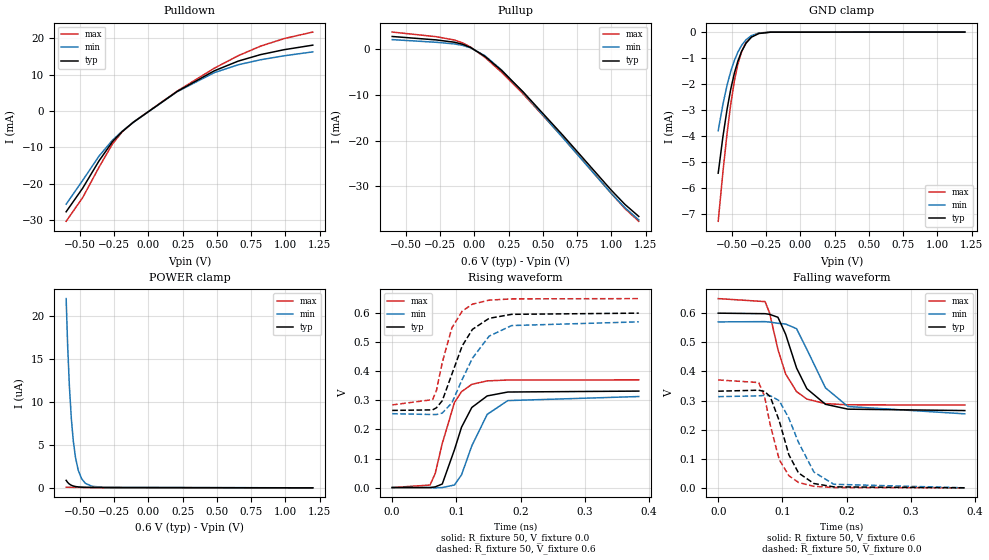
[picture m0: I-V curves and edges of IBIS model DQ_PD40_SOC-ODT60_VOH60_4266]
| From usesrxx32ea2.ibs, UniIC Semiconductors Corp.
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| DQ_PD40_SOC-ODT60_VOH60_4266
| (40 Ohm Pulldown, 60 Ohm System ODT Setting, VOH=VDDQ*0.60, 3200-4266Mbps)
[Model]   DQ_PD40_SOC-ODT60_VOH60_4266
Model_type   I/O
Vinl = 120.000mV
Vinh = 240.000mV
Vmeas = 180.000mV
Vref = 0.0mV
Cref = 0.0pF
Rref = 60.000Ohm
|   typ   min   max
|C_comp   0.834pF   0.784pF   0.884pF
C_comp_pullup   0.4170pF   0.3920pF   0.4420pF
C_comp_pulldown   0.4170pF   0.3920pF   0.4420pF
| Note: C_comp changes when the ODT circuit is enabled.
[Model Spec]
| Input threshold voltage corners
Vinl   0.1200V   0.1110V   0.1350V
Vinh   0.2400V   0.2310V   0.2550V
| Measurement voltage corners
Vmeas   0.1800V   0.1710V   0.1950V
| Timing spec test load voltage corners
Vref   0.0000V   0.0000V   0.0000V
| Dynamic Overshoot Parameters from LPDDR4_0P6 Specification
D_overshoot_ampl_h   0.30   NA   NA
D_overshoot_ampl_l   0.30   NA   NA
D_overshoot_area_h   0.1n   NA   NA
D_overshoot_area_l   0.1n   NA   NA
[Voltage Range]   0.6000V   0.5700V   0.6500V
[Pullup Reference]   0.6000V   0.5700V   0.6500V
| Junction Temperature (Ambient temp is 35C typ 95C min -40C max)
[Temperature Range]   50.0   110.0   -40.0
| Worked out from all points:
|   slope of the pulldown table from 0 to 0.09 V, typ, clamps not added: 37.5 ohm
|   slope of the pullup table from 0 to 0.09 V, typ, clamps not added: 49.6 ohm
|   GND clamp passes 1 mA (typ) near -0.45 V on its own axis
|   rising waveform, R_fixture 50, V_fixture 0.0: 20-80 % time 31.9ps typ, 36.1ps min, 27.6ps max; typ from 0 V to 0.332 V
|   falling waveform, R_fixture 50, V_fixture 0.6: 20-80 % time 36.6ps typ, 44.7ps min, 30.1ps max; typ from 0.6 V to 0.265 V
|   rising waveform, R_fixture 50, V_fixture 0.6: 20-80 % time 36.4ps typ, 45.7ps min, 27.6ps max; typ from 0.265 V to 0.6 V
|   falling waveform, R_fixture 50, V_fixture 0.0: 20-80 % time 29.8ps typ, 38.2ps min, 25.6ps max; typ from 0.332 V to 0 V
[Pulldown]
|   Voltage   I(typ)   I(min)   I(max)
-600mV    -27.74mA   -25.65mA   -30.36mA
-479.4mV  -21.24mA   -19.1mA    -23.84mA
-360.6mV  -13.75mA   -12.43mA   -15.5mA
-261.6mV  -8.423mA   -8.009mA   -9.041mA
-191.4mV  -5.659mA   -5.575mA   -5.739mA
-108.6mV  -3.064mA   -3.066mA   -3.02mA
210mV     5.393mA    5.318mA    5.481mA
481.8mV   11.09mA    10.59mA    11.81mA
656.4mV   13.76mA    12.75mA    15.25mA
818.4mV   15.54mA    14.12mA    17.87mA
991.2mV   16.9mA     15.22mA    19.96mA
1.2V      18.15mA    16.3mA     21.76mA
[GND Clamp]
|   Voltage   I(typ)   I(min)   I(max)
-600mV    -5.44mA    -3.802mA   -7.294mA
-565.8mV  -4.041mA   -2.789mA   -5.405mA
-535.2mV  -2.974mA   -2.045mA   -3.902mA
-508.2mV  -2.194mA   -1.511mA   -2.769mA
-481.2mV  -1.568mA   -1.084mA   -1.86mA
-456mV    -1.113mA   -769.2uA   -1.229mA
-429mV    -741.6uA   -510.5uA   -756.3uA
-396.6mV  -428.1uA   -294.1uA   -396.7uA
-357mV    -196.9uA   -136.7uA   -160uA
-303mV    -56.19uA   -40.99uA   -37.04uA
-216.6mV  -4.962uA   -4.45uA    -2.042uA
1.2V      0A         0A         0A
[Pullup]
|   Voltage   I(typ)   I(min)   I(max)
-600mV    2.847mA    2.16mA     3.822mA
-277.8mV  2.093mA    1.573mA    2.795mA
-144.6mV  1.58mA     1.207mA    2.065mA
-87mV     1.141mA    901.9uA    1.451mA
-27.6mV   424.6uA    349.9uA    523.8uA
76.8mV    -1.511mA   -1.368mA   -1.731mA
199.2mV   -4.645mA   -4.526mA   -5.034mA
355.8mV   -9.325mA   -9.456mA   -9.771mA
643.8mV   -18.78mA   -19.32mA   -19.25mA
1V        -30.93mA   -31.63mA   -31.64mA
1.099V    -34.03mA   -34.74mA   -34.95mA
1.2V      -36.67mA   -37.43mA   -37.73mA
[POWER Clamp]
|   Voltage   I(typ)   I(min)   I(max)
-600mV    870.6nA    21.99uA    72.65nA
-589.2mV  630.2nA    16.59uA    68.66nA
-576.6mV  439nA      11.87uA    64.76nA
-562.2mV  298.6nA    8.053uA    60.55nA
-547.8mV  210.8nA    5.444uA    56.57nA
-531.6mV  149.2nA    3.499uA    52.36nA
-511.8mV  106.2nA    2.041uA    47.56nA
-486.6mV  77.19nA    1.041uA    41.98nA
-459.6mV  61.25nA    521.5nA    36.6nA
-411mV    46.96nA    175nA      28.35nA
-319.2mV  33.34nA    56.57nA    16.92nA
1.2V      0A         0A         0A
[Ramp]
|   typ   min   max
| 20% - 80%
dV/dt_r   199.06m/31.85p   187.84m/36.08p   222.28m/27.64p
dV/dt_f   200.72m/36.59p   189.47m/44.70p   219.39m/30.09p
| 25% - 75%
|dV/dt_r   165.88m/25.19p   156.53m/28.57p   185.23m/21.78p
|dV/dt_f   167.26m/28.84p   157.89m/35.34p   182.82m/23.68p
R_load = 50
[Rising Waveform]
R_fixture = 50
V_fixture = 0.0
|   Time   V(typ)   V(min)   V(max)
0s        154.1uV    137uV      73.21uV
59ps      234.1uV    -295.8uV   8.761mV
67ps      2.405mV    -843.8uV   48.45mV
78ps      12.41mV    131.3uV    151.8mV
97ps      130.4mV    8.965mV    292.8mV
108ps     207.8mV    43.94mV    330mV
124ps     275.6mV    143.6mV    355.1mV
148ps     315.3mV    252mV      367mV
180ps     328.7mV    299.2mV    370mV
384ps     331.9mV    313.2mV    370.5mV
[Falling Waveform]
R_fixture   = 50
V_fixture   = 0.6
V_fixture_min = 0.57
V_fixture_max = 0.65
|   Time   V(typ)   V(min)   V(max)
0s        600mV      570mV      650mV
73ps      598.2mV    570.9mV    639.7mV
80ps      596mV      569.5mV    600.6mV
93ps      585.9mV    565.2mV    475.3mV
105ps     527.5mV    562.7mV    391.2mV
122ps     411.7mV    546.7mV    330.6mV
138ps     340.6mV    475.9mV    305.1mV
167ps     287mV      343.5mV    289.3mV
202ps     270.3mV    279.4mV    285.2mV
384ps     265.5mV    254.2mV    284.4mV
[Rising Waveform]
R_fixture   = 50
V_fixture   = 0.6
V_fixture_min = 0.57
V_fixture_max = 0.65
|   Time   V(typ)   V(min)   V(max)
0s        265.4mV    254.1mV    284.4mV
63ps      267.3mV    251.3mV    302.5mV
69ps      274.6mV    251.3mV    334.7mV
78ps      298.9mV    256.3mV    430.3mV
93ps      390.4mV    291.6mV    549.5mV
109ps     487.2mV    371.9mV    606.9mV
125ps     544.3mV    445.1mV    631mV
151ps     582.2mV    521mV      644.7mV
186ps     595.9mV    557.3mV    649mV
384ps     600mV      570mV      650mV
[Falling Waveform]
R_fixture = 50
V_fixture = 0.0
|   Time   V(typ)   V(min)   V(max)
0s        332mV      313.3mV    370.6mV
63ps      335.4mV    315.9mV    361.7mV
72ps      331.4mV    317.7mV    315.8mV
81ps      313.1mV    316.6mV    216.5mV
95ps      230.6mV    299.5mV    96.9mV
110ps     113.8mV    239.3mV    41.9mV
125ps     51.38mV    156.5mV    18.54mV
149ps     14.93mV    54.36mV    5.217mV
180ps     3.393mV    12.27mV    1.123mV
384ps     206uV      212uV      92uV
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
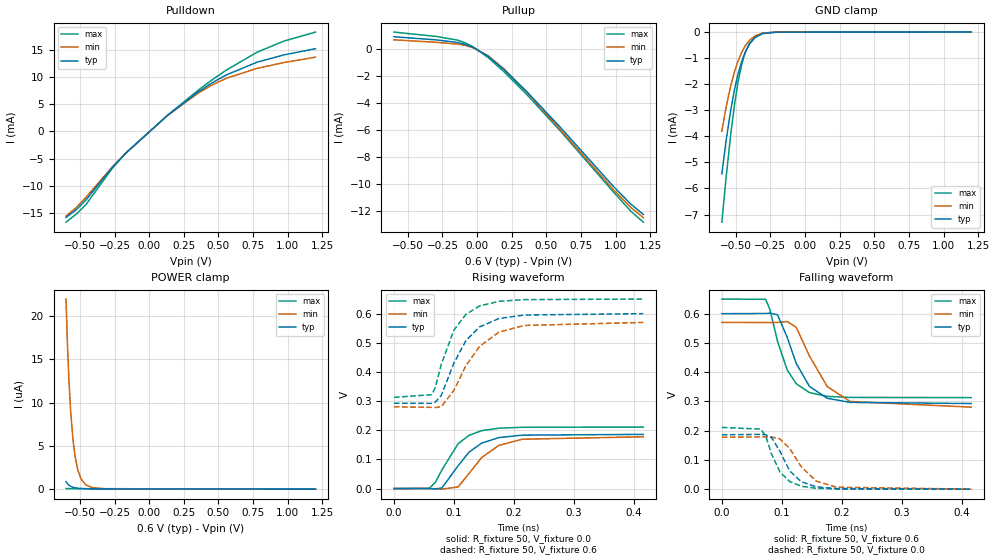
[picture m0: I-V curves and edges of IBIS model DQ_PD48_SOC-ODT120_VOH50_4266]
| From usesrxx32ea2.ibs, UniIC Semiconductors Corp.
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| DQ_PD48_SOC-ODT120_VOH50_4266
| (48 Ohm Pulldown, 120 Ohm System ODT Setting, VOH=VDDQ*0.50, 3200-4266Mbps)
[Model]   DQ_PD48_SOC-ODT120_VOH50_4266
Model_type   I/O
Vinl = 90.000mV
Vinh = 210.000mV
Vmeas = 150.000mV
Vref = 0.0mV
Cref = 0.0pF
Rref = 120.000Ohm
|   typ   min   max
|C_comp   0.834pF   0.784pF   0.884pF
C_comp_pullup   0.4170pF   0.3920pF   0.4420pF
C_comp_pulldown   0.4170pF   0.3920pF   0.4420pF
| Note: C_comp changes when the ODT circuit is enabled.
[Model Spec]
| Input threshold voltage corners
Vinl   0.0900V   0.0825V   0.1025V
Vinh   0.2100V   0.2025V   0.2225V
| Measurement voltage corners
Vmeas   0.1500V   0.1425V   0.1625V
| Timing spec test load voltage corners
Vref   0.0000V   0.0000V   0.0000V
| Dynamic Overshoot Parameters from LPDDR4_0P6 Specification
D_overshoot_ampl_h   0.30   NA   NA
D_overshoot_ampl_l   0.30   NA   NA
D_overshoot_area_h   0.1n   NA   NA
D_overshoot_area_l   0.1n   NA   NA
[Voltage Range]   0.6000V   0.5700V   0.6500V
[Pullup Reference]   0.6000V   0.5700V   0.6500V
| Junction Temperature (Ambient temp is 35C typ 95C min -40C max)
[Temperature Range]   50.0   110.0   -40.0
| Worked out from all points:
|   slope of the pulldown table from 0 to 0.09 V, typ, clamps not added: 44.6 ohm
|   slope of the pullup table from 0 to 0.09 V, typ, clamps not added: 150 ohm
|   GND clamp passes 1 mA (typ) near -0.45 V on its own axis
|   rising waveform, R_fixture 50, V_fixture 0.0: 20-80 % time 45.3ps typ, 49.4ps min, 40.1ps max; typ from 0 V to 0.186 V
|   falling waveform, R_fixture 50, V_fixture 0.6: 20-80 % time 39ps typ, 47.3ps min, 32.4ps max; typ from 0.6 V to 0.293 V
|   rising waveform, R_fixture 50, V_fixture 0.6: 20-80 % time 47.1ps typ, 55.2ps min, 39.5ps max; typ from 0.293 V to 0.6 V
|   falling waveform, R_fixture 50, V_fixture 0.0: 20-80 % time 31.6ps typ, 39.2ps min, 28.1ps max; typ from 0.186 V to 0 V
[Pulldown]
|   Voltage   I(typ)   I(min)   I(max)
-600mV    -15.79mA   -15.53mA   -16.65mA
-524.4mV  -14.33mA   -13.93mA   -15.14mA
-456mV    -12.58mA   -12.09mA   -13.41mA
-267mV    -6.63mA    -6.533mA   -6.813mA
-164.4mV  -3.891mA   -3.903mA   -3.858mA
130.8mV   2.897mA    2.872mA    2.921mA
355.8mV   7.285mA    7.07mA     7.589mA
462mV     9.018mA    8.62mA     9.591mA
555.6mV   10.34mA    9.725mA    11.22mA
778.8mV   12.69mA    11.56mA    14.52mA
971.4mV   14.02mA    12.62mA    16.55mA
1.2V      15.16mA    13.61mA    18.21mA
[GND Clamp]
|   Voltage   I(typ)   I(min)   I(max)
-600mV    -5.439mA   -3.802mA   -7.294mA
-567.6mV  -4.11mA    -2.837mA   -5.5mA
-535.2mV  -2.973mA   -2.045mA   -3.902mA
-508.2mV  -2.194mA   -1.512mA   -2.769mA
-483mV    -1.606mA   -1.109mA   -1.913mA
-456mV    -1.113mA   -769.7uA   -1.229mA
-430.8mV  -763.4uA   -525.4uA   -782.8uA
-398.4mV  -442.4uA   -303.3uA   -412.3uA
-358.8mV  -205.3uA   -142.5uA   -167.5uA
-304.8mV  -58.93uA   -42.66uA   -39.07uA
-207.6mV  -3.725uA   -3.453uA   -1.424uA
1.2V      0A         0A         0A
[Pullup]
|   Voltage   I(typ)   I(min)   I(max)
-600mV    931.5uA    702.4uA    1.276mA
-294mV    697.1uA    519.5uA    954.8uA
-141mV    508.1uA    384.5uA    681.7uA
-87mV     372.5uA    291.3uA    487.5uA
-25.8mV   130.7uA    107uA      165.5uA
80.4mV    -526.3uA   -474.5uA   -615.3uA
195.6mV   -1.508mA   -1.462mA   -1.671mA
359.4mV   -3.141mA   -3.185mA   -3.356mA
604.2mV   -5.817mA   -5.987mA   -6.087mA
980.4mV   -10.12mA   -10.36mA   -10.53mA
1.11V     -11.47mA   -11.72mA   -12mA
1.2V      -12.24mA   -12.48mA   -12.81mA
[POWER Clamp]
|   Voltage   I(typ)   I(min)   I(max)
-600mV    870.7nA    21.99uA    72.65nA
-589.2mV  630.1nA    16.59uA    68.66nA
-578.4mV  461.9nA    12.46uA    65.31nA
-565.8mV  327.8nA    8.879uA    61.58nA
-549.6mV  219.3nA    5.719uA    57.05nA
-535.2mV  160.1nA    3.857uA    53.27nA
-515.4mV  112.2nA    2.246uA    48.4nA
-492mV    81.83nA    1.199uA    43.12nA
-459.6mV  61.24nA    520.9nA    36.6nA
-412.8mV  47.34nA    181.1nA    28.62nA
-319.2mV  33.36nA    56.64nA    16.92nA
1.2V      0A         0A         0A
[Ramp]
|   typ   min   max
| 20% - 80%
dV/dt_r   111.55m/45.26p   106.53m/49.42p   126.62m/40.06p
dV/dt_f   184.34m/39.04p   173.67m/47.34p   202.22m/32.44p
| 25% - 75%
|dV/dt_r   92.95m/35.92p   88.78m/39.20p   105.51m/31.69p
|dV/dt_f   153.62m/30.90p   144.73m/37.48p   168.52m/25.62p
R_load = 50
[Rising Waveform]
R_fixture = 50
V_fixture = 0.0
|   Time   V(typ)   V(min)   V(max)
0s        39.88uV    23.63uV    24.38uV
59ps      -381.8uV   300.7uV    1.033mV
69ps      -1.414mV   -524.2uV   21.13mV
80ps      2.191mV    -2.035mV   63.69mV
107ps     77.91mV    5.664mV    153.7mV
125ps     124.4mV    51.05mV    182.3mV
146ps     155.6mV    105.7mV    198.5mV
175ps     174.9mV    148.1mV    207.1mV
214ps     183.2mV    169.3mV    210.2mV
416ps     185.9mV    177.6mV    211.1mV
[Falling Waveform]
R_fixture   = 50
V_fixture   = 0.6
V_fixture_min = 0.57
V_fixture_max = 0.65
|   Time   V(typ)   V(min)   V(max)
0s        600mV      570mV      650mV
73ps      600.7mV    569.9mV    649.2mV
80ps      601.9mV    569.6mV    615.3mV
93ps      596.2mV    570.2mV    505.1mV
109ps     519.3mV    573.1mV    407.7mV
124ps     430.3mV    553.6mV    360.8mV
146ps     351.7mV    455.8mV    330.3mV
176ps     310.7mV    350.2mV    317.3mV
214ps     296.7mV    299.9mV    313.7mV
416ps     292.8mV    280.5mV    313mV
[Rising Waveform]
R_fixture   = 50
V_fixture   = 0.6
V_fixture_min = 0.57
V_fixture_max = 0.65
|   Time   V(typ)   V(min)   V(max)
0s        292.7mV    280.5mV    312.9mV
63ps      292.3mV    278.5mV    322mV
69ps      296.6mV    277.9mV    346.8mV
79ps      319.8mV    280.9mV    426.2mV
100ps     430.2mV    336.5mV    543.4mV
120ps     507.4mV    421.4mV    597.6mV
143ps     554.7mV    488.1mV    626.5mV
175ps     583mV      536.3mV    642.2mV
217ps     595.2mV    559.5mV    648.1mV
416ps     600mV      569.9mV    650mV
[Falling Waveform]
R_fixture = 50
V_fixture = 0.0
|   Time   V(typ)   V(min)   V(max)
0s        186mV      177.7mV    211.1mV
65ps      187.3mV    178.6mV    205.4mV
73ps      186.1mV    179.1mV    182.6mV
83ps      176.4mV    178.7mV    119.4mV
97ps      129.1mV    171.5mV    58.61mV
113ps     63.19mV    139.6mV    26.42mV
132ps     25.99mV    78.03mV    10.35mV
157ps     8.285mV    27.92mV    3.069mV
191ps     1.89mV     6.737mV    625.1uV
416ps     106.9uV    113.1uV    44.52uV
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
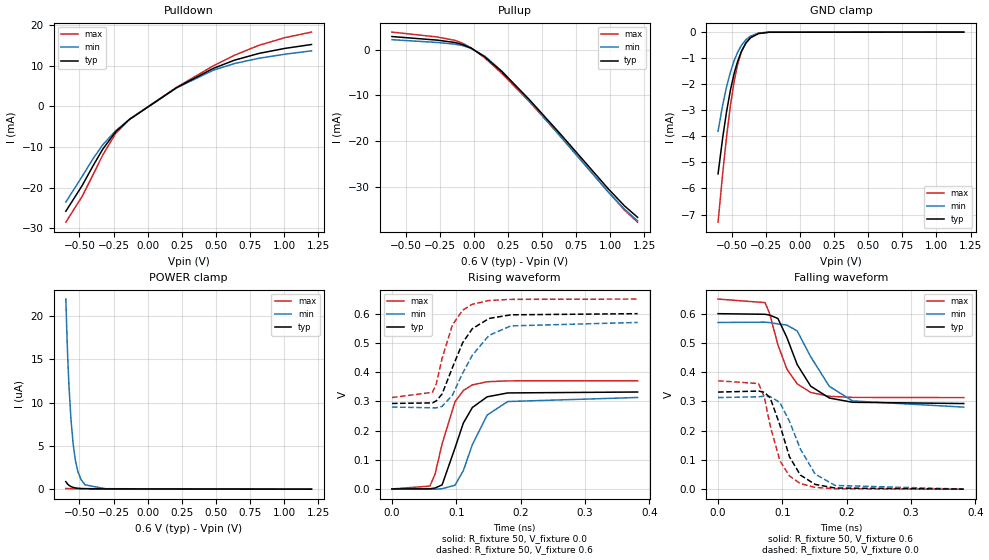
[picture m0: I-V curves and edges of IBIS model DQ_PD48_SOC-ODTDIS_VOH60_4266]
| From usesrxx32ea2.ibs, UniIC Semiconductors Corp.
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| DQ_PD48_SOC-ODTDIS_VOH60_4266
| (48 Ohm Pulldown, SOC ODT disabled setting, VOH=VDDQ*0.60 cal. point, 3200-4266Mbps)
[Model]   DQ_PD48_SOC-ODTDIS_VOH60_4266
Model_type   I/O
Vinl = 120.000mV
Vinh = 240.000mV
Vmeas = 180.000mV
Vref = 0.0mV
Cref = 0.0pF
|   typ   min   max
|C_comp   0.834pF   0.784pF   0.884pF
C_comp_pullup   0.4170pF   0.3920pF   0.4420pF
C_comp_pulldown   0.4170pF   0.3920pF   0.4420pF
| Note: C_comp changes when the ODT circuit is enabled.
[Model Spec]
| Input threshold voltage corners
Vinl   0.1200V   0.1110V   0.1350V
Vinh   0.2400V   0.2310V   0.2550V
| Measurement voltage corners
Vmeas   0.1800V   0.1710V   0.1950V
| Timing spec test load voltage corners
Vref   0.0000V   0.0000V   0.0000V
| Dynamic Overshoot Parameters from LPDDR4_0P6 Specification
D_overshoot_ampl_h   0.30   NA   NA
D_overshoot_ampl_l   0.30   NA   NA
D_overshoot_area_h   0.1n   NA   NA
D_overshoot_area_l   0.1n   NA   NA
[Voltage Range]   0.6000V   0.5700V   0.6500V
[Pullup Reference]   0.6000V   0.5700V   0.6500V
| Junction Temperature (Ambient temp is 35C typ 95C min -40C max)
[Temperature Range]   50.0   110.0   -40.0
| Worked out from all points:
|   slope of the pulldown table from 0 to 0.09 V, typ, clamps not added: 44.5 ohm
|   slope of the pullup table from 0 to 0.09 V, typ, clamps not added: 49.6 ohm
|   GND clamp passes 1 mA (typ) near -0.45 V on its own axis
|   rising waveform, R_fixture 50, V_fixture 0.0: 20-80 % time 32ps typ, 36.3ps min, 27.7ps max; typ from 0 V to 0.332 V
|   falling waveform, R_fixture 50, V_fixture 0.6: 20-80 % time 39.6ps typ, 48.2ps min, 32.7ps max; typ from 0.6 V to 0.293 V
|   rising waveform, R_fixture 50, V_fixture 0.6: 20-80 % time 37ps typ, 45.9ps min, 27.7ps max; typ from 0.293 V to 0.6 V
|   falling waveform, R_fixture 50, V_fixture 0.0: 20-80 % time 31.4ps typ, 39.1ps min, 27.4ps max; typ from 0.332 V to 0 V
[Pulldown]
|   Voltage   I(typ)   I(min)   I(max)
-600mV    -25.78mA   -23.53mA   -28.46mA
-481.2mV  -19.52mA   -17.27mA   -22.18mA
-400.2mV  -14.61mA   -12.86mA   -16.79mA
-330mV    -10.56mA   -9.488mA   -12.01mA
-234.6mV  -6.263mA   -5.995mA   -6.65mA
-133.8mV  -3.233mA   -3.221mA   -3.206mA
211.8mV   4.574mA    4.505mA    4.659mA
481.8mV   9.314mA    8.873mA    9.947mA
636.6mV   11.32mA    10.5mA     12.53mA
813mV     12.96mA    11.77mA    14.94mA
1.004V    14.2mA     12.77mA    16.83mA
1.2V      15.16mA    13.61mA    18.21mA
[GND Clamp]
|   Voltage   I(typ)   I(min)   I(max)
-600mV    -5.44mA    -3.803mA   -7.293mA
-565.8mV  -4.041mA   -2.789mA   -5.405mA
-537mV    -3.03mA    -2.085mA   -3.984mA
-508.2mV  -2.193mA   -1.513mA   -2.769mA
-481.2mV  -1.568mA   -1.083mA   -1.86mA
-457.8mV  -1.141mA   -787.2uA   -1.267mA
-429mV    -741.4uA   -509.7uA   -756.1uA
-396.6mV  -428.9uA   -294.7uA   -396.9uA
-360.6mV  -212.8uA   -146.9uA   -174.7uA
-303mV    -56.2uA    -40.81uA   -37.15uA
-227.4mV  -6.904uA   -5.978uA   -3.035uA
1.2V      0A         0A         0A
[Pullup]
|   Voltage   I(typ)   I(min)   I(max)
-600mV    2.847mA    2.16mA     3.822mA
-268.8mV  2.067mA    1.554mA    2.759mA
-139.2mV  1.548mA    1.186mA    2.02mA
-85.2mV   1.123mA    889uA      1.427mA
-20.4mV   319.4uA    265.2uA    393uA
80.4mV    -1.596mA   -1.447mA   -1.819mA
204.6mV   -4.797mA   -4.683mA   -5.19mA
399mV     -10.69mA   -10.9mA    -11.14mA
629.4mV   -18.29mA   -18.82mA   -18.76mA
985.8mV   -30.46mA   -31.15mA   -31.14mA
1.103V    -34.14mA   -34.85mA   -35.06mA
1.2V      -36.67mA   -37.44mA   -37.73mA
[POWER Clamp]
|   Voltage   I(typ)   I(min)   I(max)
-600mV    870.6nA    21.99uA    72.65nA
-589.2mV  630.2nA    16.59uA    68.66nA
-583.8mV  538.6nA    14.39uA    66.96nA
-576.6mV  439.6nA    11.87uA    64.76nA
-562.2mV  298.7nA    8.059uA    60.54nA
-546mV    201.8nA    5.192uA    56.09nA
-529.8mV  143.9nA    3.333uA    51.9nA
-511.8mV  106nA      2.046uA    47.56nA
-488.4mV  78.51nA    1.092uA    42.35nA
-457.8mV  60.4nA     497.3nA    36.26nA
-310.2mV  32.34nA    53.65nA    16.04nA
1.2V      0A         0A         0A
[Ramp]
|   typ   min   max
| 20% - 80%
dV/dt_r   199.04m/31.96p   187.82m/36.27p   222.27m/27.70p
dV/dt_f   184.34m/39.59p   173.63m/48.23p   202.23m/32.68p
| 25% - 75%
|dV/dt_r   165.87m/25.26p   156.52m/28.71p   185.23m/21.83p
|dV/dt_f   153.62m/31.27p   144.69m/38.15p   168.53m/25.78p
R_load = 50
[Rising Waveform]
R_fixture = 50
V_fixture = 0.0
|   Time   V(typ)   V(min)   V(max)
0s        177.8uV    163.1uV    83.28uV
59ps      598.4uV    -307.3uV   9.952mV
67ps      3.254mV    -614.4uV   50.5mV
78ps      14.01mV    955.7uV    154.4mV
98ps      140mV      12.78mV    298.2mV
111ps     225.4mV    62.77mV    337.1mV
125ps     278.8mV    151.5mV    356.2mV
148ps     315.4mV    252.7mV    367mV
180ps     328.7mV    299.3mV    370mV
382ps     331.9mV    313.2mV    370.5mV
[Falling Waveform]
R_fixture   = 50
V_fixture   = 0.6
V_fixture_min = 0.57
V_fixture_max = 0.65
|   Time   V(typ)   V(min)   V(max)
0s        600mV      570mV      650mV
73ps      598mV      571mV      637.9mV
80ps      595.3mV    569.7mV    601.9mV
93ps      583.7mV    565mV      493.9mV
107ps     518.6mV    561mV      410.4mV
123ps     426.2mV    541mV      360.2mV
144ps     352.3mV    452.9mV    330.8mV
173ps     311.7mV    351.7mV    317.6mV
209ps     297.2mV    301.8mV    313.9mV
382ps     292.8mV    280.6mV    313mV
[Rising Waveform]
R_fixture   = 50
V_fixture   = 0.6
V_fixture_min = 0.57
V_fixture_max = 0.65
|   Time   V(typ)   V(min)   V(max)
0s        292.7mV    280.5mV    312.9mV
63ps      294.6mV    277.8mV    330.8mV
69ps      301.7mV    277.8mV    359.7mV
78ps      325.1mV    282.7mV    446.8mV
94ps      415.3mV    320.8mV    561.5mV
110ps     500.6mV    396.8mV    611.9mV
125ps     548.6mV    457.9mV    632.3mV
151ps     583.6mV    525.9mV    645.1mV
185ps     596.1mV    558.2mV    649mV
382ps     600mV      570mV      650mV
[Falling Waveform]
R_fixture = 50
V_fixture = 0.0
|   Time   V(typ)   V(min)   V(max)
0s        332mV      313.3mV    370.6mV
63ps      335.5mV    315.9mV    361.1mV
72ps      331.3mV    317.8mV    314.4mV
81ps      312.3mV    316.8mV    217.4mV
96ps      220.4mV    296.5mV    98.04mV
111ps     111mV      232.3mV    45.28mV
128ps     48.31mV    137.4mV    19.22mV
151ps     16.28mV    51.42mV    6.199mV
182ps     4.046mV    12.85mV    1.458mV
382ps     228.4uV    238uV      101.9uV
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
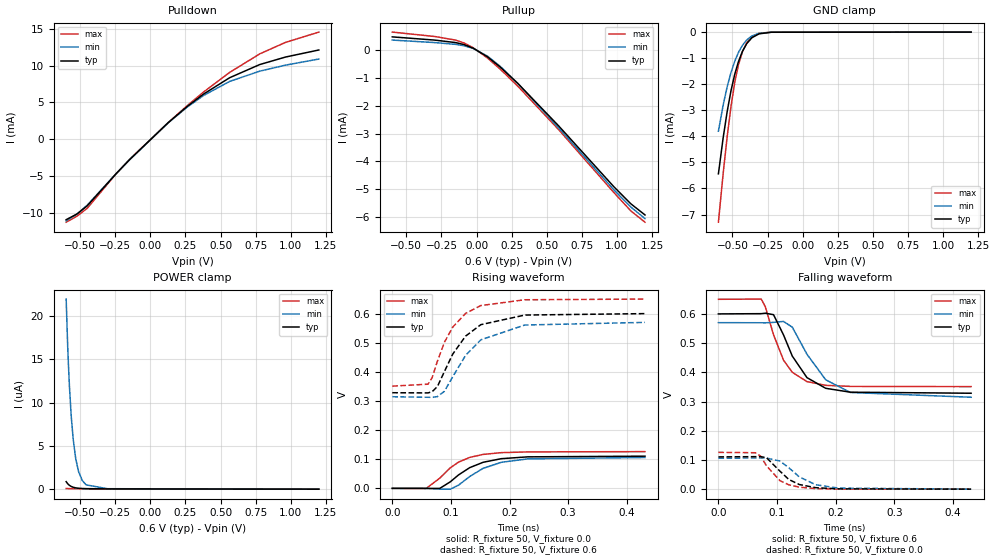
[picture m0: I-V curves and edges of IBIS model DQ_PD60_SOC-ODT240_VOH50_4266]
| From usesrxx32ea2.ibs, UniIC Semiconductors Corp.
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| DQ_PD60_SOC-ODT240_VOH50_4266
| (60 Ohm Pulldown, 240 Ohm System ODT Setting, VOH=VDDQ*0.50, 3200-4266Mbps)
[Model]   DQ_PD60_SOC-ODT240_VOH50_4266
Model_type   I/O
Vinl = 90.000mV
Vinh = 210.000mV
Vmeas = 150.000mV
Vref = 0.0mV
Cref = 0.0pF
Rref = 240.000Ohm
|   typ   min   max
|C_comp   0.834pF   0.784pF   0.884pF
C_comp_pullup   0.4170pF   0.3920pF   0.4420pF
C_comp_pulldown   0.4170pF   0.3920pF   0.4420pF
| Note: C_comp changes when the ODT circuit is enabled.
[Model Spec]
| Input threshold voltage corners
Vinl   0.0900V   0.0825V   0.1025V
Vinh   0.2100V   0.2025V   0.2225V
| Measurement voltage corners
Vmeas   0.1500V   0.1425V   0.1625V
| Timing spec test load voltage corners
Vref   0.0000V   0.0000V   0.0000V
| Dynamic Overshoot Parameters from LPDDR4_0P6 Specification
D_overshoot_ampl_h   0.30   NA   NA
D_overshoot_ampl_l   0.30   NA   NA
D_overshoot_area_h   0.1n   NA   NA
D_overshoot_area_l   0.1n   NA   NA
[Voltage Range]   0.6000V   0.5700V   0.6500V
[Pullup Reference]   0.6000V   0.5700V   0.6500V
| Junction Temperature (Ambient temp is 35C typ 95C min -40C max)
[Temperature Range]   50.0   110.0   -40.0
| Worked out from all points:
|   slope of the pulldown table from 0 to 0.09 V, typ, clamps not added: 55.8 ohm
|   slope of the pullup table from 0 to 0.09 V, typ, clamps not added: 306 ohm
|   GND clamp passes 1 mA (typ) near -0.45 V on its own axis
|   rising waveform, R_fixture 50, V_fixture 0.0: 20-80 % time 54.2ps typ, 57ps min, 47.9ps max; typ from 0 V to 0.11 V
|   falling waveform, R_fixture 50, V_fixture 0.6: 20-80 % time 43ps typ, 51.7ps min, 35.9ps max; typ from 0.6 V to 0.328 V
|   rising waveform, R_fixture 50, V_fixture 0.6: 20-80 % time 52.8ps typ, 58.7ps min, 45.6ps max; typ from 0.328 V to 0.6 V
|   falling waveform, R_fixture 50, V_fixture 0.0: 20-80 % time 35.1ps typ, 43.3ps min, 31.9ps max; typ from 0.111 V to 0 V
[Pulldown]
|   Voltage   I(typ)   I(min)   I(max)
-600mV    -10.93mA   -11.09mA   -11.27mA
-522.6mV  -10.15mA   -10.17mA   -10.45mA
-450.6mV  -9.062mA   -8.966mA   -9.394mA
-245.4mV  -4.708mA   -4.709mA   -4.725mA
-148.2mV  -2.774mA   -2.793mA   -2.737mA
127.2mV   2.254mA    2.236mA    2.268mA
260.4mV   4.419mA    4.337mA    4.525mA
377.4mV   6.117mA    5.925mA    6.389mA
564.6mV   8.352mA    7.851mA    9.073mA
778.8mV   10.14mA    9.242mA    11.59mA
962.4mV   11.16mA    10.06mA    13.15mA
1.2V      12.12mA    10.89mA    14.55mA
[GND Clamp]
|   Voltage   I(typ)   I(min)   I(max)
-600mV    -5.439mA   -3.802mA   -7.294mA
-565.8mV  -4.041mA   -2.789mA   -5.405mA
-537mV    -3.03mA    -2.085mA   -3.984mA
-510mV    -2.24mA    -1.544mA   -2.838mA
-483mV    -1.605mA   -1.109mA   -1.913mA
-457.8mV  -1.142mA   -787uA     -1.268mA
-429mV    -741.6uA   -509.7uA   -756.5uA
-398.4mV  -442.2uA   -303.1uA   -412uA
-360.6mV  -212.9uA   -146.2uA   -174.7uA
-310.2mV  -67.3uA    -48.24uA   -45.78uA
-223.8mV  -6.223uA   -5.407uA   -2.647uA
1.2V      0A         0A         0A
[Pullup]
|   Voltage   I(typ)   I(min)   I(max)
-600mV    465uA      350.7uA    636.6uA
-297.6mV  349.4uA    260.6uA    478.3uA
-148.2mV  259.6uA    196.2uA    348.7uA
-88.8mV   187.9uA    146.9uA    245.3uA
-24mV     60.47uA    49.58uA    76.28uA
78.6mV    -251.8uA   -226.6uA   -294.5uA
168.6mV   -617uA     -589.6uA   -690.7uA
294.6mV   -1.207mA   -1.206mA   -1.305mA
584.4mV   -2.723mA   -2.796mA   -2.857mA
978.6mV   -4.91mA    -5.02mA    -5.117mA
1.099V    -5.519mA   -5.635mA   -5.773mA
1.2V      -5.919mA   -6.049mA   -6.179mA
[POWER Clamp]
|   Voltage   I(typ)   I(min)   I(max)
-600mV    870.6nA    21.99uA    72.65nA
-589.2mV  630.2nA    16.59uA    68.66nA
-583.8mV  538.8nA    14.39uA    66.96nA
-576.6mV  439.1nA    11.88uA    64.76nA
-564mV    312.8nA    8.451uA    61.06nA
-549.6mV  219.1nA    5.725uA    57.05nA
-531.6mV  149nA      3.5uA      52.35nA
-511.8mV  105.9nA    2.042uA    47.55nA
-484.8mV  75.68nA    990.5nA    41.6nA
-457.8mV  60.46nA    496.7nA    36.26nA
-304.8mV  31.78nA    52.13nA    15.53nA
1.2V      0A         0A         0A
[Ramp]
|   typ   min   max
| 20% - 80%
dV/dt_r   66.28m/54.21p   63.59m/56.96p   75.64m/47.90p
dV/dt_f   162.94m/42.97p   153.18m/51.73p   179.39m/35.91p
| 25% - 75%
|dV/dt_r   55.24m/43.00p   52.99m/45.18p   63.03m/37.91p
|dV/dt_f   135.78m/34.04p   127.65m/41.06p   149.49m/28.35p
R_load = 50
[Rising Waveform]
R_fixture = 50
V_fixture = 0.0
|   Time   V(typ)   V(min)   V(max)
0s        14.37uV    140.1nV    12.65uV
58ps      -427.2uV   254.3uV    19.28uV
81ps      -88.37uV   -2.522mV   35.04mV
99ps      22.54mV    -2.764mV   70.84mV
113ps     46.17mV    11.01mV    90.03mV
132ps     71.12mV    40.69mV    106.3mV
155ps     89.6mV     68.78mV    116.6mV
186ps     101.9mV    89.52mV    122.6mV
231ps     108.2mV    101.2mV    125.2mV
431ps     110.5mV    106mV      126.1mV
[Falling Waveform]
R_fixture   = 50
V_fixture   = 0.6
V_fixture_min = 0.57
V_fixture_max = 0.65
|   Time   V(typ)   V(min)   V(max)
0s        600mV      570mV      650mV
73ps      600.8mV    569.7mV    650.8mV
80ps      602.4mV    569.5mV    624.6mV
94ps      597.3mV    571mV      528.7mV
111ps     528.3mV    574.3mV    441.7mV
126ps     455.6mV    554.6mV    400mV
151ps     381.9mV    462mV      368.2mV
183ps     345.3mV    374.4mV    355.5mV
225ps     332mV      331mV      351.8mV
431ps     328.4mV    314.7mV    351mV
[Rising Waveform]
R_fixture   = 50
V_fixture   = 0.6
V_fixture_min = 0.57
V_fixture_max = 0.65
|   Time   V(typ)   V(min)   V(max)
0s        328.4mV    314.6mV    351mV
61ps      327.7mV    312.8mV    357.7mV
68ps      332mV      312.3mV    380.4mV
77ps      349.8mV    315.1mV    437mV
89ps      401.5mV    333.6mV    501.8mV
103ps     460.7mV    383mV      553.4mV
125ps     522.7mV    456.6mV    600.8mV
151ps     562.1mV    510.1mV    627.7mV
226ps     595.1mV    560.9mV    647.6mV
431ps     600mV      569.9mV    650mV
[Falling Waveform]
R_fixture = 50
V_fixture = 0.0
|   Time   V(typ)   V(min)   V(max)
0s        110.5mV    106.1mV    126.1mV
63ps      111.3mV    106.6mV    124.7mV
72ps      111.3mV    106.8mV    113.2mV
82ps      107.9mV    106.5mV    79.98mV
105ps     61.51mV    96.22mV    28.96mV
120ps     33.26mV    73.52mV    14.97mV
138ps     15.91mV    42.12mV    6.766mV
166ps     5.079mV    15.11mV    1.982mV
205ps     1.107mV    3.596mV    385.5uV
431ps     75.89uV    82.3uV     27.7uV
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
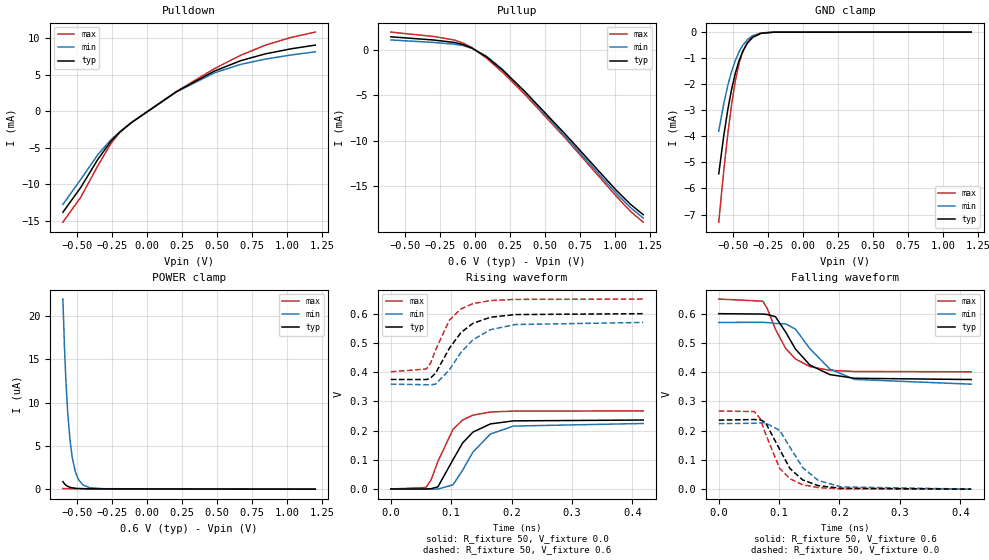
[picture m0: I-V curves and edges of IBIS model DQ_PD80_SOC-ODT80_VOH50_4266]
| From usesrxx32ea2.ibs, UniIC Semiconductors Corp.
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| DQ_PD80_SOC-ODT80_VOH50_4266
| (80 Ohm Pulldown, 80 Ohm System ODT Setting, VOH=VDDQ*0.50, 3200-4266Mbps)
[Model]   DQ_PD80_SOC-ODT80_VOH50_4266
Model_type   I/O
Vinl = 90.000mV
Vinh = 210.000mV
Vmeas = 150.000mV
Vref = 0.0mV
Cref = 0.0pF
Rref = 80.000Ohm
|   typ   min   max
|C_comp   0.834pF   0.784pF   0.884pF
C_comp_pullup   0.4170pF   0.3920pF   0.4420pF
C_comp_pulldown   0.4170pF   0.3920pF   0.4420pF
| Note: C_comp changes when the ODT circuit is enabled.
[Model Spec]
| Input threshold voltage corners
Vinl   0.0900V   0.0825V   0.1025V
Vinh   0.2100V   0.2025V   0.2225V
| Measurement voltage corners
Vmeas   0.1500V   0.1425V   0.1625V
| Timing spec test load voltage corners
Vref   0.0000V   0.0000V   0.0000V
| Dynamic Overshoot Parameters from LPDDR4_0P6 Specification
D_overshoot_ampl_h   0.30   NA   NA
D_overshoot_ampl_l   0.30   NA   NA
D_overshoot_area_h   0.1n   NA   NA
D_overshoot_area_l   0.1n   NA   NA
[Voltage Range]   0.6000V   0.5700V   0.6500V
[Pullup Reference]   0.6000V   0.5700V   0.6500V
| Junction Temperature (Ambient temp is 35C typ 95C min -40C max)
[Temperature Range]   50.0   110.0   -40.0
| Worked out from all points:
|   slope of the pulldown table from 0 to 0.09 V, typ, clamps not added: 75.5 ohm
|   slope of the pullup table from 0 to 0.09 V, typ, clamps not added: 101 ohm
|   GND clamp passes 1 mA (typ) near -0.45 V on its own axis
|   rising waveform, R_fixture 50, V_fixture 0.0: 20-80 % time 41.3ps typ, 45.1ps min, 35.6ps max; typ from 0 V to 0.236 V
|   falling waveform, R_fixture 50, V_fixture 0.6: 20-80 % time 47.8ps typ, 56.8ps min, 39.9ps max; typ from 0.6 V to 0.375 V
|   rising waveform, R_fixture 50, V_fixture 0.6: 20-80 % time 45.8ps typ, 52.3ps min, 36.4ps max; typ from 0.375 V to 0.6 V
|   falling waveform, R_fixture 50, V_fixture 0.0: 20-80 % time 37.9ps typ, 45.1ps min, 34ps max; typ from 0.236 V to 0 V
[Pulldown]
|   Voltage   I(typ)   I(min)   I(max)
-600mV    -13.84mA   -12.77mA   -15.2mA
-472.2mV  -10.43mA   -9.327mA   -11.77mA
-351.6mV  -6.619mA   -5.966mA   -7.489mA
-256.2mV  -4.08mA    -3.882mA   -4.38mA
-195mV    -2.877mA   -2.828mA   -2.927mA
-112.2mV  -1.574mA   -1.575mA   -1.549mA
208.2mV   2.657mA    2.624mA    2.691mA
480mV     5.497mA    5.261mA    5.831mA
667.2mV   6.918mA    6.414mA    7.657mA
841.8mV   7.849mA    7.132mA    9.035mA
1.027V    8.549mA    7.703mA    10.11mA
1.2V      9.057mA    8.141mA    10.84mA
[GND Clamp]
|   Voltage   I(typ)   I(min)   I(max)
-600mV    -5.439mA   -3.802mA   -7.294mA
-564mV    -3.973mA   -2.741mA   -5.311mA
-535.2mV  -2.973mA   -2.045mA   -3.902mA
-508.2mV  -2.193mA   -1.512mA   -2.769mA
-481.2mV  -1.568mA   -1.083mA   -1.86mA
-454.2mV  -1.087mA   -747.9uA   -1.192mA
-429mV    -742.9uA   -509.7uA   -756.9uA
-396.6mV  -430uA     -293.1uA   -396.4uA
-357mV    -198.3uA   -135.8uA   -160uA
-297.6mV  -49.19uA   -36.07uA   -31.62uA
-205.8mV  -3.516uA   -3.285uA   -1.327uA
1.2V      0A         0A         0A
[Pullup]
|   Voltage   I(typ)   I(min)   I(max)
-600mV    1.396mA    1.053mA    1.912mA
-294mV    1.044mA    778.6uA    1.43mA
-146.4mV  775.6uA    586.1uA    1.042mA
-83.4mV   539.6uA    423.7uA    703.5uA
-24mV     182.2uA    149.6uA    230.2uA
84mV      -822.5uA   -743.6uA   -958.9uA
193.8mV   -2.21mA    -2.14mA    -2.452mA
354mV     -4.566mA   -4.62mA    -4.885mA
642mV     -9.234mA   -9.497mA   -9.653mA
1.007V    -15.4mA    -15.74mA   -16.05mA
1.11V     -16.96mA   -17.32mA   -17.74mA
1.2V      -18.09mA   -18.46mA   -18.91mA
[POWER Clamp]
|   Voltage   I(typ)   I(min)   I(max)
-600mV    870.6nA    21.99uA    72.65nA
-589.2mV  630.2nA    16.59uA    68.66nA
-578.4mV  461.9nA    12.46uA    65.31nA
-565.8mV  327.9nA    8.89uA     61.58nA
-549.6mV  219.2nA    5.723uA    57.05nA
-533.4mV  154.8nA    3.676uA    52.81nA
-511.8mV  106nA      2.04uA     47.55nA
-488.4mV  78.57nA    1.09uA     42.35nA
-457.8mV  60.43nA    497.5nA    36.26nA
-407.4mV  46.26nA    163.3nA    27.8nA
-308.4mV  32.16nA    53.14nA    15.87nA
1.2V      0A         0A         0A
[Ramp]
|   typ   min   max
| 20% - 80%
dV/dt_r   141.52m/41.33p   134.47m/45.10p   160.26m/35.59p
dV/dt_f   135.04m/47.80p   126.62m/56.79p   149.25m/39.92p
| 25% - 75%
|dV/dt_r   117.94m/32.75p   112.06m/35.73p   133.55m/28.15p
|dV/dt_f   112.53m/37.83p   105.51m/45.01p   124.38m/31.57p
R_load = 50
[Rising Waveform]
R_fixture = 50
V_fixture = 0.0
|   Time   V(typ)   V(min)   V(max)
0s        106.8uV    91.54uV    53.03uV
58ps      -144.4uV   -154.8uV   4.836mV
67ps      1.057mV    -627.5uV   32.35mV
78ps      7.414mV    -158.2uV   94.26mV
103ps     100.2mV    14.13mV    204.3mV
119ps     157.8mV    64.65mV    236.2mV
136ps     194.7mV    126.5mV    252.8mV
165ps     222.7mV    188.2mV    263.4mV
203ps     233.1mV    215.3mV    266.5mV
418ps     236mV      224.2mV    267.2mV
[Falling Waveform]
R_fixture   = 50
V_fixture   = 0.6
V_fixture_min = 0.57
V_fixture_max = 0.65
|   Time   V(typ)   V(min)   V(max)
0s        600mV      570mV      650mV
73ps      598.7mV    570.5mV    642.8mV
80ps      597.4mV    569.6mV    619.4mV
94ps      589.6mV    566.7mV    546.4mV
111ps     536.6mV    565.1mV    480.7mV
127ps     479.3mV    547.4mV    445.4mV
151ps     424.4mV    480.3mV    419.1mV
184ps     391.8mV    410.9mV    406.4mV
225ps     379.2mV    375.3mV    402.4mV
418ps     374.9mV    359mV      401.3mV
[Rising Waveform]
R_fixture   = 50
V_fixture   = 0.6
V_fixture_min = 0.57
V_fixture_max = 0.65
|   Time   V(typ)   V(min)   V(max)
0s        374.9mV    358.8mV    401.2mV
59ps      374.5mV    356.8mV    410.7mV
66ps      380.3mV    356.3mV    431.1mV
74ps      395.8mV    358.7mV    475.1mV
97ps      481.4mV    407.6mV    577.9mV
116ps     535mV      467.3mV    616.1mV
136ps     567mV      510.7mV    634.5mV
165ps     587.7mV    545.2mV    644.9mV
206ps     596.9mV    562.9mV    648.9mV
418ps     600mV      570mV      650mV
[Falling Waveform]
R_fixture = 50
V_fixture = 0.0
|   Time   V(typ)   V(min)   V(max)
0s        236mV      224.3mV    267.2mV
59ps      238.2mV    225.3mV    265.4mV
69ps      236.8mV    226.8mV    240.5mV
77ps      229.5mV    227mV      192mV
101ps     135.6mV    200.9mV    70.8mV
118ps     70.54mV    143.1mV    35.54mV
139ps     31.64mV    73.82mV    15.24mV
165ps     11.94mV    29.57mV    5.39mV
203ps     3.003mV    7.836mV    1.247mV
418ps     184uV      193.9uV    82.31uV
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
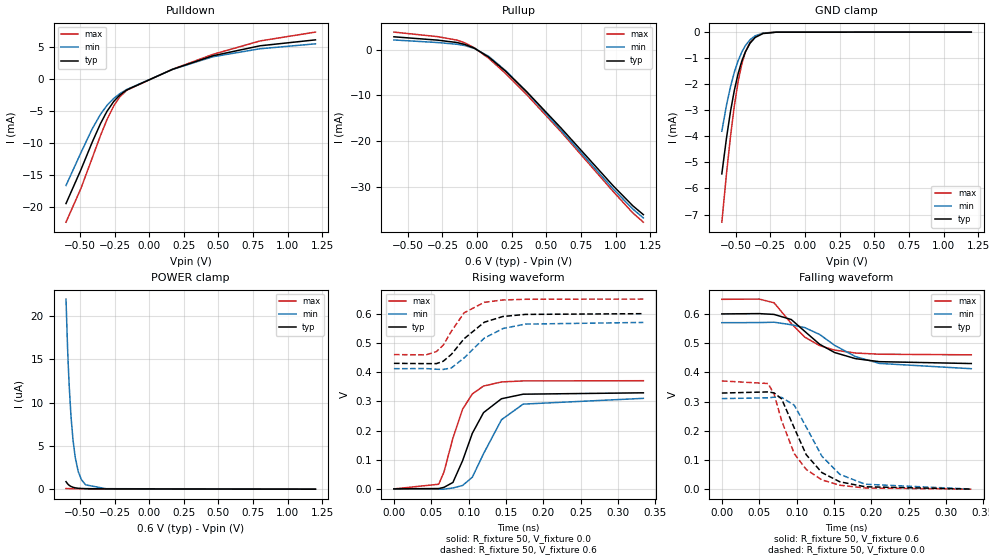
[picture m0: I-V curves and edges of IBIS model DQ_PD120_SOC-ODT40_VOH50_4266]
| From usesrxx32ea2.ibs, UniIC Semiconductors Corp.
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| DQ_PD120_SOC-ODT40_VOH50_4266
| (120 Ohm Pulldown, 40 Ohm System ODT Setting, VOH=VDDQ*0.50, 3200-4266Mbps)
[Model]   DQ_PD120_SOC-ODT40_VOH50_4266
Model_type   I/O
Vinl = 90.000mV
Vinh = 210.000mV
Vmeas = 150.000mV
Vref = 0.0mV
Cref = 0.0pF
Rref = 40.000Ohm
|   typ   min   max
|C_comp   0.834pF   0.784pF   0.884pF
C_comp_pullup   0.4170pF   0.3920pF   0.4420pF
C_comp_pulldown   0.4170pF   0.3920pF   0.4420pF
| Note: C_comp changes when the ODT circuit is enabled.
[Model Spec]
| Input threshold voltage corners
Vinl   0.0900V   0.0825V   0.1025V
Vinh   0.2100V   0.2025V   0.2225V
| Measurement voltage corners
Vmeas   0.1500V   0.1425V   0.1625V
| Timing spec test load voltage corners
Vref   0.0000V   0.0000V   0.0000V
| Dynamic Overshoot Parameters from LPDDR4_0P6 Specification
D_overshoot_ampl_h   0.30   NA   NA
D_overshoot_ampl_l   0.30   NA   NA
D_overshoot_area_h   0.1n   NA   NA
D_overshoot_area_l   0.1n   NA   NA
[Voltage Range]   0.6000V   0.5700V   0.6500V
[Pullup Reference]   0.6000V   0.5700V   0.6500V
| Junction Temperature (Ambient temp is 35C typ 95C min -40C max)
[Temperature Range]   50.0   110.0   -40.0
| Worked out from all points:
|   slope of the pulldown table from 0 to 0.09 V, typ, clamps not added: 111 ohm
|   slope of the pullup table from 0 to 0.09 V, typ, clamps not added: 50.7 ohm
|   GND clamp passes 1 mA (typ) near -0.45 V on its own axis
|   rising waveform, R_fixture 50, V_fixture 0.0: 20-80 % time 32.9ps typ, 37.9ps min, 27.8ps max; typ from 0 V to 0.329 V
|   falling waveform, R_fixture 50, V_fixture 0.6: 20-80 % time 54ps typ, 64.2ps min, 44.8ps max; typ from 0.6 V to 0.43 V
|   rising waveform, R_fixture 50, V_fixture 0.6: 20-80 % time 39.5ps typ, 43.4ps min, 30.5ps max; typ from 0.43 V to 0.6 V
|   falling waveform, R_fixture 50, V_fixture 0.0: 20-80 % time 40.3ps typ, 45.5ps min, 36.9ps max; typ from 0.329 V to 0 V
[Pulldown]
|   Voltage   I(typ)   I(min)   I(max)
-600mV    -19.41mA   -16.6mA    -22.31mA
-492mV    -14.13mA   -11.48mA   -17.04mA
-411mV    -9.871mA   -7.792mA   -12.33mA
-351.6mV  -6.992mA   -5.538mA   -8.852mA
-304.8mV  -5.078mA   -4.147mA   -6.376mA
-254.4mV  -3.493mA   -3.029mA   -4.178mA
-213mV    -2.555mA   -2.337mA   -2.849mA
-162.6mV  -1.738mA   -1.67mA    -1.788mA
168.6mV   1.473mA    1.457mA    1.488mA
460.2mV   3.586mA    3.435mA    3.803mA
800.4mV   5.137mA    4.674mA    5.891mA
1.2V      6.059mA    5.442mA    7.269mA
[GND Clamp]
|   Voltage   I(typ)   I(min)   I(max)
-600mV    -5.439mA   -3.802mA   -7.294mA
-565.8mV  -4.041mA   -2.789mA   -5.405mA
-537mV    -3.031mA   -2.085mA   -3.984mA
-510mV    -2.24mA    -1.544mA   -2.838mA
-483mV    -1.605mA   -1.109mA   -1.913mA
-456mV    -1.113mA   -767.2uA   -1.229mA
-430.8mV  -762.8uA   -524.3uA   -782.1uA
-396.6mV  -428.6uA   -293.2uA   -396.7uA
-358.8mV  -204.5uA   -141.2uA   -166.9uA
-303mV    -56.27uA   -40.96uA   -37.21uA
-207.6mV  -3.712uA   -3.47uA    -1.426uA
1.2V      0A         0A         0A
[Pullup]
|   Voltage   I(typ)   I(min)   I(max)
-600mV    2.791mA    2.105mA    3.822mA
-285mV    2.063mA    1.538mA    2.824mA
-144.6mV  1.539mA    1.164mA    2.066mA
-87mV     1.112mA    870.6uA    1.452mA
-18.6mV   285.6uA    234.7uA    359.3uA
85.8mV    -1.678mA   -1.52mA    -1.954mA
206.4mV   -4.744mA   -4.615mA   -5.242mA
357.6mV   -9.188mA   -9.296mA   -9.828mA
609.6mV   -17.27mA   -17.75mA   -18.09mA
984mV     -29.84mA   -30.53mA   -31.08mA
1.124V    -34.15mA   -34.85mA   -35.71mA
1.2V      -36.08mA   -36.8mA    -37.73mA
[POWER Clamp]
|   Voltage   I(typ)   I(min)   I(max)
-600mV    870.6nA    21.99uA    72.65nA
-589.2mV  630.2nA    16.59uA    68.66nA
-583.8mV  538.9nA    14.38uA    66.97nA
-576.6mV  439.2nA    11.88uA    64.76nA
-564mV    312.6nA    8.454uA    61.06nA
-549.6mV  219.4nA    5.715uA    57.05nA
-533.4mV  154.5nA    3.673uA    52.81nA
-511.8mV  106nA      2.04uA     47.56nA
-488.4mV  78.53nA    1.089uA    42.35nA
-457.8mV  60.43nA    497.2nA    36.26nA
-312mV    32.55nA    54.17nA    16.22nA
1.2V      0A         0A         0A
[Ramp]
|   typ   min   max
| 20% - 80%
dV/dt_r   197.29m/32.93p   185.91m/37.91p   222.24m/27.79p
dV/dt_f   101.90m/53.95p   94.53m/64.25p   114.03m/44.81p
| 25% - 75%
|dV/dt_r   164.41m/26.02p   154.93m/29.99p   185.20m/21.99p
|dV/dt_f   84.92m/42.60p   78.77m/50.53p   95.02m/35.38p
R_load = 50
[Rising Waveform]
R_fixture = 50
V_fixture = 0.0
|   Time   V(typ)   V(min)   V(max)
0s        278uV      262.3uV    129.6uV
60ps      1.411mV    -720.5uV   16.19mV
67ps      5.462mV    -617.4uV   57.94mV
79ps      22.29mV    3.271mV    174.3mV
92ps      97.06mV    11.97mV    273.4mV
105ps     190.5mV    40.23mV    325.3mV
120ps     261.3mV    120.6mV    352.2mV
144ps     308.8mV    236.8mV    366.3mV
173ps     324.4mV    290.4mV    369.8mV
334ps     329.1mV    310.1mV    370.5mV
[Falling Waveform]
R_fixture   = 50
V_fixture   = 0.6
V_fixture_min = 0.57
V_fixture_max = 0.65
|   Time   V(typ)   V(min)   V(max)
0s        600mV      570mV      650mV
50ps      601.1mV    570.4mV    650.9mV
70ps      598.3mV    571.7mV    638.1mV
93ps      580.8mV    562.9mV    567.3mV
111ps     540.4mV    553.2mV    520.7mV
131ps     496.1mV    529.7mV    491.5mV
151ps     467.9mV    492.6mV    476.2mV
179ps     446.9mV    453.9mV    466.2mV
211ps     436.6mV    430.6mV    462.1mV
334ps     430.2mV    412.5mV    460mV
[Rising Waveform]
R_fixture   = 50
V_fixture   = 0.6
V_fixture_min = 0.57
V_fixture_max = 0.65
|   Time   V(typ)   V(min)   V(max)
0s        430mV      411.7mV    459.9mV
43ps      429mV      412.2mV    459mV
57ps      429.1mV    409.8mV    470.3mV
66ps      437.1mV    409.1mV    492.1mV
77ps      460.8mV    414.4mV    540.1mV
94ps      514.3mV    448.5mV    602.9mV
121ps     570.7mV    516.2mV    638.8mV
146ps     590.4mV    549.3mV    646.9mV
176ps     597.5mV    564.3mV    649.3mV
334ps     600mV      570mV      650mV
[Falling Waveform]
R_fixture = 50
V_fixture = 0.0
|   Time   V(typ)   V(min)   V(max)
0s        329.2mV    310.2mV    370.6mV
62ps      333.1mV    312.9mV    361.8mV
70ps      329.6mV    315mV      325mV
80ps      309.5mV    314.3mV    235.1mV
97ps      209.5mV    287.6mV    121.6mV
113ps     118.1mV    212.9mV    67.77mV
134ps     56.82mV    112.8mV    31.82mV
158ps     25.41mV    50.89mV    13.59mV
192ps     8.368mV    17.01mV    4.179mV
334ps     399.4uV    539.4uV    187.4uV
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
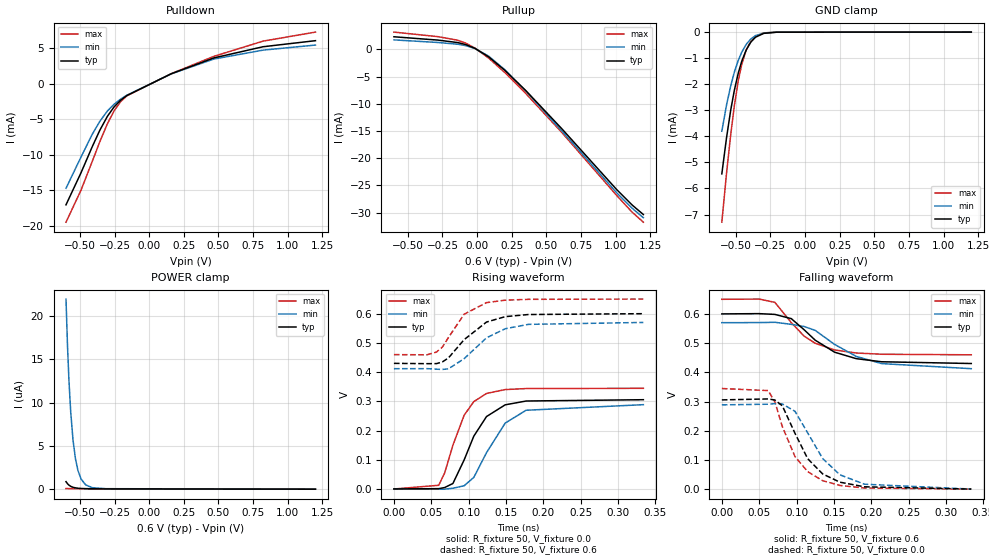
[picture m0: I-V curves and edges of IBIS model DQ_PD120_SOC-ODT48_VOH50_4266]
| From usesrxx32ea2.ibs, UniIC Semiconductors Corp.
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| DQ_PD120_SOC-ODT48_VOH50_4266
| (120 Ohm Pulldown, 48 Ohm System ODT Setting, VOH=VDDQ*0.50, 3200-4266Mbps)
[Model]   DQ_PD120_SOC-ODT48_VOH50_4266
Model_type   I/O
Vinl = 90.000mV
Vinh = 210.000mV
Vmeas = 150.000mV
Vref = 0.0mV
Cref = 0.0pF
Rref = 48.000Ohm
|   typ   min   max
|C_comp   0.834pF   0.784pF   0.884pF
C_comp_pullup   0.4170pF   0.3920pF   0.4420pF
C_comp_pulldown   0.4170pF   0.3920pF   0.4420pF
| Note: C_comp changes when the ODT circuit is enabled.
[Model Spec]
| Input threshold voltage corners
Vinl   0.0900V   0.0825V   0.1025V
Vinh   0.2100V   0.2025V   0.2225V
| Measurement voltage corners
Vmeas   0.1500V   0.1425V   0.1625V
| Timing spec test load voltage corners
Vref   0.0000V   0.0000V   0.0000V
| Dynamic Overshoot Parameters from LPDDR4_0P6 Specification
D_overshoot_ampl_h   0.30   NA   NA
D_overshoot_ampl_l   0.30   NA   NA
D_overshoot_area_h   0.1n   NA   NA
D_overshoot_area_l   0.1n   NA   NA
[Voltage Range]   0.6000V   0.5700V   0.6500V
[Pullup Reference]   0.6000V   0.5700V   0.6500V
| Junction Temperature (Ambient temp is 35C typ 95C min -40C max)
[Temperature Range]   50.0   110.0   -40.0
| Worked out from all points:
|   slope of the pulldown table from 0 to 0.09 V, typ, clamps not added: 111 ohm
|   slope of the pullup table from 0 to 0.09 V, typ, clamps not added: 60.5 ohm
|   GND clamp passes 1 mA (typ) near -0.45 V on its own axis
|   rising waveform, R_fixture 50, V_fixture 0.0: 20-80 % time 34.6ps typ, 39.9ps min, 29.7ps max; typ from 0 V to 0.306 V
|   falling waveform, R_fixture 50, V_fixture 0.6: 20-80 % time 53.6ps typ, 63.2ps min, 44.7ps max; typ from 0.6 V to 0.43 V
|   rising waveform, R_fixture 50, V_fixture 0.6: 20-80 % time 41ps typ, 45.7ps min, 32.1ps max; typ from 0.43 V to 0.6 V
|   falling waveform, R_fixture 50, V_fixture 0.0: 20-80 % time 40.6ps typ, 45.9ps min, 37ps max; typ from 0.306 V to 0 V
[Pulldown]
|   Voltage   I(typ)   I(min)   I(max)
-600mV    -17.07mA   -14.74mA   -19.52mA
-492mV    -12.57mA   -10.35mA   -15.02mA
-411mV    -8.898mA   -7.153mA   -10.98mA
-355.2mV  -6.535mA   -5.283mA   -8.138mA
-301.2mV  -4.599mA   -3.856mA   -5.651mA
-252.6mV  -3.264mA   -2.892mA   -3.819mA
-205.8mV  -2.335mA   -2.182mA   -2.534mA
-160.8mV  -1.676mA   -1.626mA   -1.71mA
159.6mV   1.398mA    1.384mA    1.41mA
467.4mV   3.63mA     3.472mA    3.855mA
822mV     5.204mA    4.727mA    5.994mA
1.2V      6.059mA    5.442mA    7.269mA
[GND Clamp]
|   Voltage   I(typ)   I(min)   I(max)
-600mV    -5.439mA   -3.802mA   -7.294mA
-565.8mV  -4.041mA   -2.789mA   -5.405mA
-535.2mV  -2.973mA   -2.046mA   -3.902mA
-510mV    -2.24mA    -1.544mA   -2.838mA
-481.2mV  -1.568mA   -1.083mA   -1.86mA
-456mV    -1.113mA   -767.6uA   -1.23mA
-423.6mV  -679.8uA   -467.1uA   -683.2uA
-391.2mV  -387.9uA   -266.4uA   -353.7uA
-357mV    -196.8uA   -135.8uA   -159.9uA
-297.6mV  -49.19uA   -36.08uA   -31.63uA
-202.2mV  -3.157uA   -3.018uA   -1.145uA
1.2V      0A         0A         0A
[Pullup]
|   Voltage   I(typ)   I(min)   I(max)
-600mV    2.327mA    1.755mA    3.187mA
-281.4mV  1.712mA    1.276mA    2.344mA
-139.2mV  1.259mA    952.8uA    1.687mA
-81.6mV   885.5uA    695.3uA    1.154mA
-15mV     194.3uA    159.9uA    244.3uA
84mV      -1.373mA   -1.241mA   -1.601mA
201mV     -3.859mA   -3.747mA   -4.271mA
354mV     -7.629mA   -7.72mA    -8.163mA
611.4mV   -14.58mA   -14.99mA   -15.26mA
1.007V    -25.75mA   -26.33mA   -26.83mA
1.119V    -28.6mA    -29.19mA   -29.92mA
1.2V      -30.35mA   -30.94mA   -31.76mA
[POWER Clamp]
|   Voltage   I(typ)   I(min)   I(max)
-600mV    870.6nA    21.99uA    72.65nA
-589.2mV  630.1nA    16.59uA    68.66nA
-578.4mV  462nA      12.46uA    65.31nA
-565.8mV  327.9nA    8.886uA    61.58nA
-549.6mV  219.4nA    5.715uA    57.05nA
-531.6mV  149.1nA    3.498uA    52.36nA
-513.6mV  108.8nA    2.145uA    47.98nA
-490.2mV  80.07nA    1.145uA    42.74nA
-457.8mV  60.43nA    496.3nA    36.26nA
-411mV    46.98nA    174.7nA    28.34nA
-313.8mV  32.75nA    54.8nA     16.39nA
1.2V      0A         0A         0A
[Ramp]
|   typ   min   max
| 20% - 80%
dV/dt_r   183.22m/34.59p   173.03m/39.90p   206.69m/29.65p
dV/dt_f   101.89m/53.55p   94.53m/63.20p   114.03m/44.70p
| 25% - 75%
|dV/dt_r   152.68m/27.33p   144.19m/31.54p   172.24m/23.45p
|dV/dt_f   84.91m/42.31p   78.77m/49.90p   95.03m/35.33p
R_load = 50
[Rising Waveform]
R_fixture = 50
V_fixture = 0.0
|   Time   V(typ)   V(min)   V(max)
0s        231.1uV    217.1uV    108uV
60ps      1.188mV    -547.9uV   12.76mV
68ps      5.007mV    -357.8uV   55.31mV
79ps      18.95mV    2.615mV    150.1mV
94ps      99.34mV    11.04mV    252.4mV
107ps     181mV      39.93mV    299.1mV
124ps     248mV      124.5mV    327mV
149ps     288.1mV    225.6mV    340.3mV
177ps     301.1mV    269.5mV    343.7mV
334ps     305.6mV    288.6mV    344.6mV
[Falling Waveform]
R_fixture   = 50
V_fixture   = 0.6
V_fixture_min = 0.57
V_fixture_max = 0.65
|   Time   V(typ)   V(min)   V(max)
0s        600mV      570mV      650mV
50ps      600.9mV    570.3mV    650.8mV
71ps      598.3mV    571.3mV    639.5mV
93ps      583.8mV    564.3mV    570.2mV
110ps     546.2mV    557mV      524.4mV
125ps     510.1mV    543.6mV    499.5mV
151ps     469mV      495.6mV    476.6mV
180ps     446.8mV    454.4mV    466.2mV
214ps     436.2mV    429.9mV    461.9mV
334ps     430.2mV    412.5mV    460mV
[Rising Waveform]
R_fixture   = 50
V_fixture   = 0.6
V_fixture_min = 0.57
V_fixture_max = 0.65
|   Time   V(typ)   V(min)   V(max)
0s        430mV      411.7mV    459.9mV
44ps      428.9mV    412mV      459.2mV
57ps      429.1mV    410mV      468.7mV
65ps      435.1mV    409.2mV    486mV
73ps      448.5mV    411.2mV    518.4mV
94ps      511.1mV    446mV      598.1mV
124ps     571.4mV    517.4mV    637.9mV
149ps     589.8mV    548.4mV    646.2mV
180ps     597.1mV    563.4mV    649.1mV
334ps     600mV      570mV      650mV
[Falling Waveform]
R_fixture = 50
V_fixture = 0.0
|   Time   V(typ)   V(min)   V(max)
0s        305.7mV    288.7mV    344.6mV
62ps      309mV      290.9mV    337.6mV
71ps      305.3mV    292.8mV    299.3mV
81ps      285.5mV    291.9mV    214.3mV
98ps      191.1mV    266.6mV    111.5mV
115ps     104.3mV    192.6mV    59.99mV
135ps     52.24mV    105.1mV    29.26mV
158ps     24.13mV    49.38mV    12.93mV
191ps     8.237mV    17.11mV    4.092mV
334ps     365.9uV    498.3uV    156uV
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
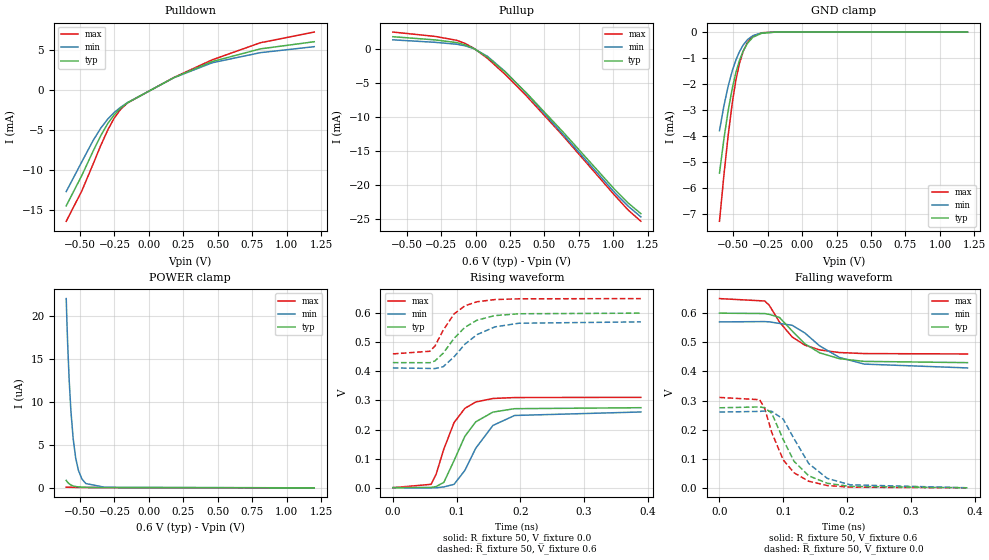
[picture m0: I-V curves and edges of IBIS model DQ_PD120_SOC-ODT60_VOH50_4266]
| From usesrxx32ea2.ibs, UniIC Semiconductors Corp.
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| DQ_PD120_SOC-ODT60_VOH50_4266
| (120 Ohm Pulldown, 60 Ohm System ODT Setting, VOH=VDDQ*0.50, 3200-4266Mbps)
[Model]   DQ_PD120_SOC-ODT60_VOH50_4266
Model_type   I/O
Vinl = 90.000mV
Vinh = 210.000mV
Vmeas = 150.000mV
Vref = 0.0mV
Cref = 0.0pF
Rref = 60.000Ohm
|   typ   min   max
|C_comp   0.834pF   0.784pF   0.884pF
C_comp_pullup   0.4170pF   0.3920pF   0.4420pF
C_comp_pulldown   0.4170pF   0.3920pF   0.4420pF
| Note: C_comp changes when the ODT circuit is enabled.
[Model Spec]
| Input threshold voltage corners
Vinl   0.0900V   0.0825V   0.1025V
Vinh   0.2100V   0.2025V   0.2225V
| Measurement voltage corners
Vmeas   0.1500V   0.1425V   0.1625V
| Timing spec test load voltage corners
Vref   0.0000V   0.0000V   0.0000V
| Dynamic Overshoot Parameters from LPDDR4_0P6 Specification
D_overshoot_ampl_h   0.30   NA   NA
D_overshoot_ampl_l   0.30   NA   NA
D_overshoot_area_h   0.1n   NA   NA
D_overshoot_area_l   0.1n   NA   NA
[Voltage Range]   0.6000V   0.5700V   0.6500V
[Pullup Reference]   0.6000V   0.5700V   0.6500V
| Junction Temperature (Ambient temp is 35C typ 95C min -40C max)
[Temperature Range]   50.0   110.0   -40.0
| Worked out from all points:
|   slope of the pulldown table from 0 to 0.09 V, typ, clamps not added: 111 ohm
|   slope of the pullup table from 0 to 0.09 V, typ, clamps not added: 75.8 ohm
|   GND clamp passes 1 mA (typ) near -0.45 V on its own axis
|   rising waveform, R_fixture 50, V_fixture 0.0: 20-80 % time 37.9ps typ, 42.7ps min, 32.6ps max; typ from 0 V to 0.275 V
|   falling waveform, R_fixture 50, V_fixture 0.6: 20-80 % time 53.3ps typ, 63ps min, 44.7ps max; typ from 0.6 V to 0.43 V
|   rising waveform, R_fixture 50, V_fixture 0.6: 20-80 % time 43.3ps typ, 48.2ps min, 34.4ps max; typ from 0.43 V to 0.6 V
|   falling waveform, R_fixture 50, V_fixture 0.0: 20-80 % time 40.9ps typ, 46.7ps min, 37.3ps max; typ from 0.275 V to 0 V
[Pulldown]
|   Voltage   I(typ)   I(min)   I(max)
-600mV    -14.44mA   -12.66mA   -16.37mA
-486.6mV  -10.64mA   -8.932mA   -12.57mA
-405.6mV  -7.637mA   -6.304mA   -9.253mA
-349.8mV  -5.691mA   -4.747mA   -6.917mA
-297.6mV  -4.136mA   -3.577mA   -4.934mA
-252.6mV  -3.079mA   -2.788mA   -3.512mA
-205.8mV  -2.249mA   -2.132mA   -2.4mA
-155.4mV  -1.574mA   -1.541mA   -1.587mA
183mV     1.591mA    1.572mA    1.61mA
460.2mV   3.586mA    3.434mA    3.803mA
809.4mV   5.166mA    4.696mA    5.934mA
1.2V      6.059mA    5.442mA    7.269mA
[GND Clamp]
|   Voltage   I(typ)   I(min)   I(max)
-600mV    -5.439mA   -3.802mA   -7.294mA
-567.6mV  -4.11mA    -2.837mA   -5.5mA
-537mV    -3.03mA    -2.085mA   -3.984mA
-506.4mV  -2.148mA   -1.48mA    -2.701mA
-481.2mV  -1.569mA   -1.083mA   -1.86mA
-456mV    -1.112mA   -767.2uA   -1.23mA
-429mV    -741.3uA   -509.2uA   -756.2uA
-396.6mV  -429uA     -293.2uA   -396.8uA
-357mV    -196.9uA   -136uA     -159.5uA
-292.2mV  -42.83uA   -31.64uA   -26.87uA
-193.2mV  -2.376uA   -2.316uA   -807.5nA
1.2V      0A         0A         0A
[Pullup]
|   Voltage   I(typ)   I(min)   I(max)
-600mV    1.862mA    1.404mA    2.549mA
-294mV    1.393mA    1.038mA    1.907mA
-135.6mV  992.3uA    752.9uA    1.328mA
-74.4mV   659.4uA    520.6uA    855.2uA
-13.2mV   136.8uA    113uA      172.5uA
87.6mV    -1.152mA   -1.044mA   -1.34mA
215.4mV   -3.35mA    -3.272mA   -3.692mA
368.4mV   -6.391mA   -6.48mA    -6.825mA
633mV     -12.12mA   -12.47mA   -12.68mA
1.007V    -20.56mA   -21.02mA   -21.42mA
1.108V    -22.62mA   -23.09mA   -23.66mA
1.2V      -24.19mA   -24.67mA   -25.31mA
[POWER Clamp]
|   Voltage   I(typ)   I(min)   I(max)
-600mV    870.6nA    21.99uA    72.65nA
-594.6mV  739.5nA    19.12uA    70.4nA
-589.2mV  630.2nA    16.59uA    68.66nA
-578.4mV  462.2nA    12.46uA    65.31nA
-565.8mV  328.1nA    8.888uA    61.57nA
-549.6mV  219.3nA    5.719uA    57.05nA
-531.6mV  149.6nA    3.497uA    52.35nA
-511.8mV  106.1nA    2.042uA    47.56nA
-486.6mV  77.09nA    1.039uA    41.97nA
-457.8mV  60.45nA    497.1nA    36.26nA
-317.4mV  33.15nA    56.01nA    16.74nA
1.2V      0A         0A         0A
[Ramp]
|   typ   min   max
| 20% - 80%
dV/dt_r   164.86m/37.90p   156.10m/42.75p   186.31m/32.62p
dV/dt_f   101.96m/53.30p   94.87m/62.97p   114.04m/44.66p
| 25% - 75%
|dV/dt_r   137.39m/30.02p   130.09m/33.84p   155.26m/25.81p
|dV/dt_f   84.97m/42.16p   79.06m/49.72p   95.03m/35.25p
R_load = 50
[Rising Waveform]
R_fixture = 50
V_fixture = 0.0
|   Time   V(typ)   V(min)   V(max)
0s        181.8uV    168.9uV    86.06uV
60ps      1.071mV    -449.5uV   11.59mV
68ps      4.109mV    -213.4uV   47.25mV
80ps      18.47mV    2.728mV    133mV
96ps      93.15mV    11.54mV    223.8mV
113ps     177mV      59.66mV    272.8mV
130ps     226.4mV    135.7mV    294.6mV
157ps     259.9mV    214.1mV    306.7mV
191ps     271.6mV    248.3mV    309.9mV
389ps     275mV      260.3mV    310.6mV
[Falling Waveform]
R_fixture   = 50
V_fixture   = 0.6
V_fixture_min = 0.57
V_fixture_max = 0.65
|   Time   V(typ)   V(min)   V(max)
0s        600mV      570mV      650mV
71ps      598.7mV    571.1mV    641.8mV
78ps      595.9mV    570.2mV    627.2mV
94ps      585.4mV    564.9mV    569.9mV
114ps     538.9mV    558.3mV    518.2mV
134ps     494.7mV    531.8mV    490.1mV
157ps     463.9mV    487.8mV    473.9mV
188ps     443.7mV    448mV      464.8mV
227ps     434.4mV    425.1mV    461.2mV
389ps     430.1mV    411.9mV    459.9mV
[Rising Waveform]
R_fixture   = 50
V_fixture   = 0.6
V_fixture_min = 0.57
V_fixture_max = 0.65
|   Time   V(typ)   V(min)   V(max)
0s        430mV      411.7mV    459.9mV
58ps      429.6mV    410mV      469mV
66ps      435.7mV    409.5mV    487mV
79ps      462.4mV    415.9mV    541.4mV
96ps      513.3mV    449.8mV    597.4mV
113ps     551.2mV    493.4mV    625.2mV
132ps     575.9mV    526.2mV    639.2mV
160ps     591.6mV    552.8mV    646.7mV
198ps     597.9mV    565.4mV    649.3mV
389ps     600mV      570mV      650mV
[Falling Waveform]
R_fixture = 50
V_fixture = 0.0
|   Time   V(typ)   V(min)   V(max)
0s        275mV      260.4mV    310.6mV
63ps      278mV      262.6mV    302.8mV
71ps      275.1mV    264mV      272.5mV
82ps      256.1mV    262.8mV    189.9mV
100ps     165.8mV    235.9mV    95.92mV
117ps     90.94mV    168.5mV    51.77mV
140ps     41.37mV    83.53mV    22.71mV
169ps     15.81mV    32.65mV    8.112mV
205ps     4.961mV    10.5mV     2.311mV
389ps     269uV      294.3uV    123.6uV
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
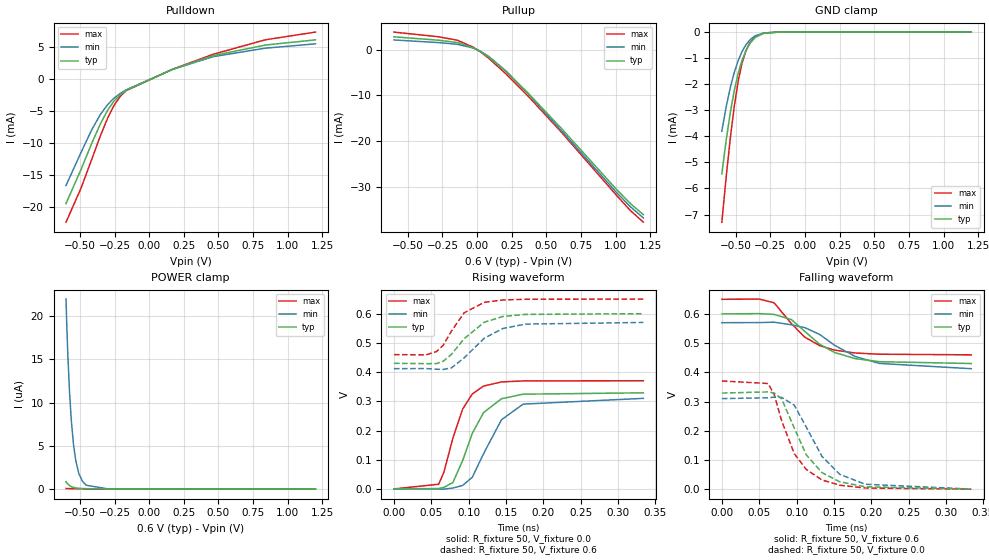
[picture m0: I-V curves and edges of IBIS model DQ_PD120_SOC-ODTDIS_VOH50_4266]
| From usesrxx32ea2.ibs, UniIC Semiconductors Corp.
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| DQ_PD120_SOC-ODTDIS_VOH50_4266
| (120 Ohm Pulldown, SOC ODT disabled setting, VOH=VDDQ*0.50 cal. point, 3200-4266Mbps)
[Model]   DQ_PD120_SOC-ODTDIS_VOH50_4266
Model_type   I/O
Vinl = 90.000mV
Vinh = 210.000mV
Vmeas = 150.000mV
Vref = 0.0mV
Cref = 0.0pF
|   typ   min   max
|C_comp   0.834pF   0.784pF   0.884pF
C_comp_pullup   0.4170pF   0.3920pF   0.4420pF
C_comp_pulldown   0.4170pF   0.3920pF   0.4420pF
| Note: C_comp changes when the ODT circuit is enabled.
[Model Spec]
| Input threshold voltage corners
Vinl   0.0900V   0.0825V   0.1025V
Vinh   0.2100V   0.2025V   0.2225V
| Measurement voltage corners
Vmeas   0.1500V   0.1425V   0.1625V
| Timing spec test load voltage corners
Vref   0.0000V   0.0000V   0.0000V
| Dynamic Overshoot Parameters from LPDDR4_0P6 Specification
D_overshoot_ampl_h   0.30   NA   NA
D_overshoot_ampl_l   0.30   NA   NA
D_overshoot_area_h   0.1n   NA   NA
D_overshoot_area_l   0.1n   NA   NA
[Voltage Range]   0.6000V   0.5700V   0.6500V
[Pullup Reference]   0.6000V   0.5700V   0.6500V
| Junction Temperature (Ambient temp is 35C typ 95C min -40C max)
[Temperature Range]   50.0   110.0   -40.0
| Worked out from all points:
|   slope of the pulldown table from 0 to 0.09 V, typ, clamps not added: 111 ohm
|   slope of the pullup table from 0 to 0.09 V, typ, clamps not added: 50.7 ohm
|   GND clamp passes 1 mA (typ) near -0.45 V on its own axis
|   rising waveform, R_fixture 50, V_fixture 0.0: 20-80 % time 32.9ps typ, 37.9ps min, 27.8ps max; typ from 0 V to 0.329 V
|   falling waveform, R_fixture 50, V_fixture 0.6: 20-80 % time 54ps typ, 64.2ps min, 44.8ps max; typ from 0.6 V to 0.43 V
|   rising waveform, R_fixture 50, V_fixture 0.6: 20-80 % time 39.5ps typ, 43.4ps min, 30.5ps max; typ from 0.43 V to 0.6 V
|   falling waveform, R_fixture 50, V_fixture 0.0: 20-80 % time 40.3ps typ, 45.5ps min, 36.9ps max; typ from 0.329 V to 0 V
[Pulldown]
|   Voltage   I(typ)   I(min)   I(max)
-600mV    -19.41mA   -16.6mA    -22.31mA
-492mV    -14.13mA   -11.48mA   -17.04mA
-414.6mV  -10.06mA   -7.943mA   -12.55mA
-353.4mV  -7.075mA   -5.599mA   -8.953mA
-299.4mV  -4.884mA   -4.009mA   -6.114mA
-254.4mV  -3.492mA   -3.028mA   -4.18mA
-209.4mV  -2.486mA   -2.284mA   -2.755mA
-166.2mV  -1.788mA   -1.713mA   -1.848mA
170.4mV   1.488mA    1.472mA    1.503mA
462mV     3.597mA    3.444mA    3.816mA
838.2mV   5.252mA    4.765mA    6.068mA
1.2V      6.059mA    5.442mA    7.269mA
[GND Clamp]
|   Voltage   I(typ)   I(min)   I(max)
-600mV    -5.439mA   -3.802mA   -7.294mA
-567.6mV  -4.11mA    -2.837mA   -5.5mA
-537mV    -3.03mA    -2.085mA   -3.985mA
-510mV    -2.24mA    -1.544mA   -2.838mA
-481.2mV  -1.571mA   -1.083mA   -1.86mA
-456mV    -1.113mA   -768.2uA   -1.229mA
-427.2mV  -722uA     -495.1uA   -731.4uA
-394.8mV  -415.6uA   -284.9uA   -381.9uA
-358.8mV  -204.4uA   -141.8uA   -167.2uA
-297.6mV  -49.16uA   -35.9uA    -31.61uA
-198.6mV  -2.806uA   -2.675uA   -997.9nA
1.2V      0A         0A         0A
[Pullup]
|   Voltage   I(typ)   I(min)   I(max)
-600mV    2.791mA    2.105mA    3.822mA
-281.4mV  2.053mA    1.53mA     2.81mA
-142.8mV  1.529mA    1.157mA    2.051mA
-27.6mV   414.3uA    339.3uA    524uA
24.6mV    -422.5uA   -362uA     -514.4uA
82.2mV    -1.597mA   -1.442mA   -1.864mA
206.4mV   -4.744mA   -4.615mA   -5.242mA
364.8mV   -9.41mA    -9.531mA   -10.05mA
615mV     -17.45mA   -17.94mA   -18.27mA
1.009V    -30.66mA   -31.34mA   -31.95mA
1.106V    -33.65mA   -34.34mA   -35.17mA
1.2V      -36.08mA   -36.8mA    -37.73mA
[POWER Clamp]
|   Voltage   I(typ)   I(min)   I(max)
-600mV    870.7nA    21.99uA    72.65nA
-594.6mV  739.5nA    19.12uA    70.4nA
-587.4mV  597.7nA    15.82uA    68.09nA
-574.8mV  417.9nA    11.32uA    64.22nA
-562.2mV  298.9nA    8.05uA     60.54nA
-546mV    202nA      5.178uA    56.09nA
-529.8mV  144nA      3.328uA    51.9nA
-508.2mV  100.5nA    1.855uA    46.73nA
-481.2mV  73.22nA    905.6nA    40.85nA
-454.2mV  59.03nA    455nA      35.59nA
-304.8mV  31.78nA    52.1nA     15.54nA
1.2V      0A         0A         0A
[Ramp]
|   typ   min   max
| 20% - 80%
dV/dt_r   197.29m/32.93p   185.91m/37.91p   222.24m/27.79p
dV/dt_f   101.90m/53.95p   94.53m/64.25p   114.03m/44.81p
| 25% - 75%
|dV/dt_r   164.41m/26.02p   154.93m/29.99p   185.20m/21.99p
|dV/dt_f   84.92m/42.60p   78.77m/50.53p   95.02m/35.38p
R_load = 50
[Rising Waveform]
R_fixture = 50
V_fixture = 0.0
|   Time   V(typ)   V(min)   V(max)
0s        278uV      262.3uV    129.6uV
60ps      1.411mV    -720.5uV   16.19mV
67ps      5.462mV    -617.4uV   57.94mV
79ps      22.29mV    3.271mV    174.3mV
92ps      97.06mV    11.97mV    273.4mV
105ps     190.5mV    40.23mV    325.3mV
120ps     261.3mV    120.6mV    352.2mV
144ps     308.8mV    236.8mV    366.3mV
173ps     324.4mV    290.4mV    369.8mV
334ps     329.1mV    310.1mV    370.5mV
[Falling Waveform]
R_fixture   = 50
V_fixture   = 0.6
V_fixture_min = 0.57
V_fixture_max = 0.65
|   Time   V(typ)   V(min)   V(max)
0s        600mV      570mV      650mV
50ps      601.1mV    570.4mV    650.9mV
70ps      598.3mV    571.7mV    638.1mV
93ps      580.8mV    562.9mV    567.3mV
111ps     540.4mV    553.2mV    520.7mV
131ps     496.1mV    529.7mV    491.5mV
151ps     467.9mV    492.6mV    476.2mV
179ps     446.9mV    453.9mV    466.2mV
211ps     436.6mV    430.6mV    462.1mV
334ps     430.2mV    412.5mV    460mV
[Rising Waveform]
R_fixture   = 50
V_fixture   = 0.6
V_fixture_min = 0.57
V_fixture_max = 0.65
|   Time   V(typ)   V(min)   V(max)
0s        430mV      411.7mV    459.9mV
43ps      429mV      412.2mV    459mV
57ps      429.1mV    409.8mV    470.3mV
66ps      437.1mV    409.1mV    492.1mV
77ps      460.8mV    414.4mV    540.1mV
94ps      514.3mV    448.5mV    602.9mV
121ps     570.7mV    516.2mV    638.8mV
146ps     590.4mV    549.3mV    646.9mV
176ps     597.5mV    564.3mV    649.3mV
334ps     600mV      570mV      650mV
[Falling Waveform]
R_fixture = 50
V_fixture = 0.0
|   Time   V(typ)   V(min)   V(max)
0s        329.2mV    310.2mV    370.6mV
62ps      333.1mV    312.9mV    361.8mV
70ps      329.6mV    315mV      325mV
80ps      309.5mV    314.3mV    235.1mV
97ps      209.5mV    287.6mV    121.6mV
113ps     118.1mV    212.9mV    67.77mV
134ps     56.82mV    112.8mV    31.82mV
158ps     25.41mV    50.89mV    13.59mV
192ps     8.368mV    17.01mV    4.179mV
334ps     399.4uV    539.4uV    187.4uV
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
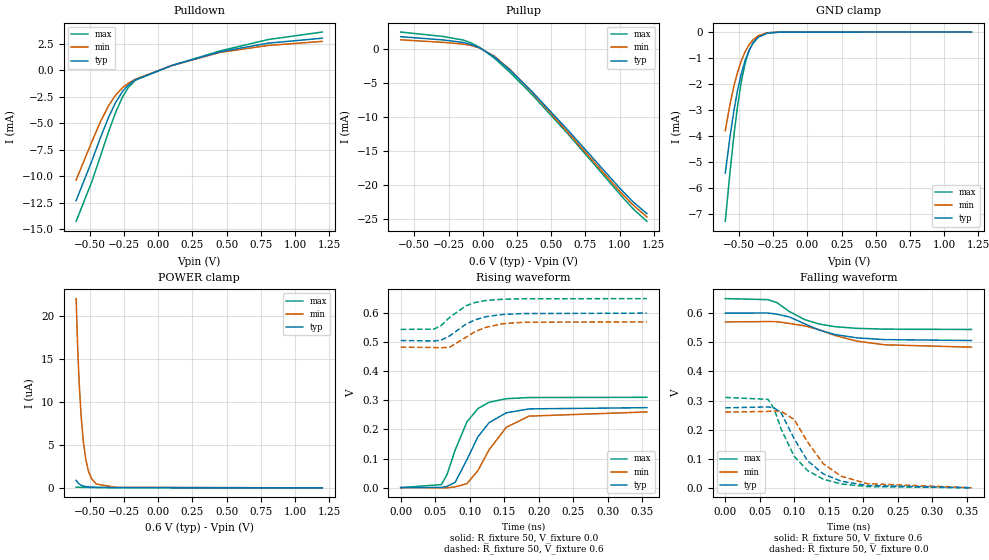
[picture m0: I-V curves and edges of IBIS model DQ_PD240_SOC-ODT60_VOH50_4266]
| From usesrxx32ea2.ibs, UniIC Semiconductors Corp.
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| DQ_PD240_SOC-ODT60_VOH50_4266
| (240 Ohm Pulldown, 60 Ohm System ODT Setting, VOH=VDDQ*0.50, 3200-4266Mbps)
[Model]   DQ_PD240_SOC-ODT60_VOH50_4266
Model_type   I/O
Vinl = 90.000mV
Vinh = 210.000mV
Vmeas = 150.000mV
Vref = 0.0mV
Cref = 0.0pF
Rref = 60.000Ohm
|   typ   min   max
|C_comp   0.834pF   0.784pF   0.884pF
C_comp_pullup   0.4170pF   0.3920pF   0.4420pF
C_comp_pulldown   0.4170pF   0.3920pF   0.4420pF
| Note: C_comp changes when the ODT circuit is enabled.
[Model Spec]
| Input threshold voltage corners
Vinl   0.0900V   0.0825V   0.1025V
Vinh   0.2100V   0.2025V   0.2225V
| Measurement voltage corners
Vmeas   0.1500V   0.1425V   0.1625V
| Timing spec test load voltage corners
Vref   0.0000V   0.0000V   0.0000V
| Dynamic Overshoot Parameters from LPDDR4_0P6 Specification
D_overshoot_ampl_h   0.30   NA   NA
D_overshoot_ampl_l   0.30   NA   NA
D_overshoot_area_h   0.1n   NA   NA
D_overshoot_area_l   0.1n   NA   NA
[Voltage Range]   0.6000V   0.5700V   0.6500V
[Pullup Reference]   0.6000V   0.5700V   0.6500V
| Junction Temperature (Ambient temp is 35C typ 95C min -40C max)
[Temperature Range]   50.0   110.0   -40.0
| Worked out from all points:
|   slope of the pulldown table from 0 to 0.09 V, typ, clamps not added: 228 ohm
|   slope of the pullup table from 0 to 0.09 V, typ, clamps not added: 75.8 ohm
|   GND clamp passes 1 mA (typ) near -0.45 V on its own axis
|   rising waveform, R_fixture 50, V_fixture 0.0: 20-80 % time 38.1ps typ, 43.1ps min, 32.7ps max; typ from 0 V to 0.275 V
|   falling waveform, R_fixture 50, V_fixture 0.6: 20-80 % time 63.1ps typ, 75.5ps min, 52ps max; typ from 0.6 V to 0.506 V
|   rising waveform, R_fixture 50, V_fixture 0.6: 20-80 % time 40.4ps typ, 40.1ps min, 35.4ps max; typ from 0.506 V to 0.6 V
|   falling waveform, R_fixture 50, V_fixture 0.0: 20-80 % time 46.7ps typ, 51.1ps min, 43.3ps max; typ from 0.275 V to 0 V
[Pulldown]
|   Voltage   I(typ)   I(min)   I(max)
-600mV    -12.31mA   -10.37mA   -14.26mA
-486.6mV  -8.618mA   -6.8mA     -10.58mA
-421.8mV  -6.364mA   -4.861mA   -8.101mA
-362.4mV  -4.445mA   -3.358mA   -5.797mA
-312mV    -3.072mA   -2.376mA   -4.021mA
-261.6mV  -2.033mA   -1.67mA    -2.558mA
-218.4mV  -1.41mA    -1.241mA   -1.642mA
-166.2mV  -913.1uA   -859.3uA   -954.1uA
98.4mV    424.3uA    423uA      422.4uA
454.8mV   1.732mA    1.671mA    1.816mA
805.8mV   2.54mA     2.323mA    2.882mA
1.2V      3.005mA    2.705mA    3.586mA
[GND Clamp]
|   Voltage   I(typ)   I(min)   I(max)
-600mV    -5.439mA   -3.802mA   -7.294mA
-565.8mV  -4.041mA   -2.789mA   -5.405mA
-537mV    -3.031mA   -2.085mA   -3.984mA
-511.8mV  -2.288mA   -1.577mA   -2.908mA
-483mV    -1.605mA   -1.109mA   -1.913mA
-454.2mV  -1.085mA   -749.3uA   -1.19mA
-427.2mV  -720.5uA   -497.3uA   -731.4uA
-396.6mV  -428.1uA   -294.9uA   -396.5uA
-357mV    -196.8uA   -136.9uA   -160uA
-292.2mV  -42.81uA   -31.73uA   -26.97uA
-198.6mV  -2.808uA   -2.703uA   -1.005uA
1.2V      0A         0A         0A
[Pullup]
|   Voltage   I(typ)   I(min)   I(max)
-600mV    1.862mA    1.404mA    2.549mA
-294mV    1.393mA    1.038mA    1.907mA
-144.6mV  1.027mA    776.7uA    1.38mA
-87mV     742.8uA    581.2uA    970.5uA
-24mV     243uA      198.6uA    307uA
84mV      -1.098mA   -992.4uA   -1.279mA
202.8mV   -3.116mA   -3.028mA   -3.446mA
359.4mV   -6.205mA   -6.283mA   -6.634mA
622.2mV   -11.88mA   -12.22mA   -12.43mA
1.009V    -20.59mA   -21.06mA   -21.46mA
1.101V    -22.48mA   -22.95mA   -23.51mA
1.2V      -24.19mA   -24.67mA   -25.31mA
[POWER Clamp]
|   Voltage   I(typ)   I(min)   I(max)
-600mV    870.7nA    21.99uA    72.65nA
-589.2mV  630.1nA    16.59uA    68.66nA
-582mV    511.4nA    13.71uA    66.41nA
-576.6mV  439.4nA    11.88uA    64.76nA
-564mV    312.8nA    8.457uA    61.06nA
-547.8mV  210.3nA    5.442uA    56.56nA
-529.8mV  144nA      3.328uA    51.91nA
-510mV    103.2nA    1.946uA    47.14nA
-488.4mV  78.56nA    1.09uA     42.36nA
-452.4mV  58.34nA    437.8nA    35.26nA
-303mV    31.59nA    51.74nA    15.37nA
1.2V      0A         0A         0A
[Ramp]
|   typ   min   max
| 20% - 80%
dV/dt_r   164.84m/38.14p   156.07m/43.08p   186.30m/32.66p
dV/dt_f   56.37m/63.11p   52.06m/75.55p   63.59m/52.03p
| 25% - 75%
|dV/dt_r   137.36m/30.17p   130.06m/34.07p   155.25m/25.86p
|dV/dt_f   46.97m/49.84p   43.38m/59.03p   52.99m/41.13p
R_load = 50
[Rising Waveform]
R_fixture = 50
V_fixture = 0.0
|   Time   V(typ)   V(min)   V(max)
0s        224.8uV    212.8uV    105.1uV
59ps      802.8uV    -672.4uV   10.43mV
67ps      4.352mV    -632.5uV   43.94mV
79ps      18.15mV    2.609mV    129.5mV
96ps      96.14mV    13.69mV    225.8mV
112ps     174.8mV    58.63mV    271.8mV
128ps     223.1mV    129.6mV    293.3mV
153ps     257.2mV    207.3mV    305.8mV
186ps     270.8mV    245.9mV    309.8mV
357ps     275mV      260.3mV    310.6mV
[Falling Waveform]
R_fixture   = 50
V_fixture   = 0.6
V_fixture_min = 0.57
V_fixture_max = 0.65
|   Time   V(typ)   V(min)   V(max)
0s        600mV      570mV      650mV
62ps      600.6mV    571.1mV    646.4mV
75ps      596.3mV    570.8mV    636mV
93ps      587.1mV    564.6mV    605.6mV
115ps     563.5mV    556.5mV    577.9mV
136ps     542.1mV    543.2mV    562.8mV
159ps     526.7mV    523.6mV    553.6mV
191ps     515.2mV    503.9mV    547.8mV
231ps     509.2mV    491.4mV    545.2mV
357ps     506.1mV    483.2mV    544mV
[Rising Waveform]
R_fixture   = 50
V_fixture   = 0.6
V_fixture_min = 0.57
V_fixture_max = 0.65
|   Time   V(typ)   V(min)   V(max)
0s        505.9mV    482.8mV    544mV
48ps      504.5mV    482mV      545mV
58ps      506.6mV    480.7mV    556.1mV
71ps      521.7mV    483mV      585.6mV
95ps      563mV      517.3mV    625.8mV
108ps     576.9mV    536.8mV    636.7mV
124ps     587.9mV    551.4mV    643.6mV
148ps     595.5mV    563.7mV    647.8mV
178ps     598.6mV    568.7mV    649.4mV
357ps     600mV      570mV      650mV
[Falling Waveform]
R_fixture = 50
V_fixture = 0.0
|   Time   V(typ)   V(min)   V(max)
0s        275mV      260.4mV    310.7mV
62ps      278mV      262.5mV    304mV
71ps      274.6mV    264.1mV    270.9mV
81ps      257.6mV    263.1mV    201.9mV
100ps     168.5mV    234.6mV    108.1mV
119ps     93.95mV    158.7mV    60.18mV
142ps     48.14mV    83.29mV    29.92mV
168ps     23.12mV    40.2mV     13.66mV
206ps     8.074mV    14.42mV    4.462mV
357ps     412.4uV    560.6uV    186.5uV
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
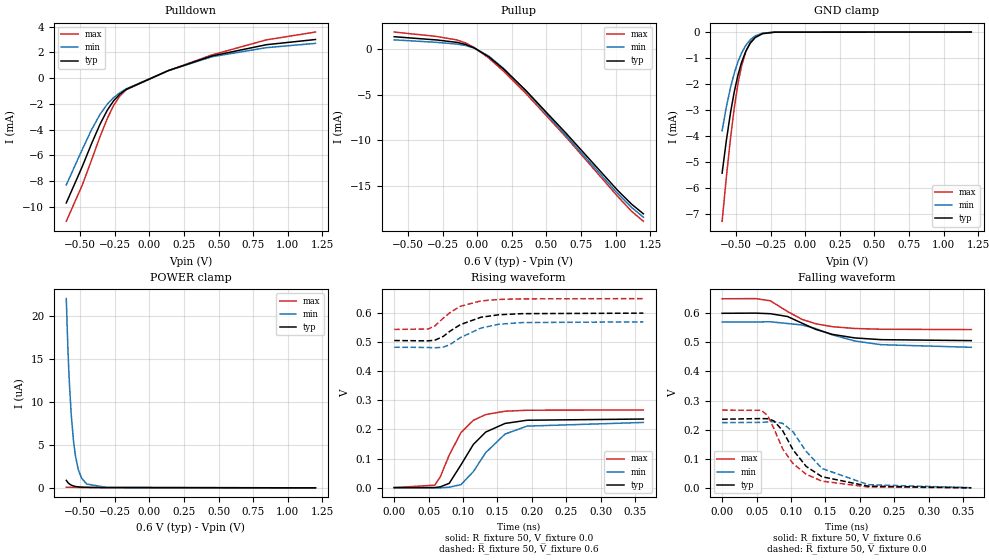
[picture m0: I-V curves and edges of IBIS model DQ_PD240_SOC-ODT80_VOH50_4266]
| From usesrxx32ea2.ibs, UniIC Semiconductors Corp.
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| DQ_PD240_SOC-ODT80_VOH50_4266
| (240 Ohm Pulldown, 80 Ohm System ODT Setting, VOH=VDDQ*0.50, 3200-4266Mbps)
[Model]   DQ_PD240_SOC-ODT80_VOH50_4266
Model_type   I/O
Vinl = 90.000mV
Vinh = 210.000mV
Vmeas = 150.000mV
Vref = 0.0mV
Cref = 0.0pF
Rref = 80.000Ohm
|   typ   min   max
|C_comp   0.834pF   0.784pF   0.884pF
C_comp_pullup   0.4170pF   0.3920pF   0.4420pF
C_comp_pulldown   0.4170pF   0.3920pF   0.4420pF
| Note: C_comp changes when the ODT circuit is enabled.
[Model Spec]
| Input threshold voltage corners
Vinl   0.0900V   0.0825V   0.1025V
Vinh   0.2100V   0.2025V   0.2225V
| Measurement voltage corners
Vmeas   0.1500V   0.1425V   0.1625V
| Timing spec test load voltage corners
Vref   0.0000V   0.0000V   0.0000V
| Dynamic Overshoot Parameters from LPDDR4_0P6 Specification
D_overshoot_ampl_h   0.30   NA   NA
D_overshoot_ampl_l   0.30   NA   NA
D_overshoot_area_h   0.1n   NA   NA
D_overshoot_area_l   0.1n   NA   NA
[Voltage Range]   0.6000V   0.5700V   0.6500V
[Pullup Reference]   0.6000V   0.5700V   0.6500V
| Junction Temperature (Ambient temp is 35C typ 95C min -40C max)
[Temperature Range]   50.0   110.0   -40.0
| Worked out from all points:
|   slope of the pulldown table from 0 to 0.09 V, typ, clamps not added: 229 ohm
|   slope of the pullup table from 0 to 0.09 V, typ, clamps not added: 101 ohm
|   GND clamp passes 1 mA (typ) near -0.45 V on its own axis
|   rising waveform, R_fixture 50, V_fixture 0.0: 20-80 % time 41.8ps typ, 45.8ps min, 35.7ps max; typ from 0 V to 0.236 V
|   falling waveform, R_fixture 50, V_fixture 0.6: 20-80 % time 62.1ps typ, 72.7ps min, 52.3ps max; typ from 0.6 V to 0.506 V
|   rising waveform, R_fixture 50, V_fixture 0.6: 20-80 % time 43.9ps typ, 45ps min, 37.9ps max; typ from 0.506 V to 0.6 V
|   falling waveform, R_fixture 50, V_fixture 0.0: 20-80 % time 47.6ps typ, 52.2ps min, 44ps max; typ from 0.236 V to 0 V
[Pulldown]
|   Voltage   I(typ)   I(min)   I(max)
-600mV    -9.71mA    -8.307mA   -11.14mA
-484.8mV  -6.888mA   -5.561mA   -8.334mA
-420mV    -5.167mA   -4.068mA   -6.448mA
-357mV    -3.603mA   -2.83mA    -4.575mA
-303mV    -2.481mA   -2.018mA   -3.125mA
-258mV    -1.765mA   -1.516mA   -2.131mA
-213mV    -1.249mA   -1.139mA   -1.395mA
-166.2mV  -870.3uA   -832.5uA   -896.9uA
138mV     589.3uA    586.1uA    588.7uA
453mV     1.726mA    1.666mA    1.809mA
845.4mV   2.601mA    2.371mA    2.976mA
1.2V      3.005mA    2.705mA    3.586mA
[GND Clamp]
|   Voltage   I(typ)   I(min)   I(max)
-600mV    -5.439mA   -3.802mA   -7.294mA
-569.4mV  -4.179mA   -2.886mA   -5.595mA
-538.8mV  -3.09mA    -2.125mA   -4.068mA
-511.8mV  -2.29mA    -1.577mA   -2.908mA
-484.8mV  -1.645mA   -1.135mA   -1.968mA
-459.6mV  -1.172mA   -810.9uA   -1.307mA
-429mV    -742uA     -511.9uA   -756.5uA
-396.6mV  -428.6uA   -295.3uA   -396.7uA
-360.6mV  -212.5uA   -147.5uA   -174.5uA
-308.4mV  -64.39uA   -46.5uA    -43.33uA
-220.2mV  -5.518uA   -4.979uA   -2.332uA
1.2V      0A         0A         0A
[Pullup]
|   Voltage   I(typ)   I(min)   I(max)
-600mV    1.396mA    1.053mA    1.912mA
-294mV    1.044mA    778.6uA    1.43mA
-144.6mV  770.5uA    582.6uA    1.034mA
-83.4mV   539.5uA    423.3uA    703.6uA
-22.2mV   169.4uA    139.2uA    213.7uA
82.2mV    -802.2uA   -724.2uA   -936.1uA
190.2mV   -2.161mA   -2.089mA   -2.4mA
348.6mV   -4.482mA   -4.531mA   -4.8mA
642mV     -9.234mA   -9.497mA   -9.653mA
1.016V    -15.54mA   -15.89mA   -16.2mA
1.115V    -17.03mA   -17.39mA   -17.81mA
1.2V      -18.09mA   -18.46mA   -18.91mA
[POWER Clamp]
|   Voltage   I(typ)   I(min)   I(max)
-600mV    870.6nA    21.99uA    72.65nA
-589.2mV  630.1nA    16.59uA    68.66nA
-583.8mV  538.5nA    14.38uA    66.96nA
-576.6mV  439.1nA    11.87uA    64.76nA
-564mV    312.7nA    8.456uA    61.06nA
-547.8mV  210.5nA    5.445uA    56.57nA
-533.4mV  154.8nA    3.672uA    52.81nA
-513.6mV  109.3nA    2.141uA    47.98nA
-490.2mV  80.1nA     1.143uA    42.74nA
-452.4mV  58.32nA    438.8nA    35.26nA
-308.4mV  32.16nA    53.15nA    15.87nA
1.2V      0A         0A         0A
[Ramp]
|   typ   min   max
| 20% - 80%
dV/dt_r   141.48m/41.75p   134.42m/45.81p   160.25m/35.71p
dV/dt_f   56.36m/62.13p   52.06m/72.73p   63.59m/52.27p
| 25% - 75%
|dV/dt_r   117.90m/33.07p   112.01m/36.20p   133.54m/28.26p
|dV/dt_f   46.97m/49.09p   43.38m/57.42p   52.99m/41.35p
R_load = 50
[Rising Waveform]
R_fixture = 50
V_fixture = 0.0
|   Time   V(typ)   V(min)   V(max)
0s        166.7uV    155.4uV    79.09uV
59ps      443.9uV    -468.9uV   8.699mV
67ps      2.815mV    -594.2uV   37.4mV
80ps      15.08mV    1.665mV    112.5mV
97ps      78.42mV    10.35mV    189.3mV
115ps     148.7mV    55.27mV    231.7mV
133ps     191.2mV    120.5mV    251.3mV
161ps     220.8mV    184.2mV    262.8mV
193ps     231.8mV    211.6mV    266.2mV
362ps     236mV      224.2mV    267.2mV
[Falling Waveform]
R_fixture   = 50
V_fixture   = 0.6
V_fixture_min = 0.57
V_fixture_max = 0.65
|   Time   V(typ)   V(min)   V(max)
0s        600mV      570mV      650mV
49ps      600.6mV    570.2mV    650.5mV
70ps      598.6mV    570.9mV    643mV
95ps      589mV      564.9mV    606.2mV
116ps     566.2mV    559.9mV    579.3mV
136ps     544.8mV    547.5mV    564.1mV
160ps     527.6mV    526.1mV    554mV
193ps     515.3mV    504.7mV    547.8mV
231ps     509.4mV    492.1mV    545.2mV
362ps     506.1mV    483.2mV    544mV
[Rising Waveform]
R_fixture   = 50
V_fixture   = 0.6
V_fixture_min = 0.57
V_fixture_max = 0.65
|   Time   V(typ)   V(min)   V(max)
0s        505.9mV    482.8mV    544mV
49ps      504.7mV    482mV      545.4mV
59ps      506.9mV    480.9mV    555.9mV
71ps      519.6mV    482.9mV    582.2mV
81ps      537.9mV    491.8mV    601.8mV
96ps      560.5mV    515.7mV    623.5mV
126ps     585.9mV    548.8mV    642.1mV
152ps     594.4mV    561.8mV    647.1mV
186ps     598.3mV    567.6mV    649.2mV
362ps     600mV      570mV      650mV
[Falling Waveform]
R_fixture = 50
V_fixture = 0.0
|   Time   V(typ)   V(min)   V(max)
0s        236mV      224.3mV    267.2mV
57ps      238.2mV    225mV      266.5mV
66ps      237.6mV    226.6mV    249mV
75ps      230.7mV    227.3mV    205.2mV
88ps      196.6mV    221.8mV    133.8mV
103ps     130.7mV    192.5mV    83.6mV
122ps     74.09mV    125.7mV    46.87mV
145ps     38.32mV    66.66mV    23.29mV
212ps     5.926mV    11.05mV    3.192mV
362ps     350.1uV    473.7uV    146.6uV
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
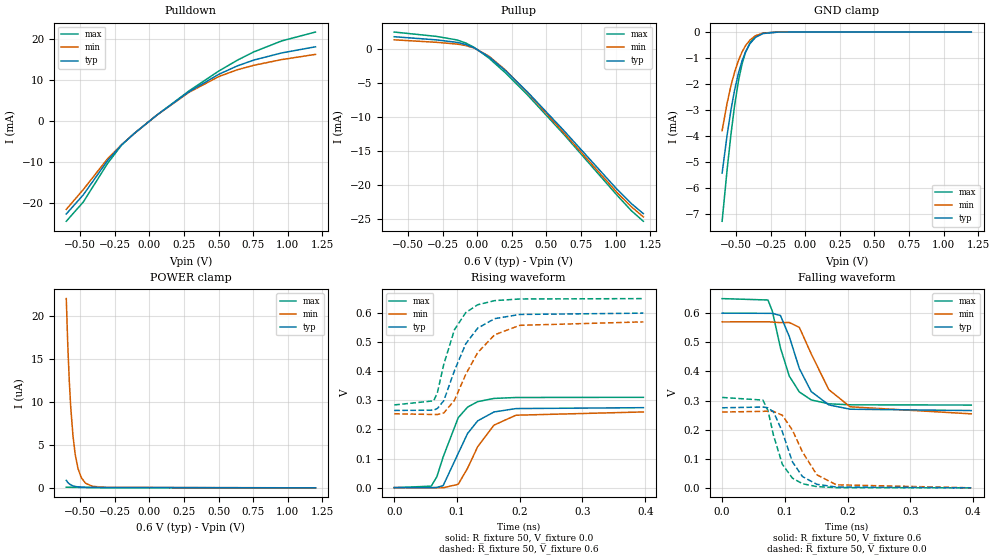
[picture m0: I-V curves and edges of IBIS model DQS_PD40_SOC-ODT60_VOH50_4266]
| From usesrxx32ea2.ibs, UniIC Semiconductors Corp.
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| DQS_PD40_SOC-ODT60_VOH50_4266
| (40 Ohm Pulldown, 60 Ohm System ODT Setting, VOH=VDDQ*0.50, 3200-4266Mbps)
[Model]   DQS_PD40_SOC-ODT60_VOH50_4266
Model_type   I/O
Vinl = 90.000mV
Vinh = 210.000mV
Vmeas = 150.000mV
Vref = 0.0mV
Cref = 0.0pF
Rref = 60.000Ohm
|   typ   min   max
|C_comp   0.849pF   0.799pF   0.899pF
C_comp_pullup   0.4245pF   0.3995pF   0.4495pF
C_comp_pulldown   0.4245pF   0.3995pF   0.4495pF
| Note: C_comp changes when the ODT circuit is enabled.
[Model Spec]
| Input threshold voltage corners
Vinl   0.0900V   0.0825V   0.1025V
Vinh   0.2100V   0.2025V   0.2225V
| Measurement voltage corners
Vmeas   0.1500V   0.1425V   0.1625V
| Timing spec test load voltage corners
Vref   0.0000V   0.0000V   0.0000V
| Dynamic Overshoot Parameters from LPDDR4_0P6 Specification
D_overshoot_ampl_h   0.30   NA   NA
D_overshoot_ampl_l   0.30   NA   NA
D_overshoot_area_h   0.1n   NA   NA
D_overshoot_area_l   0.1n   NA   NA
[Voltage Range]   0.6000V   0.5700V   0.6500V
[Pullup Reference]   0.6000V   0.5700V   0.6500V
| Junction Temperature (Ambient temp is 35C typ 95C min -40C max)
[Temperature Range]   50.0   110.0   -40.0
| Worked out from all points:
|   slope of the pulldown table from 0 to 0.09 V, typ, clamps not added: 37.5 ohm
|   slope of the pullup table from 0 to 0.09 V, typ, clamps not added: 75.8 ohm
|   GND clamp passes 1 mA (typ) near -0.45 V on its own axis
|   rising waveform, R_fixture 50, V_fixture 0.0: 20-80 % time 37.4ps typ, 41.7ps min, 32.4ps max; typ from 0 V to 0.275 V
|   falling waveform, R_fixture 50, V_fixture 0.6: 20-80 % time 36.3ps typ, 44.2ps min, 29.9ps max; typ from 0.6 V to 0.265 V
|   rising waveform, R_fixture 50, V_fixture 0.6: 20-80 % time 40.8ps typ, 49.7ps min, 32.2ps max; typ from 0.265 V to 0.6 V
|   falling waveform, R_fixture 50, V_fixture 0.0: 20-80 % time 29.5ps typ, 38.2ps min, 25.5ps max; typ from 0.275 V to 0 V
[Pulldown]
|   Voltage   I(typ)   I(min)   I(max)
-600mV    -22.72mA   -21.59mA   -24.5mA
-477.6mV  -18.06mA   -16.77mA   -19.81mA
-301.2mV  -9.642mA   -9.186mA   -10.34mA
-200.4mV  -5.816mA   -5.766mA   -5.873mA
-110.4mV  -3.087mA   -3.096mA   -3.045mA
57mV      1.529mA    1.524mA    1.528mA
285.6mV   7.146mA    6.998mA    7.342mA
501.6mV   11.43mA    10.88mA    12.23mA
634.8mV   13.47mA    12.53mA    14.86mA
755.4mV   14.92mA    13.64mA    16.92mA
957mV     16.66mA    15.03mA    19.6mA
1.2V      18.15mA    16.3mA     21.76mA
[GND Clamp]
|   Voltage   I(typ)   I(min)   I(max)
-600mV    -5.439mA   -3.802mA   -7.294mA
-564mV    -3.973mA   -2.741mA   -5.311mA
-535.2mV  -2.973mA   -2.045mA   -3.902mA
-510mV    -2.241mA   -1.544mA   -2.839mA
-481.2mV  -1.568mA   -1.083mA   -1.862mA
-456mV    -1.113mA   -768.3uA   -1.229mA
-430.8mV  -763.3uA   -524.3uA   -782.7uA
-398.4mV  -442.2uA   -303.6uA   -412.6uA
-358.8mV  -204.9uA   -141.4uA   -167.2uA
-303mV    -56.25uA   -40.9uA    -37.16uA
-196.8mV  -2.66uA    -2.565uA   -934.2nA
1.2V      0A         0A         0A
[Pullup]
|   Voltage   I(typ)   I(min)   I(max)
-600mV    1.862mA    1.404mA    2.549mA
-294mV    1.393mA    1.038mA    1.907mA
-144.6mV  1.027mA    777uA      1.379mA
-79.8mV   696uA      547.5uA    905.7uA
-20.4mV   208.4uA    171.5uA    262.8uA
84mV      -1.097mA   -991.9uA   -1.279mA
202.8mV   -3.116mA   -3.028mA   -3.446mA
364.8mV   -6.317mA   -6.401mA   -6.748mA
625.8mV   -11.96mA   -12.3mA    -12.52mA
1.009V    -20.59mA   -21.06mA   -21.46mA
1.114V    -22.72mA   -23.19mA   -23.77mA
1.2V      -24.19mA   -24.67mA   -25.31mA
[POWER Clamp]
|   Voltage   I(typ)   I(min)   I(max)
-600mV    870.6nA    21.99uA    72.65nA
-589.2mV  630.1nA    16.59uA    68.66nA
-578.4mV  462nA      12.46uA    65.31nA
-567.6mV  343.6nA    9.325uA    62.1nA
-551.4mV  229.2nA    6.004uA    57.54nA
-535.2mV  160.4nA    3.857uA    53.27nA
-515.4mV  112.1nA    2.249uA    48.4nA
-492mV    81.72nA    1.2uA      43.13nA
-461.4mV  61.98nA    543.4nA    36.94nA
-411mV    46.98nA    175.1nA    28.34nA
-312mV    32.55nA    54.21nA    16.21nA
1.2V      0A         0A         0A
[Ramp]
|   typ   min   max
| 20% - 80%
dV/dt_r   164.92m/37.40p   156.16m/41.69p   186.34m/32.43p
dV/dt_f   200.71m/36.28p   189.48m/44.24p   219.38m/29.95p
| 25% - 75%
|dV/dt_r   137.43m/29.63p   130.14m/33.07p   155.28m/25.60p
|dV/dt_f   167.26m/28.67p   157.90m/35.02p   182.82m/23.60p
R_load = 50
[Rising Waveform]
R_fixture = 50
V_fixture = 0.0
|   Time   V(typ)   V(min)   V(max)
0s        89.2uV     70.38uV    46.44uV
59ps      -4.018uV   -44.39uV   5.136mV
68ps      800.7uV    -618.3uV   37.74mV
78ps      7.001mV    -598.9uV   105.6mV
102ps     117.8mV    11.61mV    240.5mV
117ps     186.6mV    67.14mV    277.1mV
133ps     229.7mV    141mV      295.8mV
159ps     260.3mV    215mV      306.8mV
194ps     271.9mV    249.1mV    310mV
397ps     275mV      260.3mV    310.6mV
[Falling Waveform]
R_fixture   = 50
V_fixture   = 0.6
V_fixture_min = 0.57
V_fixture_max = 0.65
|   Time   V(typ)   V(min)   V(max)
0s        600mV      570mV      650mV
73ps      599.5mV    570.4mV    645.2mV
80ps      599.2mV    569.5mV    607.1mV
93ps      591.8mV    567.5mV    480.3mV
107ps     519.8mV    568mV      383.9mV
123ps     410mV      551.2mV    329.4mV
142ps     330.6mV    460.1mV    301.9mV
170ps     284.9mV    337.3mV    288.7mV
204ps     270.1mV    278.4mV    285.2mV
397ps     265.5mV    254.2mV    284.4mV
[Rising Waveform]
R_fixture   = 50
V_fixture   = 0.6
V_fixture_min = 0.57
V_fixture_max = 0.65
|   Time   V(typ)   V(min)   V(max)
0s        265.4mV    254.1mV    284.4mV
63ps      266.5mV    251.6mV    298.5mV
69ps      272.6mV    251.5mV    328.2mV
79ps      299mV      256.7mV    424.1mV
96ps      402.2mV    300.4mV    543mV
114ps     494.6mV    389.4mV    601.9mV
133ps     548.4mV    464.3mV    628.8mV
160ps     581.1mV    525.6mV    643.1mV
200ps     595.5mV    558.1mV    648.7mV
397ps     600mV      570mV      650mV
[Falling Waveform]
R_fixture = 50
V_fixture = 0.0
|   Time   V(typ)   V(min)   V(max)
0s        275mV      260.4mV    310.6mV
65ps      277.6mV    262.7mV    301.4mV
73ps      274.9mV    263.7mV    266.2mV
82ps      260.6mV    262.7mV    179.2mV
96ps      192.7mV    249.2mV    80.88mV
112ps     89.54mV    198.2mV    33.42mV
128ps     38.77mV    123.4mV    14.1mV
151ps     12.12mV    44.77mV    4.211mV
182ps     2.807mV    10.46mV    890uV
397ps     156.5uV    159.8uV    69.17uV
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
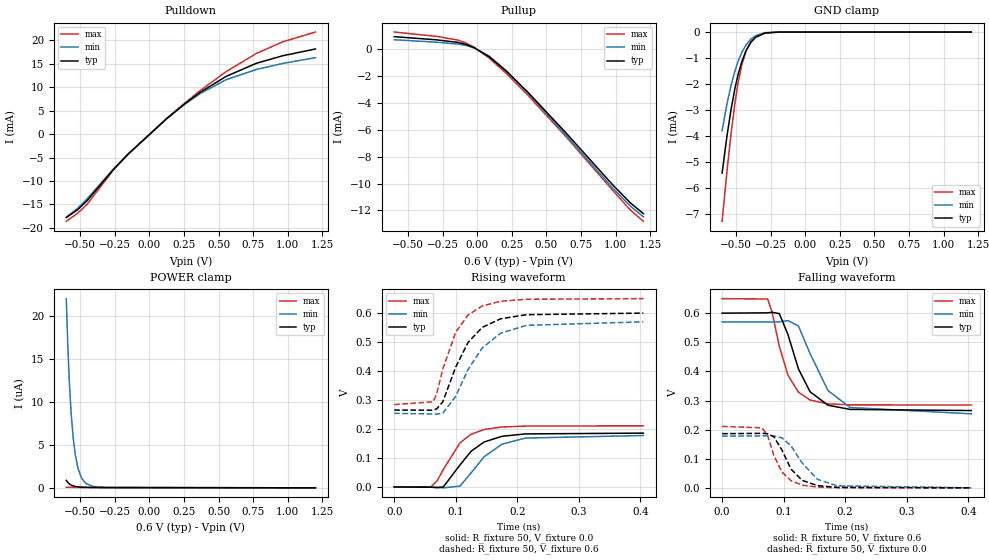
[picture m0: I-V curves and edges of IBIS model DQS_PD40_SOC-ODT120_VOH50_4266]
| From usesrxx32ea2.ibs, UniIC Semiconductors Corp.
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| DQS_PD40_SOC-ODT120_VOH50_4266
| (40 Ohm Pulldown, 120 Ohm System ODT Setting, VOH=VDDQ*0.50, 3200-4266Mbps)
[Model]   DQS_PD40_SOC-ODT120_VOH50_4266
Model_type   I/O
Vinl = 90.000mV
Vinh = 210.000mV
Vmeas = 150.000mV
Vref = 0.0mV
Cref = 0.0pF
Rref = 120.000Ohm
|   typ   min   max
|C_comp   0.849pF   0.799pF   0.899pF
C_comp_pullup   0.4245pF   0.3995pF   0.4495pF
C_comp_pulldown   0.4245pF   0.3995pF   0.4495pF
| Note: C_comp changes when the ODT circuit is enabled.
[Model Spec]
| Input threshold voltage corners
Vinl   0.0900V   0.0825V   0.1025V
Vinh   0.2100V   0.2025V   0.2225V
| Measurement voltage corners
Vmeas   0.1500V   0.1425V   0.1625V
| Timing spec test load voltage corners
Vref   0.0000V   0.0000V   0.0000V
| Dynamic Overshoot Parameters from LPDDR4_0P6 Specification
D_overshoot_ampl_h   0.30   NA   NA
D_overshoot_ampl_l   0.30   NA   NA
D_overshoot_area_h   0.1n   NA   NA
D_overshoot_area_l   0.1n   NA   NA
[Voltage Range]   0.6000V   0.5700V   0.6500V
[Pullup Reference]   0.6000V   0.5700V   0.6500V
| Junction Temperature (Ambient temp is 35C typ 95C min -40C max)
[Temperature Range]   50.0   110.0   -40.0
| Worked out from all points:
|   slope of the pulldown table from 0 to 0.09 V, typ, clamps not added: 37.6 ohm
|   slope of the pullup table from 0 to 0.09 V, typ, clamps not added: 150 ohm
|   GND clamp passes 1 mA (typ) near -0.45 V on its own axis
|   rising waveform, R_fixture 50, V_fixture 0.0: 20-80 % time 45.1ps typ, 49.1ps min, 40ps max; typ from 0 V to 0.186 V
|   falling waveform, R_fixture 50, V_fixture 0.6: 20-80 % time 36.1ps typ, 43.9ps min, 29.9ps max; typ from 0.6 V to 0.265 V
|   rising waveform, R_fixture 50, V_fixture 0.6: 20-80 % time 46.9ps typ, 55.1ps min, 39.5ps max; typ from 0.265 V to 0.6 V
|   falling waveform, R_fixture 50, V_fixture 0.0: 20-80 % time 29.7ps typ, 37.8ps min, 26.1ps max; typ from 0.186 V to 0 V
[Pulldown]
|   Voltage   I(typ)   I(min)   I(max)
-600mV    -17.79mA   -17.7mA    -18.59mA
-519mV    -16.14mA   -15.85mA   -16.9mA
-452.4mV  -14.29mA   -13.88mA   -15.07mA
-258mV    -7.483mA   -7.424mA   -7.602mA
-151.8mV  -4.238mA   -4.26mA    -4.187mA
127.2mV   3.35mA     3.324mA    3.371mA
255mV     6.45mA     6.335mA    6.597mA
366.6mV   8.888mA    8.626mA    9.257mA
553.8mV   12.29mA    11.59mA    13.3mA
773.4mV   15.1mA     13.78mA    17.2mA
964.2mV   16.71mA    15.07mA    19.68mA
1.2V      18.15mA    16.3mA     21.76mA
[GND Clamp]
|   Voltage   I(typ)   I(min)   I(max)
-600mV    -5.439mA   -3.802mA   -7.294mA
-565.8mV  -4.041mA   -2.789mA   -5.405mA
-535.2mV  -2.976mA   -2.046mA   -3.902mA
-506.4mV  -2.147mA   -1.48mA    -2.701mA
-483mV    -1.605mA   -1.109mA   -1.913mA
-456mV    -1.113mA   -767uA     -1.23mA
-427.2mV  -721.1uA   -494.7uA   -731.7uA
-393mV    -402.9uA   -274.4uA   -367.3uA
-357mV    -198.4uA   -136.3uA   -159.9uA
-290.4mV  -40.77uA   -30.14uA   -25.48uA
-193.2mV  -2.399uA   -2.31uA    -809.4nA
1.2V      0A         0A         0A
[Pullup]
|   Voltage   I(typ)   I(min)   I(max)
-600mV    931.5uA    702.4uA    1.276mA
-294mV    697.1uA    519.5uA    954.8uA
-139.2mV  504.5uA    382.1uA    676.5uA
-83.4mV   361.4uA    283uA      471.5uA
-20.4mV   104.9uA    85.95uA    132.3uA
85.8mV    -568.1uA   -513.7uA   -660.9uA
206.4mV   -1.609mA   -1.567mA   -1.777mA
368.4mV   -3.235mA   -3.285mA   -3.453mA
638.4mV   -6.203mA   -6.387mA   -6.483mA
980.4mV   -10.12mA   -10.36mA   -10.53mA
1.106V    -11.44mA   -11.68mA   -11.97mA
1.2V      -12.24mA   -12.48mA   -12.81mA
[POWER Clamp]
|   Voltage   I(typ)   I(min)   I(max)
-600mV    870.6nA    21.99uA    72.65nA
-589.2mV  630.2nA    16.59uA    68.66nA
-578.4mV  461.8nA    12.46uA    65.31nA
-565.8mV  327.8nA    8.881uA    61.58nA
-549.6mV  219.2nA    5.726uA    57.05nA
-535.2mV  161.6nA    3.866uA    53.27nA
-515.4mV  112.4nA    2.248uA    48.4nA
-488.4mV  78.68nA    1.092uA    42.35nA
-457.8mV  60.49nA    497.1nA    36.26nA
-405.6mV  45.93nA    157.8nA    27.53nA
-312mV    32.55nA    54.25nA    16.21nA
1.2V      0A         0A         0A
[Ramp]
|   typ   min   max
| 20% - 80%
dV/dt_r   111.55m/45.13p   106.53m/49.14p   126.62m/40.00p
dV/dt_f   200.72m/36.05p   189.47m/43.86p   219.38m/29.91p
| 25% - 75%
|dV/dt_r   92.96m/35.81p   88.77m/39.01p   105.52m/31.62p
|dV/dt_f   167.26m/28.51p   157.90m/34.74p   182.81m/23.56p
R_load = 50
[Rising Waveform]
R_fixture = 50
V_fixture = 0.0
|   Time   V(typ)   V(min)   V(max)
0s        28.17uV    9.737uV    19.66uV
60ps      -884.2uV   223.5uV    734.5uV
70ps      -2.476mV   -1.025mV   22.03mV
80ps      629.4uV    -2.963mV   61.05mV
107ps     76.13mV    3.091mV    152.5mV
125ps     123.3mV    48.69mV    181.8mV
146ps     155.1mV    104.2mV    198.2mV
175ps     174.8mV    147.5mV    207mV
213ps     183.1mV    168.8mV    210.1mV
405ps     185.9mV    177.6mV    211.1mV
[Falling Waveform]
R_fixture   = 50
V_fixture   = 0.6
V_fixture_min = 0.57
V_fixture_max = 0.65
|   Time   V(typ)   V(min)   V(max)
0s        600mV      570mV      650mV
74ps      601.1mV    569.7mV    648.6mV
81ps      603mV      569.4mV    605.5mV
93ps      598.4mV    570.4mV    486.1mV
107ps     526.7mV    574.5mV    387.1mV
124ps     408.8mV    556.2mV    328.7mV
143ps     330mV      461mV      301.5mV
172ps     283.9mV    334.4mV    288.5mV
208ps     269.4mV    276mV      285.1mV
405ps     265.5mV    254.2mV    284.4mV
[Rising Waveform]
R_fixture   = 50
V_fixture   = 0.6
V_fixture_min = 0.57
V_fixture_max = 0.65
|   Time   V(typ)   V(min)   V(max)
0s        265.4mV    254.1mV    284.4mV
63ps      265mV      251.9mV    293.8mV
69ps      269.6mV    251.4mV    320.8mV
79ps      293.9mV    254.6mV    406.6mV
100ps     413.9mV    312.8mV    534.3mV
120ps     498.7mV    405.3mV    593.1mV
143ps     550.6mV    479.4mV    624.5mV
173ps     580.4mV    530.7mV    640.9mV
215ps     594.5mV    557.7mV    647.8mV
405ps     600mV      569.9mV    650mV
[Falling Waveform]
R_fixture = 50
V_fixture = 0.0
|   Time   V(typ)   V(min)   V(max)
0s        186mV      177.7mV    211.1mV
65ps      187.2mV    178.5mV    206.2mV
74ps      186mV      179mV      179.4mV
84ps      175.6mV    178.4mV    112.1mV
97ps      130.8mV    172mV      54.92mV
112ps     64.43mV    144.3mV    24.55mV
130ps     25.94mV    85.71mV    9.47mV
155ps     7.611mV    29.2mV     2.604mV
187ps     1.743mV    6.973mV    549.5uV
405ps     97.13uV    105.7uV    40.15uV
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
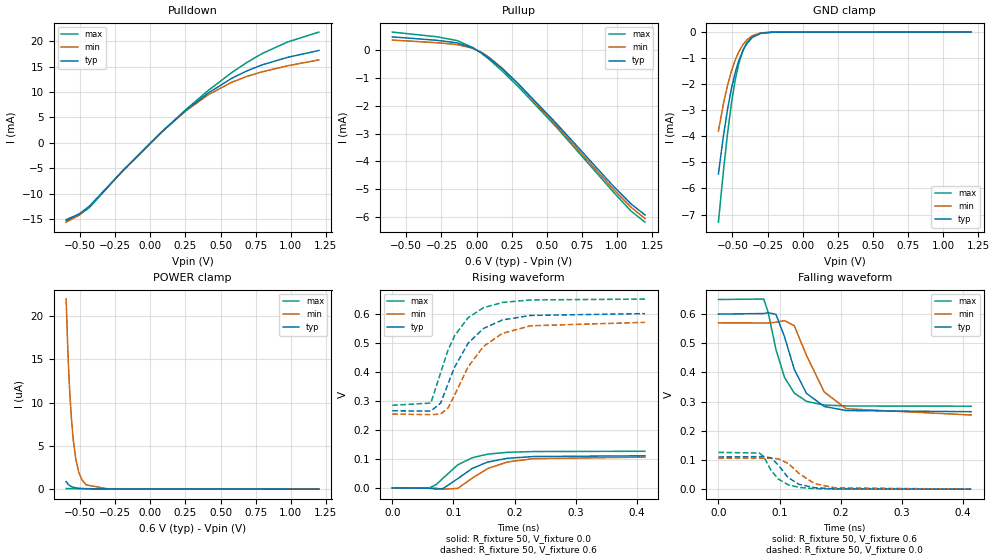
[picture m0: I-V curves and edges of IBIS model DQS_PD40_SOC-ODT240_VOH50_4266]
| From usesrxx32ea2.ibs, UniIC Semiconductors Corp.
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| DQS_PD40_SOC-ODT240_VOH50_4266
| (40 Ohm Pulldown, 240 Ohm System ODT Setting, VOH=VDDQ*0.50, 3200-4266Mbps)
[Model]   DQS_PD40_SOC-ODT240_VOH50_4266
Model_type   I/O
Vinl = 90.000mV
Vinh = 210.000mV
Vmeas = 150.000mV
Vref = 0.0mV
Cref = 0.0pF
Rref = 240.000Ohm
|   typ   min   max
|C_comp   0.849pF   0.799pF   0.899pF
C_comp_pullup   0.4245pF   0.3995pF   0.4495pF
C_comp_pulldown   0.4245pF   0.3995pF   0.4495pF
| Note: C_comp changes when the ODT circuit is enabled.
[Model Spec]
| Input threshold voltage corners
Vinl   0.0900V   0.0825V   0.1025V
Vinh   0.2100V   0.2025V   0.2225V
| Measurement voltage corners
Vmeas   0.1500V   0.1425V   0.1625V
| Timing spec test load voltage corners
Vref   0.0000V   0.0000V   0.0000V
| Dynamic Overshoot Parameters from LPDDR4_0P6 Specification
D_overshoot_ampl_h   0.30   NA   NA
D_overshoot_ampl_l   0.30   NA   NA
D_overshoot_area_h   0.1n   NA   NA
D_overshoot_area_l   0.1n   NA   NA
[Voltage Range]   0.6000V   0.5700V   0.6500V
[Pullup Reference]   0.6000V   0.5700V   0.6500V
| Junction Temperature (Ambient temp is 35C typ 95C min -40C max)
[Temperature Range]   50.0   110.0   -40.0
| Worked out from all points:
|   slope of the pulldown table from 0 to 0.09 V, typ, clamps not added: 37.6 ohm
|   slope of the pullup table from 0 to 0.09 V, typ, clamps not added: 306 ohm
|   GND clamp passes 1 mA (typ) near -0.45 V on its own axis
|   rising waveform, R_fixture 50, V_fixture 0.0: 20-80 % time 53.6ps typ, 56.5ps min, 47.5ps max; typ from 0 V to 0.11 V
|   falling waveform, R_fixture 50, V_fixture 0.6: 20-80 % time 35.9ps typ, 43.7ps min, 29.8ps max; typ from 0.6 V to 0.265 V
|   rising waveform, R_fixture 50, V_fixture 0.6: 20-80 % time 52.4ps typ, 58.4ps min, 45.5ps max; typ from 0.265 V to 0.6 V
|   falling waveform, R_fixture 50, V_fixture 0.0: 20-80 % time 30ps typ, 38.3ps min, 27.1ps max; typ from 0.111 V to 0 V
[Pulldown]
|   Voltage   I(typ)   I(min)   I(max)
-600mV    -15.09mA   -15.58mA   -15.36mA
-508.2mV  -13.97mA   -14.19mA   -14.19mA
-432.6mV  -12.4mA    -12.42mA   -12.67mA
-195mV    -5.437mA   -5.479mA   -5.377mA
76.8mV    2.052mA    2.042mA    2.053mA
253.2mV   6.409mA    6.295mA    6.553mA
413.4mV   9.824mA    9.476mA    10.32mA
579mV     12.68mA    11.9mA     13.8mA
687mV     14.14mA    13.05mA    15.79mA
795mV     15.32mA    13.95mA    17.53mA
976.8mV   16.8mA     15.14mA    19.81mA
1.2V      18.15mA    16.3mA     21.76mA
[GND Clamp]
|   Voltage   I(typ)   I(min)   I(max)
-600mV    -5.439mA   -3.802mA   -7.294mA
-564mV    -3.973mA   -2.741mA   -5.311mA
-533.4mV  -2.916mA   -2.007mA   -3.82mA
-506.4mV  -2.146mA   -1.48mA    -2.701mA
-481.2mV  -1.569mA   -1.084mA   -1.86mA
-456mV    -1.114mA   -767.5uA   -1.229mA
-423.6mV  -683.7uA   -469.2uA   -683.2uA
-394.8mV  -417.5uA   -285.5uA   -381.8uA
-357mV    -198.8uA   -136.8uA   -159.8uA
-297.6mV  -49.14uA   -36.19uA   -31.71uA
-213mV    -4.416uA   -4.021uA   -1.769uA
1.2V      0A         0A         0A
[Pullup]
|   Voltage   I(typ)   I(min)   I(max)
-600mV    465uA      350.7uA    636.6uA
-286.8mV  344.5uA    256.9uA    471.4uA
-139.2mV  251.1uA    190.4uA    336.1uA
-25.8mV   64.64uA    53.04uA    81.68uA
31.8mV    -92.33uA   -79.64uA   -111.6uA
84mV      -271.8uA   -245.8uA   -316.8uA
175.8mV   -648.8uA   -622.2uA   -724.3uA
300mV     -1.233mA   -1.234mA   -1.333mA
568.2mV   -2.635mA   -2.705mA   -2.766mA
980.4mV   -4.92mA    -5.03mA    -5.127mA
1.101V    -5.527mA   -5.644mA   -5.782mA
1.2V      -5.919mA   -6.049mA   -6.179mA
[POWER Clamp]
|   Voltage   I(typ)   I(min)   I(max)
-600mV    870.6nA    21.99uA    72.65nA
-589.2mV  630.2nA    16.59uA    68.66nA
-583.8mV  538.6nA    14.38uA    66.96nA
-576.6mV  439.8nA    11.87uA    64.76nA
-564mV    313nA      8.452uA    61.06nA
-549.6mV  219.2nA    5.729uA    57.05nA
-531.6mV  149nA      3.499uA    52.36nA
-510mV    103.1nA    1.944uA    47.15nA
-488.4mV  78.75nA    1.089uA    42.36nA
-457.8mV  60.52nA    497.6nA    36.26nA
-306.6mV  31.97nA    52.62nA    15.71nA
1.2V      0A         0A         0A
[Ramp]
|   typ   min   max
| 20% - 80%
dV/dt_r   66.30m/53.57p   63.59m/56.47p   75.64m/47.46p
dV/dt_f   200.71m/35.95p   189.48m/43.68p   219.37m/29.80p
| 25% - 75%
|dV/dt_r   55.25m/42.50p   52.99m/44.86p   63.03m/37.59p
|dV/dt_f   167.26m/28.45p   157.90m/34.60p   182.81m/23.51p
R_load = 50
[Rising Waveform]
R_fixture = 50
V_fixture = 0.0
|   Time   V(typ)   V(min)   V(max)
0s        -4.387uV   -22.4uV    5.391uV
59ps      -898uV     412.1uV    -1.245mV
72ps      -4.124mV   -1.349mV   11.62mV
83ps      -2.31mV    -4.328mV   33.63mV
107ps     31.89mV    -1.743mV   79.38mV
131ps     67.52mV    34.18mV    104.1mV
156ps     88.95mV    66.72mV    116.2mV
188ps     101.9mV    89.08mV    122.5mV
231ps     108.1mV    100.8mV    125.2mV
413ps     110.5mV    106mV      126.1mV
[Falling Waveform]
R_fixture   = 50
V_fixture   = 0.6
V_fixture_min = 0.57
V_fixture_max = 0.65
|   Time   V(typ)   V(min)   V(max)
0s        600mV      570mV      650mV
74ps      601.9mV    569.4mV    651.5mV
81ps      604.9mV    569.4mV    608.7mV
94ps      599.2mV    572mV      479.2mV
108ps     522.5mV    577.7mV    383.3mV
124ps     410.7mV    560mV      329.2mV
144ps     328.1mV    458.3mV    300.9mV
173ps     283.4mV    332.8mV    288.3mV
209ps     269.3mV    275.5mV    285.1mV
413ps     265.5mV    254.2mV    284.4mV
[Rising Waveform]
R_fixture   = 50
V_fixture   = 0.6
V_fixture_min = 0.57
V_fixture_max = 0.65
|   Time   V(typ)   V(min)   V(max)
0s        265.4mV    254.1mV    284.4mV
63ps      264.6mV    252.1mV    292mV
79ps      291.8mV    254.2mV    396.4mV
91ps      357.3mV    274.7mV    473.7mV
102ps     416.3mV    320.2mV    524.2mV
124ps     498.3mV    416.8mV    586mV
149ps     548.8mV    486.9mV    620.2mV
180ps     578.1mV    532mV      638.3mV
226ps     593.7mV    558mV      647mV
413ps     599.9mV    569.9mV    650mV
[Falling Waveform]
R_fixture = 50
V_fixture = 0.0
|   Time   V(typ)   V(min)   V(max)
0s        110.5mV    106.1mV    126.1mV
67ps      111.5mV    106.6mV    123.8mV
74ps      112mV      106.5mV    111.6mV
86ps      107.3mV    106.2mV    64.71mV
98ps      82.11mV    104mV      34.52mV
114ps     39.49mV    88.3mV     15.08mV
132ps     16.48mV    53.42mV    5.983mV
157ps     5.064mV    19.09mV    1.677mV
191ps     1.101mV    4.499mV    333.9uV
413ps     60.11uV    67.11uV    22.51uV
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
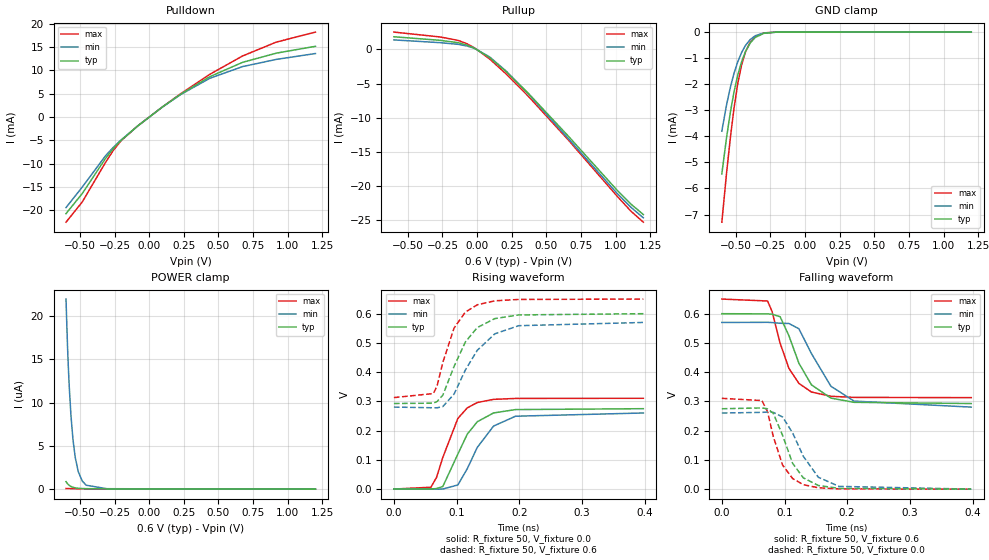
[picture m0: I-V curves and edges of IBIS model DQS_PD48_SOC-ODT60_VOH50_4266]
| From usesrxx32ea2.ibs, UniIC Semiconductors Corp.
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| DQS_PD48_SOC-ODT60_VOH50_4266
| (48 Ohm Pulldown, 60 Ohm System ODT Setting, VOH=VDDQ*0.50, 3200-4266Mbps)
[Model]   DQS_PD48_SOC-ODT60_VOH50_4266
Model_type   I/O
Vinl = 90.000mV
Vinh = 210.000mV
Vmeas = 150.000mV
Vref = 0.0mV
Cref = 0.0pF
Rref = 60.000Ohm
|   typ   min   max
|C_comp   0.849pF   0.799pF   0.899pF
C_comp_pullup   0.4245pF   0.3995pF   0.4495pF
C_comp_pulldown   0.4245pF   0.3995pF   0.4495pF
| Note: C_comp changes when the ODT circuit is enabled.
[Model Spec]
| Input threshold voltage corners
Vinl   0.0900V   0.0825V   0.1025V
Vinh   0.2100V   0.2025V   0.2225V
| Measurement voltage corners
Vmeas   0.1500V   0.1425V   0.1625V
| Timing spec test load voltage corners
Vref   0.0000V   0.0000V   0.0000V
| Dynamic Overshoot Parameters from LPDDR4_0P6 Specification
D_overshoot_ampl_h   0.30   NA   NA
D_overshoot_ampl_l   0.30   NA   NA
D_overshoot_area_h   0.1n   NA   NA
D_overshoot_area_l   0.1n   NA   NA
[Voltage Range]   0.6000V   0.5700V   0.6500V
[Pullup Reference]   0.6000V   0.5700V   0.6500V
| Junction Temperature (Ambient temp is 35C typ 95C min -40C max)
[Temperature Range]   50.0   110.0   -40.0
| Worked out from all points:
|   slope of the pulldown table from 0 to 0.09 V, typ, clamps not added: 44.5 ohm
|   slope of the pullup table from 0 to 0.09 V, typ, clamps not added: 75.7 ohm
|   GND clamp passes 1 mA (typ) near -0.45 V on its own axis
|   rising waveform, R_fixture 50, V_fixture 0.0: 20-80 % time 37.5ps typ, 41.9ps min, 32.5ps max; typ from 0 V to 0.275 V
|   falling waveform, R_fixture 50, V_fixture 0.6: 20-80 % time 39.3ps typ, 47.7ps min, 32.5ps max; typ from 0.6 V to 0.293 V
|   rising waveform, R_fixture 50, V_fixture 0.6: 20-80 % time 41.2ps typ, 49.8ps min, 32.4ps max; typ from 0.293 V to 0.6 V
|   falling waveform, R_fixture 50, V_fixture 0.0: 20-80 % time 31.2ps typ, 39.3ps min, 27.4ps max; typ from 0.275 V to 0 V
[Pulldown]
|   Voltage   I(typ)   I(min)   I(max)
-600mV    -20.75mA   -19.45mA   -22.58mA
-483mV    -16.44mA   -15.05mA   -18.25mA
-315.6mV  -8.942mA   -8.362mA   -9.795mA
-261.6mV  -6.879mA   -6.613mA   -7.301mA
-204mV    -5.055mA   -4.983mA   -5.146mA
-81.6mV   -1.916mA   -1.92mA    -1.89mA
93mV      2.082mA    2.069mA    2.09mA
229.8mV   4.933mA    4.851mA    5.037mA
438.6mV   8.657mA    8.306mA    9.163mA
674.4mV   11.72mA    10.81mA    13.09mA
917.4mV   13.69mA    12.35mA    16.06mA
1.2V      15.16mA    13.61mA    18.21mA
[GND Clamp]
|   Voltage   I(typ)   I(min)   I(max)
-600mV    -5.439mA   -3.802mA   -7.294mA
-565.8mV  -4.041mA   -2.789mA   -5.405mA
-537mV    -3.031mA   -2.086mA   -3.985mA
-511.8mV  -2.289mA   -1.576mA   -2.908mA
-484.8mV  -1.643mA   -1.135mA   -1.968mA
-457.8mV  -1.142mA   -788.3uA   -1.267mA
-429mV    -741.2uA   -510.3uA   -756.4uA
-394.8mV  -415.7uA   -284uA     -381.8uA
-358.8mV  -205.8uA   -141uA     -167.7uA
-297.6mV  -49.35uA   -35.98uA   -31.57uA
-209.4mV  -3.967uA   -3.626uA   -1.526uA
1.2V      0A         0A         0A
[Pullup]
|   Voltage   I(typ)   I(min)   I(max)
-600mV    1.862mA    1.404mA    2.549mA
-265.2mV  1.339mA    997.4uA    1.831mA
-135.6mV  992.1uA    752.7uA    1.328mA
-72.6mV   646.6uA    511.5uA    837.9uA
-16.8mV   173.2uA    142.5uA    217.7uA
91.2mV    -1.207mA   -1.097mA   -1.401mA
210mV     -3.249mA   -3.167mA   -3.586mA
370.2mV   -6.429mA   -6.52mA    -6.863mA
654.6mV   -12.61mA   -12.97mA   -13.17mA
1.009V    -20.59mA   -21.06mA   -21.46mA
1.11V     -22.65mA   -23.12mA   -23.69mA
1.2V      -24.19mA   -24.67mA   -25.31mA
[POWER Clamp]
|   Voltage   I(typ)   I(min)   I(max)
-600mV    870.6nA    21.99uA    72.65nA
-589.2mV  630.1nA    16.59uA    68.66nA
-583.8mV  538.8nA    14.38uA    66.96nA
-576.6mV  439nA      11.87uA    64.76nA
-564mV    312.6nA    8.46uA     61.06nA
-549.6mV  219.3nA    5.727uA    57.05nA
-533.4mV  154.8nA    3.675uA    52.81nA
-511.8mV  106.2nA    2.039uA    47.56nA
-483mV    74.4nA     949.8nA    41.22nA
-454.2mV  59.01nA    456.1nA    35.6nA
-304.8mV  31.79nA    52.13nA    15.54nA
1.2V      0A         0A         0A
[Ramp]
|   typ   min   max
| 20% - 80%
dV/dt_r   164.91m/37.52p   156.15m/41.92p   186.33m/32.51p
dV/dt_f   184.34m/39.31p   173.64m/47.71p   202.23m/32.54p
| 25% - 75%
|dV/dt_r   137.42m/29.72p   130.12m/33.24p   155.28m/25.67p
|dV/dt_f   153.62m/31.10p   144.70m/37.78p   168.52m/25.65p
R_load = 50
[Rising Waveform]
R_fixture = 50
V_fixture = 0.0
|   Time   V(typ)   V(min)   V(max)
0s        106.8uV    89.97uV    53.81uV
59ps      366.8uV    -55.66uV   6.293mV
68ps      1.71mV     -338.8uV   39.84mV
78ps      8.563mV    219.4uV    108.2mV
102ps     119.6mV    14.01mV    241.5mV
117ps     187.6mV    69.52mV    277.7mV
133ps     230.3mV    142.5mV    296.1mV
159ps     260.5mV    215.5mV    306.9mV
194ps     271.9mV    249.2mV    310mV
398ps     275mV      260.3mV    310.6mV
[Falling Waveform]
R_fixture   = 50
V_fixture   = 0.6
V_fixture_min = 0.57
V_fixture_max = 0.65
|   Time   V(typ)   V(min)   V(max)
0s        600mV      570mV      650mV
73ps      599.3mV    570.5mV    643.4mV
80ps      598.4mV    569.6mV    608.4mV
93ps      589.6mV    567.3mV    499.2mV
107ps     524.8mV    566.5mV    413.3mV
123ps     430.5mV    548.4mV    361.5mV
143ps     356.7mV    463.6mV    332.2mV
174ps     311.4mV    352mV      317.6mV
211ps     297mV      301.1mV    313.8mV
398ps     292.8mV    280.6mV    313mV
[Rising Waveform]
R_fixture   = 50
V_fixture   = 0.6
V_fixture_min = 0.57
V_fixture_max = 0.65
|   Time   V(typ)   V(min)   V(max)
0s        292.7mV    280.5mV    312.9mV
63ps      293.9mV    278.1mV    326.8mV
69ps      299.7mV    278.1mV    353.6mV
78ps      321.1mV    282.1mV    433mV
96ps      419.6mV    325mV      551mV
114ps     503.3mV    407.4mV    605.4mV
133ps     552.5mV    474.7mV    630.4mV
161ps     583.2mV    531.1mV    644mV
199ps     595.7mV    558.9mV    648.7mV
398ps     600mV      570mV      650mV
[Falling Waveform]
R_fixture = 50
V_fixture = 0.0
|   Time   V(typ)   V(min)   V(max)
0s        275mV      260.4mV    310.6mV
64ps      277.8mV    262.6mV    303mV
73ps      274.6mV    263.8mV    264.6mV
82ps      259.8mV    262.8mV    180.6mV
97ps      183.9mV    246.8mV    82.18mV
113ps     88.06mV    192.1mV    36.36mV
130ps     38.77mV    112.4mV    15.49mV
154ps     12.64mV    40.76mV    4.779mV
187ps     2.946mV    9.622mV    1.027mV
398ps     171.6uV    179uV      74.83uV
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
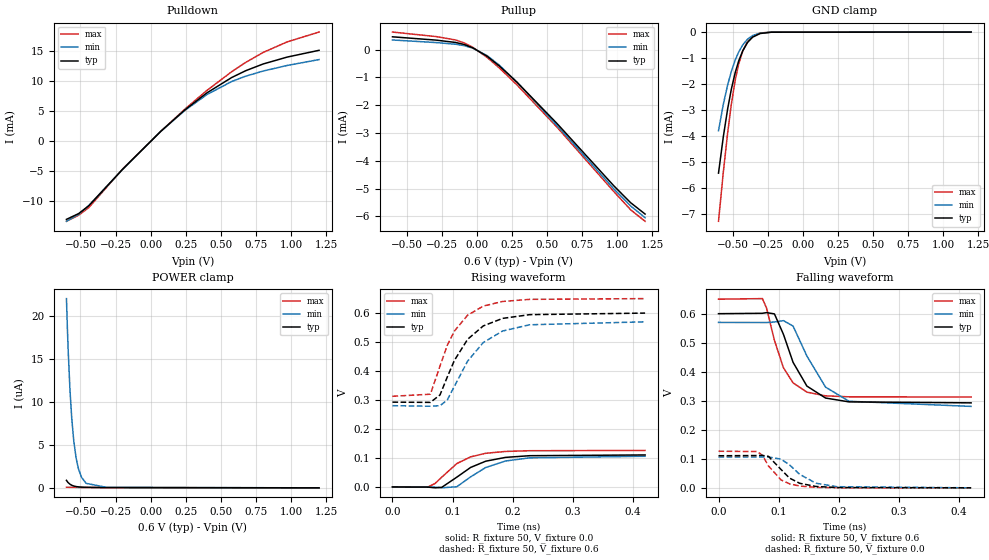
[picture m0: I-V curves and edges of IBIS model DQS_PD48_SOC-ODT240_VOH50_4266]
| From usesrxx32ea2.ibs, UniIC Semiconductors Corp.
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| DQS_PD48_SOC-ODT240_VOH50_4266
| (48 Ohm Pulldown, 240 Ohm System ODT Setting, VOH=VDDQ*0.50, 3200-4266Mbps)
[Model]   DQS_PD48_SOC-ODT240_VOH50_4266
Model_type   I/O
Vinl = 90.000mV
Vinh = 210.000mV
Vmeas = 150.000mV
Vref = 0.0mV
Cref = 0.0pF
Rref = 240.000Ohm
|   typ   min   max
|C_comp   0.849pF   0.799pF   0.899pF
C_comp_pullup   0.4245pF   0.3995pF   0.4495pF
C_comp_pulldown   0.4245pF   0.3995pF   0.4495pF
| Note: C_comp changes when the ODT circuit is enabled.
[Model Spec]
| Input threshold voltage corners
Vinl   0.0900V   0.0825V   0.1025V
Vinh   0.2100V   0.2025V   0.2225V
| Measurement voltage corners
Vmeas   0.1500V   0.1425V   0.1625V
| Timing spec test load voltage corners
Vref   0.0000V   0.0000V   0.0000V
| Dynamic Overshoot Parameters from LPDDR4_0P6 Specification
D_overshoot_ampl_h   0.30   NA   NA
D_overshoot_ampl_l   0.30   NA   NA
D_overshoot_area_h   0.1n   NA   NA
D_overshoot_area_l   0.1n   NA   NA
[Voltage Range]   0.6000V   0.5700V   0.6500V
[Pullup Reference]   0.6000V   0.5700V   0.6500V
| Junction Temperature (Ambient temp is 35C typ 95C min -40C max)
[Temperature Range]   50.0   110.0   -40.0
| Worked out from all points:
|   slope of the pulldown table from 0 to 0.09 V, typ, clamps not added: 44.6 ohm
|   slope of the pullup table from 0 to 0.09 V, typ, clamps not added: 306 ohm
|   GND clamp passes 1 mA (typ) near -0.45 V on its own axis
|   rising waveform, R_fixture 50, V_fixture 0.0: 20-80 % time 53.8ps typ, 56.7ps min, 47.7ps max; typ from 0 V to 0.11 V
|   falling waveform, R_fixture 50, V_fixture 0.6: 20-80 % time 38.9ps typ, 47.1ps min, 32.4ps max; typ from 0.6 V to 0.293 V
|   rising waveform, R_fixture 50, V_fixture 0.6: 20-80 % time 52.4ps typ, 58.4ps min, 45.5ps max; typ from 0.293 V to 0.6 V
|   falling waveform, R_fixture 50, V_fixture 0.0: 20-80 % time 32.1ps typ, 40.1ps min, 29.1ps max; typ from 0.111 V to 0 V
[Pulldown]
|   Voltage   I(typ)   I(min)   I(max)
-600mV    -13.08mA   -13.4mA    -13.4mA
-513.6mV  -12.12mA   -12.24mA   -12.39mA
-441.6mV  -10.83mA   -10.79mA   -11.14mA
-198.6mV  -4.681mA   -4.71mA    -4.642mA
71.4mV    1.608mA    1.601mA    1.611mA
242.4mV   5.181mA    5.09mA     5.299mA
399mV     8.019mA    7.739mA    8.422mA
577.2mV   10.61mA    9.947mA    11.58mA
676.2mV   11.74mA    10.83mA    13.12mA
802.2mV   12.88mA    11.7mA     14.81mA
973.2mV   14.03mA    12.63mA    16.57mA
1.2V      15.16mA    13.61mA    18.21mA
[GND Clamp]
|   Voltage   I(typ)   I(min)   I(max)
-600mV    -5.439mA   -3.802mA   -7.294mA
-565.8mV  -4.041mA   -2.788mA   -5.405mA
-535.2mV  -2.973mA   -2.046mA   -3.902mA
-508.2mV  -2.194mA   -1.512mA   -2.769mA
-481.2mV  -1.568mA   -1.083mA   -1.86mA
-456mV    -1.113mA   -767.9uA   -1.228mA
-427.2mV  -721uA     -494.7uA   -731.2uA
-393mV    -400.8uA   -274.6uA   -367.1uA
-357mV    -198.1uA   -136.2uA   -160uA
-303mV    -56.25uA   -40.78uA   -37.06uA
-223.8mV  -6.213uA   -5.402uA   -2.67uA
1.2V      0A         0A         0A
[Pullup]
|   Voltage   I(typ)   I(min)   I(max)
-600mV    465uA      350.7uA    636.6uA
-288.6mV  345.4uA    257.5uA    472.6uA
-150mV    261.3uA    197.3uA    351.1uA
-90.6mV   190.6uA    148.9uA    249.2uA
-29.4mV   73.1uA     59.72uA    92.43uA
75mV      -238.9uA   -214.1uA   -279.8uA
161.4mV   -585.7uA   -557.5uA   -657.4uA
287.4mV   -1.172mA   -1.169mA   -1.269mA
570mV     -2.645mA   -2.715mA   -2.776mA
978.6mV   -4.91mA    -5.02mA    -5.117mA
1.097V    -5.51mA    -5.627mA   -5.764mA
1.2V      -5.919mA   -6.049mA   -6.179mA
[POWER Clamp]
|   Voltage   I(typ)   I(min)   I(max)
-600mV    870.6nA    21.97uA    72.65nA
-592.8mV  700.9nA    18.24uA    69.82nA
-587.4mV  597.8nA    15.83uA    68.09nA
-574.8mV  419.1nA    11.31uA    64.22nA
-562.2mV  298.6nA    8.057uA    60.54nA
-547.8mV  210.3nA    5.441uA    56.57nA
-531.6mV  149.4nA    3.497uA    52.35nA
-515.4mV  112nA      2.249uA    48.4nA
-492mV    81.73nA    1.2uA      43.12nA
-459.6mV  61.2nA     519.7nA    36.6nA
-313.8mV  32.76nA    54.77nA    16.39nA
1.2V      0A         0A         0A
[Ramp]
|   typ   min   max
| 20% - 80%
dV/dt_r   66.30m/53.80p   63.58m/56.73p   75.64m/47.70p
dV/dt_f   184.34m/38.92p   173.66m/47.06p   202.22m/32.42p
| 25% - 75%
|dV/dt_r   55.25m/42.76p   52.99m/45.05p   63.03m/37.79p
|dV/dt_f   153.62m/30.80p   144.71m/37.31p   168.52m/25.56p
R_load = 50
[Rising Waveform]
R_fixture = 50
V_fixture = 0.0
|   Time   V(typ)   V(min)   V(max)
0s        4.445uV    -11.38uV   8.754uV
59ps      -517.2uV   411.3uV    -176.4uV
71ps      -2.916mV   -707.4uV   12.41mV
82ps      -1.166mV   -2.981mV   33.96mV
107ps     33.88mV    836.4uV    80.81mV
130ps     67.51mV    34.93mV    104mV
155ps     88.94mV    67.1mV     116.2mV
188ps     102.1mV    89.66mV    122.6mV
228ps     107.9mV    100.5mV    125.1mV
420ps     110.5mV    106mV      126.1mV
[Falling Waveform]
R_fixture   = 50
V_fixture   = 0.6
V_fixture_min = 0.57
V_fixture_max = 0.65
|   Time   V(typ)   V(min)   V(max)
0s        600mV      570mV      650mV
73ps      601.4mV    569.6mV    652mV
80ps      603.7mV    569.5mV    618.7mV
93ps      599.3mV    571.4mV    507.8mV
108ps     528.7mV    576.1mV    413.6mV
124ps     432.3mV    557.4mV    361.5mV
147ps     350.5mV    453.9mV    329.7mV
178ps     309.4mV    346.9mV    317mV
217ps     296.2mV    298.3mV    313.6mV
420ps     292.8mV    280.6mV    313mV
[Rising Waveform]
R_fixture   = 50
V_fixture   = 0.6
V_fixture_min = 0.57
V_fixture_max = 0.65
|   Time   V(typ)   V(min)   V(max)
0s        292.7mV    280.5mV    312.9mV
63ps      291.9mV    278.6mV    320.1mV
79ps      317.6mV    280.5mV    417.2mV
91ps      378.8mV    300mV      488.2mV
103ps     437mV      347.7mV    538mV
125ps     509.8mV    434.6mV    592.9mV
151ps     555.8mV    498.5mV    624.2mV
183ps     581.7mV    538.1mV    640.1mV
228ps     594.6mV    559.7mV    647.4mV
420ps     600mV      569.9mV    650mV
[Falling Waveform]
R_fixture = 50
V_fixture = 0.0
|   Time   V(typ)   V(min)   V(max)
0s        110.5mV    106.1mV    126.1mV
64ps      111.3mV    106.6mV    125.1mV
73ps      111.7mV    106.7mV    112.6mV
83ps      108.6mV    106.5mV    75.61mV
104ps     63.15mV    98.88mV    27.29mV
118ps     33.69mV    79.19mV    13.95mV
135ps     15.65mV    46.46mV    6.121mV
162ps     4.728mV    15.94mV    1.68mV
197ps     1.067mV    3.923mV    351.6uV
420ps     65.83uV    73.88uV    24.78uV
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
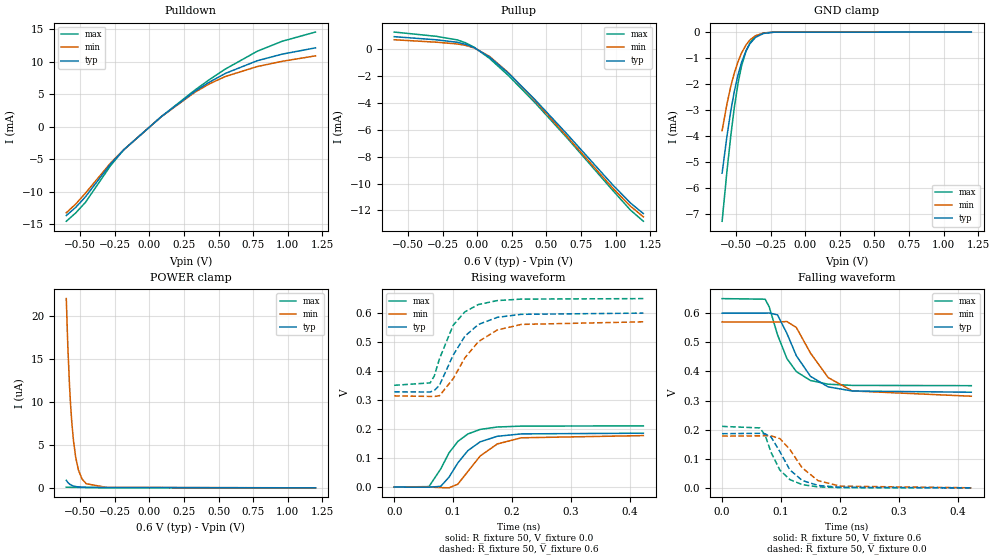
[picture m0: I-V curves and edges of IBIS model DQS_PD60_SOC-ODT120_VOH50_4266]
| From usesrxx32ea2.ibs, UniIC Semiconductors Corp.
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| DQS_PD60_SOC-ODT120_VOH50_4266
| (60 Ohm Pulldown, 120 Ohm System ODT Setting, VOH=VDDQ*0.50, 3200-4266Mbps)
[Model]   DQS_PD60_SOC-ODT120_VOH50_4266
Model_type   I/O
Vinl = 90.000mV
Vinh = 210.000mV
Vmeas = 150.000mV
Vref = 0.0mV
Cref = 0.0pF
Rref = 120.000Ohm
|   typ   min   max
|C_comp   0.849pF   0.799pF   0.899pF
C_comp_pullup   0.4245pF   0.3995pF   0.4495pF
C_comp_pulldown   0.4245pF   0.3995pF   0.4495pF
| Note: C_comp changes when the ODT circuit is enabled.
[Model Spec]
| Input threshold voltage corners
Vinl   0.0900V   0.0825V   0.1025V
Vinh   0.2100V   0.2025V   0.2225V
| Measurement voltage corners
Vmeas   0.1500V   0.1425V   0.1625V
| Timing spec test load voltage corners
Vref   0.0000V   0.0000V   0.0000V
| Dynamic Overshoot Parameters from LPDDR4_0P6 Specification
D_overshoot_ampl_h   0.30   NA   NA
D_overshoot_ampl_l   0.30   NA   NA
D_overshoot_area_h   0.1n   NA   NA
D_overshoot_area_l   0.1n   NA   NA
[Voltage Range]   0.6000V   0.5700V   0.6500V
[Pullup Reference]   0.6000V   0.5700V   0.6500V
| Junction Temperature (Ambient temp is 35C typ 95C min -40C max)
[Temperature Range]   50.0   110.0   -40.0
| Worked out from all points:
|   slope of the pulldown table from 0 to 0.09 V, typ, clamps not added: 55.8 ohm
|   slope of the pullup table from 0 to 0.09 V, typ, clamps not added: 150 ohm
|   GND clamp passes 1 mA (typ) near -0.45 V on its own axis
|   rising waveform, R_fixture 50, V_fixture 0.0: 20-80 % time 45.4ps typ, 49.6ps min, 40.1ps max; typ from 0 V to 0.186 V
|   falling waveform, R_fixture 50, V_fixture 0.6: 20-80 % time 43.1ps typ, 52ps min, 36ps max; typ from 0.6 V to 0.328 V
|   rising waveform, R_fixture 50, V_fixture 0.6: 20-80 % time 47.8ps typ, 55.6ps min, 39.8ps max; typ from 0.328 V to 0.6 V
|   falling waveform, R_fixture 50, V_fixture 0.0: 20-80 % time 34.6ps typ, 42ps min, 30.9ps max; typ from 0.186 V to 0 V
[Pulldown]
|   Voltage   I(typ)   I(min)   I(max)
-600mV    -13.65mA   -13.23mA   -14.53mA
-531.6mV  -12.39mA   -11.88mA   -13.24mA
-461.4mV  -10.77mA   -10.2mA    -11.62mA
-279.6mV  -5.711mA   -5.561mA   -5.96mA
-186mV    -3.566mA   -3.563mA   -3.56mA
85.8mV    1.538mA    1.53mA     1.541mA
330.6mV   5.463mA    5.322mA    5.659mA
433.2mV   6.848mA    6.581mA    7.23mA
548.4mV   8.183mA    7.714mA    8.857mA
778.8mV   10.14mA    9.242mA    11.59mA
958.8mV   11.15mA    10.05mA    13.13mA
1.2V      12.12mA    10.89mA    14.55mA
[GND Clamp]
|   Voltage   I(typ)   I(min)   I(max)
-600mV    -5.439mA   -3.802mA   -7.294mA
-565.8mV  -4.041mA   -2.789mA   -5.405mA
-537mV    -3.03mA    -2.085mA   -3.985mA
-511.8mV  -2.29mA    -1.577mA   -2.908mA
-484.8mV  -1.644mA   -1.135mA   -1.968mA
-459.6mV  -1.172mA   -808uA     -1.307mA
-427.2mV  -721.5uA   -494.8uA   -731.6uA
-398.4mV  -442.9uA   -302.9uA   -412.3uA
-358.8mV  -205.1uA   -141uA     -167.1uA
-301.2mV  -53.79uA   -39.44uA   -35.08uA
-225.6mV  -6.486uA   -5.689uA   -2.834uA
1.2V      0A         0A         0A
[Pullup]
|   Voltage   I(typ)   I(min)   I(max)
-600mV    931.5uA    702.4uA    1.276mA
-294mV    697.1uA    519.5uA    954.8uA
-144.6mV  514.8uA    389uA      691.9uA
-85.2mV   366.9uA    287.4uA    479.7uA
-20.4mV   104.9uA    86.14uA    132.4uA
89.4mV    -595uA     -540.3uA   -691.7uA
226.2mV   -1.797mA   -1.764mA   -1.973mA
415.2mV   -3.733mA   -3.81mA    -3.961mA
652.8mV   -6.367mA   -6.555mA   -6.65mA
980.4mV   -10.12mA   -10.36mA   -10.53mA
1.106V    -11.44mA   -11.68mA   -11.97mA
1.2V      -12.24mA   -12.48mA   -12.81mA
[POWER Clamp]
|   Voltage   I(typ)   I(min)   I(max)
-600mV    870.6nA    21.99uA    72.65nA
-589.2mV  630.1nA    16.59uA    68.66nA
-576.6mV  439.2nA    11.88uA    64.76nA
-569.4mV  360.6nA    9.78uA     62.62nA
-560.4mV  285.1nA    7.666uA    60.04nA
-547.8mV  210.4nA    5.448uA    56.57nA
-531.6mV  149.3nA    3.499uA    52.36nA
-511.8mV  106.2nA    2.044uA    47.55nA
-486.6mV  77.24nA    1.039uA    41.98nA
-456mV    59.7nA     476.6nA    35.93nA
-312mV    32.55nA    54.23nA    16.21nA
1.2V      0A         0A         0A
[Ramp]
|   typ   min   max
| 20% - 80%
dV/dt_r   111.54m/45.42p   106.52m/49.63p   126.61m/40.15p
dV/dt_f   162.95m/43.15p   153.18m/52.02p   179.39m/36.00p
| 25% - 75%
|dV/dt_r   92.95m/36.03p   88.77m/39.36p   105.51m/31.75p
|dV/dt_f   135.79m/34.15p   127.65m/41.24p   149.49m/28.44p
R_load = 50
[Rising Waveform]
R_fixture = 50
V_fixture = 0.0
|   Time   V(typ)   V(min)   V(max)
0s        53.56uV    38.84uV    29.95uV
59ps      -387.8uV   91.46uV    1.703mV
79ps      2.636mV    -1.781mV   62.73mV
93ps      34.06mV    -2.56mV    117.8mV
108ps     83.3mV     9.964mV    157.4mV
125ps     125.7mV    53.73mV    183.1mV
146ps     156.2mV    107.3mV    198.9mV
175ps     175.2mV    148.8mV    207.2mV
216ps     183.5mV    170mV      210.3mV
423ps     185.9mV    177.6mV    211.1mV
[Falling Waveform]
R_fixture   = 50
V_fixture   = 0.6
V_fixture_min = 0.57
V_fixture_max = 0.65
|   Time   V(typ)   V(min)   V(max)
0s        600mV      570mV      650mV
73ps      600.1mV    570mV      648mV
80ps      600.7mV    569.7mV    621.3mV
94ps      594.1mV    569.7mV    526mV
110ps     530.4mV    571.2mV    444mV
126ps     453.8mV    550.8mV    399.3mV
150ps     383mV      463mV      368.7mV
180ps     346.8mV    378.7mV    356mV
221ps     332.6mV    332.9mV    351.9mV
423ps     328.4mV    314.7mV    351mV
[Rising Waveform]
R_fixture   = 50
V_fixture   = 0.6
V_fixture_min = 0.57
V_fixture_max = 0.65
|   Time   V(typ)   V(min)   V(max)
0s        328.4mV    314.6mV    351mV
61ps      328mV      312.7mV    359.4mV
68ps      332.9mV    312.2mV    383mV
77ps      351.8mV    315.3mV    443.4mV
100ps     454.8mV    373.5mV    557.7mV
120ps     520.4mV    445.9mV    604.5mV
143ps     561mV      501.7mV    629.6mV
175ps     585.4mV    541.8mV    643.2mV
216ps     595.8mV    561mV      648.3mV
423ps     600mV      570mV      650mV
[Falling Waveform]
R_fixture = 50
V_fixture = 0.0
|   Time   V(typ)   V(min)   V(max)
0s        186mV      177.7mV    211.1mV
64ps      187.3mV    178.6mV    205.9mV
73ps      185.6mV    179.2mV    180.9mV
83ps      174.9mV    178.6mV    122.2mV
98ps      124.6mV    169.3mV    61.25mV
115ps     61.8mV     131.8mV    28.4mV
136ps     25.34mV    68.57mV    11.05mV
163ps     8.234mV    24.51mV    3.326mV
201ps     1.825mV    5.747mV    652uV
423ps     120.9uV    129.1uV    49.72uV
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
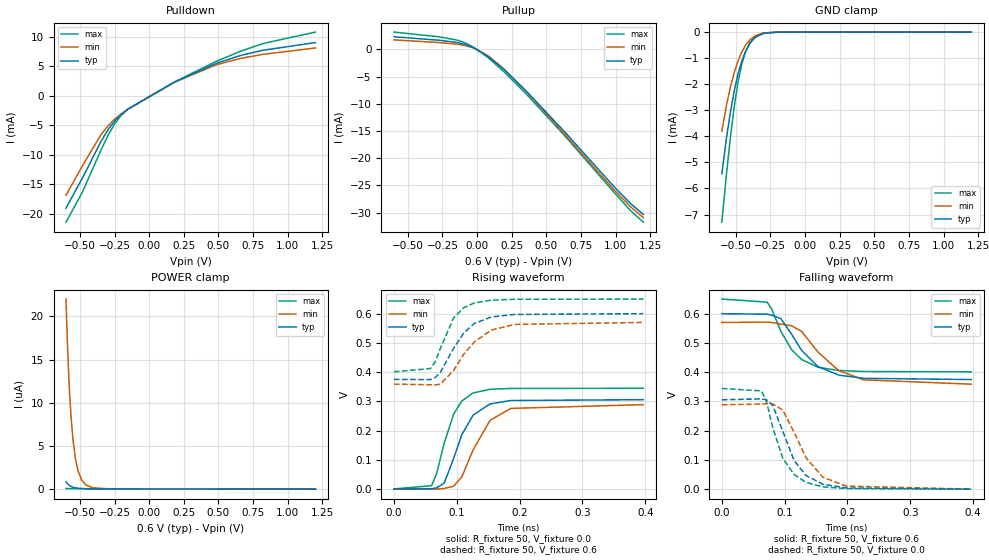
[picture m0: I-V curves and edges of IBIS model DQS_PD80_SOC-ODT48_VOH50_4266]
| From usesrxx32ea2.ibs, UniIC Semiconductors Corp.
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| DQS_PD80_SOC-ODT48_VOH50_4266
| (80 Ohm Pulldown, 48 Ohm System ODT Setting, VOH=VDDQ*0.50, 3200-4266Mbps)
[Model]   DQS_PD80_SOC-ODT48_VOH50_4266
Model_type   I/O
Vinl = 90.000mV
Vinh = 210.000mV
Vmeas = 150.000mV
Vref = 0.0mV
Cref = 0.0pF
Rref = 48.000Ohm
|   typ   min   max
|C_comp   0.849pF   0.799pF   0.899pF
C_comp_pullup   0.4245pF   0.3995pF   0.4495pF
C_comp_pulldown   0.4245pF   0.3995pF   0.4495pF
| Note: C_comp changes when the ODT circuit is enabled.
[Model Spec]
| Input threshold voltage corners
Vinl   0.0900V   0.0825V   0.1025V
Vinh   0.2100V   0.2025V   0.2225V
| Measurement voltage corners
Vmeas   0.1500V   0.1425V   0.1625V
| Timing spec test load voltage corners
Vref   0.0000V   0.0000V   0.0000V
| Dynamic Overshoot Parameters from LPDDR4_0P6 Specification
D_overshoot_ampl_h   0.30   NA   NA
D_overshoot_ampl_l   0.30   NA   NA
D_overshoot_area_h   0.1n   NA   NA
D_overshoot_area_l   0.1n   NA   NA
[Voltage Range]   0.6000V   0.5700V   0.6500V
[Pullup Reference]   0.6000V   0.5700V   0.6500V
| Junction Temperature (Ambient temp is 35C typ 95C min -40C max)
[Temperature Range]   50.0   110.0   -40.0
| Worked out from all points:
|   slope of the pulldown table from 0 to 0.09 V, typ, clamps not added: 75.3 ohm
|   slope of the pullup table from 0 to 0.09 V, typ, clamps not added: 60.5 ohm
|   GND clamp passes 1 mA (typ) near -0.45 V on its own axis
|   rising waveform, R_fixture 50, V_fixture 0.0: 20-80 % time 34.4ps typ, 39.5ps min, 29.6ps max; typ from 0 V to 0.306 V
|   falling waveform, R_fixture 50, V_fixture 0.6: 20-80 % time 48.3ps typ, 57.6ps min, 40ps max; typ from 0.6 V to 0.375 V
|   rising waveform, R_fixture 50, V_fixture 0.6: 20-80 % time 41.1ps typ, 47.9ps min, 31.4ps max; typ from 0.375 V to 0.6 V
|   falling waveform, R_fixture 50, V_fixture 0.0: 20-80 % time 37.1ps typ, 43.8ps min, 33.1ps max; typ from 0.306 V to 0 V
[Pulldown]
|   Voltage   I(typ)   I(min)   I(max)
-600mV    -19.04mA   -16.87mA   -21.44mA
-481.2mV  -13.94mA   -11.86mA   -16.31mA
-348mV    -7.734mA   -6.597mA   -9.22mA
-292.2mV  -5.588mA   -4.954mA   -6.501mA
-249mV    -4.27mA    -3.943mA   -4.756mA
-204mV    -3.201mA   -3.07mA    -3.366mA
-153.6mV  -2.262mA   -2.229mA   -2.266mA
181.2mV   2.333mA    2.308mA    2.354mA
480mV     5.497mA    5.261mA    5.831mA
660mV     6.871mA    6.378mA    7.593mA
823.8mV   7.768mA    7.068mA    8.91mA
1.2V      9.057mA    8.141mA    10.84mA
[GND Clamp]
|   Voltage   I(typ)   I(min)   I(max)
-600mV    -5.439mA   -3.802mA   -7.294mA
-565.8mV  -4.041mA   -2.789mA   -5.405mA
-537mV    -3.031mA   -2.085mA   -3.985mA
-508.2mV  -2.193mA   -1.512mA   -2.769mA
-483mV    -1.606mA   -1.109mA   -1.913mA
-456mV    -1.114mA   -767.1uA   -1.228mA
-429mV    -741.8uA   -509.2uA   -756.6uA
-394.8mV  -414.6uA   -283.8uA   -382.1uA
-358.8mV  -204.5uA   -140.9uA   -167.3uA
-299.4mV  -51.38uA   -37.49uA   -33.2uA
-198.6mV  -2.803uA   -2.69uA    -1.006uA
1.2V      0A         0A         0A
[Pullup]
|   Voltage   I(typ)   I(min)   I(max)
-600mV    2.327mA    1.755mA    3.187mA
-272.4mV  1.691mA    1.26mA     2.314mA
-141mV    1.268mA    959.6uA    1.7mA
-81.6mV   885.2uA    695.7uA    1.154mA
-18.6mV   238.8uA    196.3uA    301uA
82.2mV    -1.339mA   -1.209mA   -1.564mA
192mV     -3.652mA   -3.532mA   -4.053mA
357.6mV   -7.723mA   -7.819mA   -8.258mA
636.6mV   -15.28mA   -15.72mA   -15.98mA
984mV     -25.11mA   -25.69mA   -26.14mA
1.106V    -28.3mA    -28.89mA   -29.59mA
1.2V      -30.35mA   -30.94mA   -31.76mA
[POWER Clamp]
|   Voltage   I(typ)   I(min)   I(max)
-600mV    870.6nA    22uA       72.65nA
-589.2mV  630.2nA    16.59uA    68.66nA
-576.6mV  439.1nA    11.87uA    64.76nA
-564mV    312.7nA    8.459uA    61.06nA
-549.6mV  219.2nA    5.723uA    57.05nA
-531.6mV  149nA      3.499uA    52.35nA
-511.8mV  106.2nA    2.04uA     47.56nA
-486.6mV  77.2nA     1.041uA    41.98nA
-457.8mV  60.48nA    497nA      36.26nA
-405.6mV  45.89nA    157.9nA    27.53nA
-303mV    31.59nA    51.63nA    15.37nA
1.2V      0A         0A         0A
[Ramp]
|   typ   min   max
| 20% - 80%
dV/dt_r   183.25m/34.40p   173.07m/39.54p   206.70m/29.56p
dV/dt_f   135.04m/48.33p   126.59m/57.60p   149.26m/40.02p
| 25% - 75%
|dV/dt_r   152.71m/27.23p   144.23m/31.28p   172.25m/23.37p
|dV/dt_f   112.53m/38.16p   105.49m/45.58p   124.38m/31.61p
R_load = 50
[Rising Waveform]
R_fixture = 50
V_fixture = 0.0
|   Time   V(typ)   V(min)   V(max)
0s        192.6uV    176.5uV    91uV
60ps      612.7uV    -578.5uV   11.18mV
68ps      3.771mV    -749.1uV   52.79mV
80ps      19.78mV    1.728mV    156.4mV
95ps      104.2mV    9.314mV    256.1mV
108ps     185.1mV    40.99mV    301mV
126ps     252.7mV    133.5mV    328.7mV
153ps     291mV      234.9mV    341.2mV
186ps     302.7mV    275.7mV    344mV
397ps     305.6mV    288.6mV    344.6mV
[Falling Waveform]
R_fixture   = 50
V_fixture   = 0.6
V_fixture_min = 0.57
V_fixture_max = 0.65
|   Time   V(typ)   V(min)   V(max)
0s        600mV      570mV      650mV
72ps      598.3mV    571.1mV    639.5mV
79ps      595.1mV    570mV      617.3mV
94ps      583.3mV    564.4mV    540mV
111ps     529.7mV    558.6mV    477mV
127ps     474.4mV    539.4mV    443.3mV
153ps     419.2mV    468.7mV    417.1mV
186ps     390mV      405.4mV    405.8mV
226ps     379mV      373.9mV    402.3mV
397ps     374.9mV    359mV      401.3mV
[Rising Waveform]
R_fixture   = 50
V_fixture   = 0.6
V_fixture_min = 0.57
V_fixture_max = 0.65
|   Time   V(typ)   V(min)   V(max)
0s        374.9mV    358.8mV    401.2mV
58ps      374.3mV    356.6mV    412mV
66ps      382.1mV    356mV      436.2mV
74ps      399.6mV    359.2mV    481.3mV
95ps      481.5mV    405.6mV    585.3mV
111ps     533.4mV    461mV      620.4mV
128ps     566.4mV    503.5mV    636.8mV
155ps     588.8mV    543.7mV    646.2mV
192ps     597.4mV    563.2mV    649.2mV
397ps     600mV      570mV      650mV
[Falling Waveform]
R_fixture = 50
V_fixture = 0.0
|   Time   V(typ)   V(min)   V(max)
0s        305.7mV    288.7mV    344.6mV
63ps      308.9mV    291.1mV    336mV
71ps      305.7mV    292.7mV    300.6mV
81ps      286.5mV    291.9mV    211.1mV
97ps      198mV      270.3mV    105.8mV
115ps     98.27mV    194.6mV    50.36mV
134ps     46.79mV    107.5mV    23.24mV
161ps     16.8mV     40.5mV     7.841mV
198ps     4.353mV    10.72mV    1.904mV
397ps     259.6uV    270.1uV    118.2uV
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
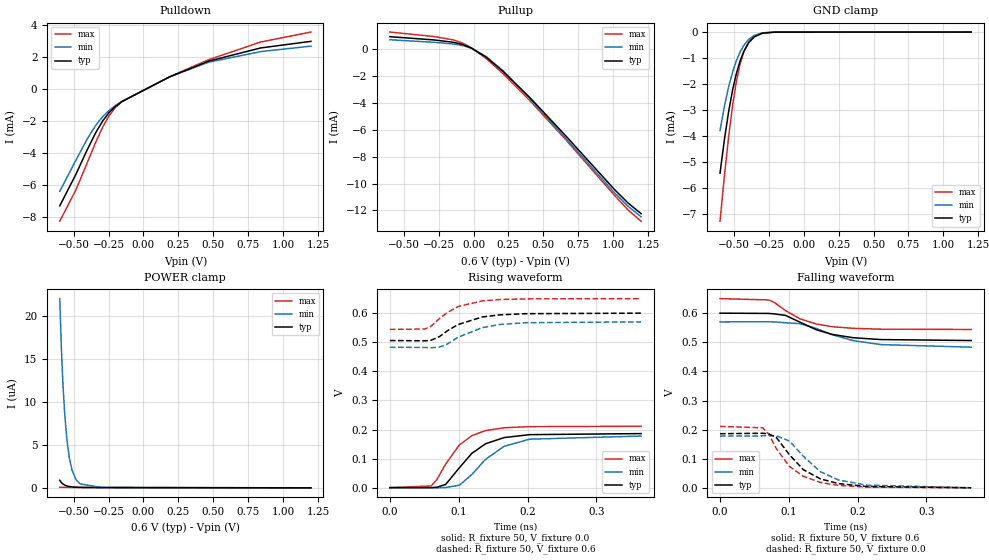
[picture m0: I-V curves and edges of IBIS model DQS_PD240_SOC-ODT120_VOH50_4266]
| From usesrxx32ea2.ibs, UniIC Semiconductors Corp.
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| DQS_PD240_SOC-ODT120_VOH50_4266
| (240 Ohm Pulldown, 120 Ohm System ODT Setting, VOH=VDDQ*0.50, 3200-4266Mbps)
[Model]   DQS_PD240_SOC-ODT120_VOH50_4266
Model_type   I/O
Vinl = 90.000mV
Vinh = 210.000mV
Vmeas = 150.000mV
Vref = 0.0mV
Cref = 0.0pF
Rref = 120.000Ohm
|   typ   min   max
|C_comp   0.849pF   0.799pF   0.899pF
C_comp_pullup   0.4245pF   0.3995pF   0.4495pF
C_comp_pulldown   0.4245pF   0.3995pF   0.4495pF
| Note: C_comp changes when the ODT circuit is enabled.
[Model Spec]
| Input threshold voltage corners
Vinl   0.0900V   0.0825V   0.1025V
Vinh   0.2100V   0.2025V   0.2225V
| Measurement voltage corners
Vmeas   0.1500V   0.1425V   0.1625V
| Timing spec test load voltage corners
Vref   0.0000V   0.0000V   0.0000V
| Dynamic Overshoot Parameters from LPDDR4_0P6 Specification
D_overshoot_ampl_h   0.30   NA   NA
D_overshoot_ampl_l   0.30   NA   NA
D_overshoot_area_h   0.1n   NA   NA
D_overshoot_area_l   0.1n   NA   NA
[Voltage Range]   0.6000V   0.5700V   0.6500V
[Pullup Reference]   0.6000V   0.5700V   0.6500V
| Junction Temperature (Ambient temp is 35C typ 95C min -40C max)
[Temperature Range]   50.0   110.0   -40.0
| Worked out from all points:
|   slope of the pulldown table from 0 to 0.09 V, typ, clamps not added: 230 ohm
|   slope of the pullup table from 0 to 0.09 V, typ, clamps not added: 150 ohm
|   GND clamp passes 1 mA (typ) near -0.45 V on its own axis
|   rising waveform, R_fixture 50, V_fixture 0.0: 20-80 % time 45.9ps typ, 50.5ps min, 40.1ps max; typ from 0 V to 0.186 V
|   falling waveform, R_fixture 50, V_fixture 0.6: 20-80 % time 60.8ps typ, 70.5ps min, 51.7ps max; typ from 0.6 V to 0.506 V
|   rising waveform, R_fixture 50, V_fixture 0.6: 20-80 % time 47.4ps typ, 50ps min, 41.3ps max; typ from 0.506 V to 0.6 V
|   falling waveform, R_fixture 50, V_fixture 0.0: 20-80 % time 48ps typ, 52.9ps min, 44.3ps max; typ from 0.186 V to 0 V
[Pulldown]
|   Voltage   I(typ)   I(min)   I(max)
-600mV    -7.274mA   -6.365mA   -8.238mA
-484.8mV  -5.311mA   -4.434mA   -6.284mA
-403.8mV  -3.782mA   -3.1mA     -4.601mA
-342.6mV  -2.708mA   -2.249mA   -3.305mA
-290.4mV  -1.945mA   -1.682mA   -2.319mA
-247.2mV  -1.454mA   -1.319mA   -1.652mA
-204mV    -1.083mA   -1.025mA   -1.151mA
-153.6mV  -754.8uA   -738.1uA   -755.9uA
188.4mV   792.8uA    786uA      796.5uA
465.6mV   1.764mA    1.699mA    1.853mA
840mV     2.593mA    2.364mA    2.964mA
1.2V      3.005mA    2.705mA    3.586mA
[GND Clamp]
|   Voltage   I(typ)   I(min)   I(max)
-600mV    -5.439mA   -3.802mA   -7.294mA
-567.6mV  -4.11mA    -2.837mA   -5.5mA
-537mV    -3.03mA    -2.085mA   -3.984mA
-510mV    -2.24mA    -1.544mA   -2.838mA
-483mV    -1.606mA   -1.109mA   -1.913mA
-456mV    -1.113mA   -768uA     -1.229mA
-429mV    -741.3uA   -510.2uA   -757uA
-394.8mV  -414.9uA   -284.1uA   -381.5uA
-355.2mV  -189.5uA   -130.8uA   -152.7uA
-297.6mV  -49.16uA   -35.9uA    -31.62uA
-207.6mV  -3.761uA   -3.457uA   -1.442uA
1.2V      0A         0A         0A
[Pullup]
|   Voltage   I(typ)   I(min)   I(max)
-600mV    931.5uA    702.4uA    1.276mA
-283.2mV  687.2uA    512.1uA    941uA
-141mV    508uA      384.5uA    681.8uA
-74.4mV   330.6uA    261.2uA    429.9uA
-15mV     77.75uA    64.4uA     98.26uA
89.4mV    -595uA     -540.4uA   -691.8uA
211.8mV   -1.66mA    -1.621mA   -1.83mA
402.6mV   -3.598mA   -3.668mA   -3.823mA
652.8mV   -6.367mA   -6.555mA   -6.65mA
1.007V    -10.42mA   -10.66mA   -10.85mA
1.108V    -11.46mA   -11.7mA    -11.98mA
1.2V      -12.24mA   -12.48mA   -12.81mA
[POWER Clamp]
|   Voltage   I(typ)   I(min)   I(max)
-600mV    870.6nA    21.99uA    72.65nA
-589.2mV  630.1nA    16.59uA    68.66nA
-583.8mV  538.6nA    14.39uA    66.96nA
-576.6mV  440.3nA    11.87uA    64.76nA
-564mV    312.9nA    8.461uA    61.06nA
-549.6mV  219.4nA    5.713uA    57.05nA
-531.6mV  149.1nA    3.495uA    52.36nA
-511.8mV  105.9nA    2.042uA    47.56nA
-483mV    74.36nA    947.9nA    41.22nA
-454.2mV  59.01nA    455.7nA    35.6nA
-301.2mV  31.41nA    51.17nA    15.21nA
1.2V      0A         0A         0A
[Ramp]
|   typ   min   max
| 20% - 80%
dV/dt_r   111.50m/45.86p   106.45m/50.54p   126.60m/40.14p
dV/dt_f   56.38m/60.83p   52.06m/70.45p   63.59m/51.68p
| 25% - 75%
|dV/dt_r   92.92m/36.36p   88.71m/40.04p   105.50m/31.81p
|dV/dt_f   46.98m/48.20p   43.38m/55.78p   52.99m/40.93p
R_load = 50
[Rising Waveform]
R_fixture = 50
V_fixture = 0.0
|   Time   V(typ)   V(min)   V(max)
0s        109.2uV    100uV      52.67uV
60ps      172.1uV    -331.1uV   6.007mV
68ps      1.597mV    -538.1uV   26.94mV
81ps      11mV       583uV      81.15mV
101ps     68.5mV     8.479mV    147mV
119ps     117.9mV    45.1mV     178.8mV
139ps     150.9mV    97.46mV    196.3mV
166ps     172.2mV    142.1mV    206mV
203ps     182.3mV    166.7mV    209.9mV
365ps     185.9mV    177.5mV    211.1mV
[Falling Waveform]
R_fixture   = 50
V_fixture   = 0.6
V_fixture_min = 0.57
V_fixture_max = 0.65
|   Time   V(typ)   V(min)   V(max)
0s        600mV      570mV      650mV
71ps      599.1mV    570.5mV    645.4mV
79ps      597.4mV    569.9mV    636.9mV
95ps      592.5mV    567.1mV    609.1mV
116ps     569.3mV    563.9mV    580.9mV
140ps     543mV      547.5mV    562.7mV
163ps     527mV      526mV      553.5mV
194ps     515.5mV    505.4mV    547.8mV
234ps     509.3mV    492mV      545.1mV
365ps     506mV      483.2mV    544mV
[Rising Waveform]
R_fixture   = 50
V_fixture   = 0.6
V_fixture_min = 0.57
V_fixture_max = 0.65
|   Time   V(typ)   V(min)   V(max)
0s        505.9mV    482.8mV    544mV
51ps      504.9mV    481.9mV    545.7mV
60ps      507mV      481.1mV    555.2mV
72ps      519.3mV    483.2mV    581.1mV
83ps      538.5mV    493mV      601.6mV
99ps      560.7mV    517mV      622.6mV
134ps     586.8mV    550.2mV    642.1mV
160ps     594.2mV    561.1mV    646.8mV
198ps     598.2mV    567.2mV    649.1mV
365ps     600mV      570mV      650mV
[Falling Waveform]
R_fixture = 50
V_fixture = 0.0
|   Time   V(typ)   V(min)   V(max)
0s        186mV      177.7mV    211.1mV
62ps      187.5mV    178.6mV    206.2mV
71ps      185.4mV    179.5mV    184mV
82ps      172.6mV    178.7mV    134mV
101ps     113.5mV    160.7mV    73.17mV
121ps     62.61mV    108.5mV    39.77mV
146ps     30.71mV    55.16mV    18.62mV
172ps     14.73mV    27.28mV    8.514mV
212ps     4.893mV    9.488mV    2.572mV
365ps     247.7uV    380.7uV    105.1uV
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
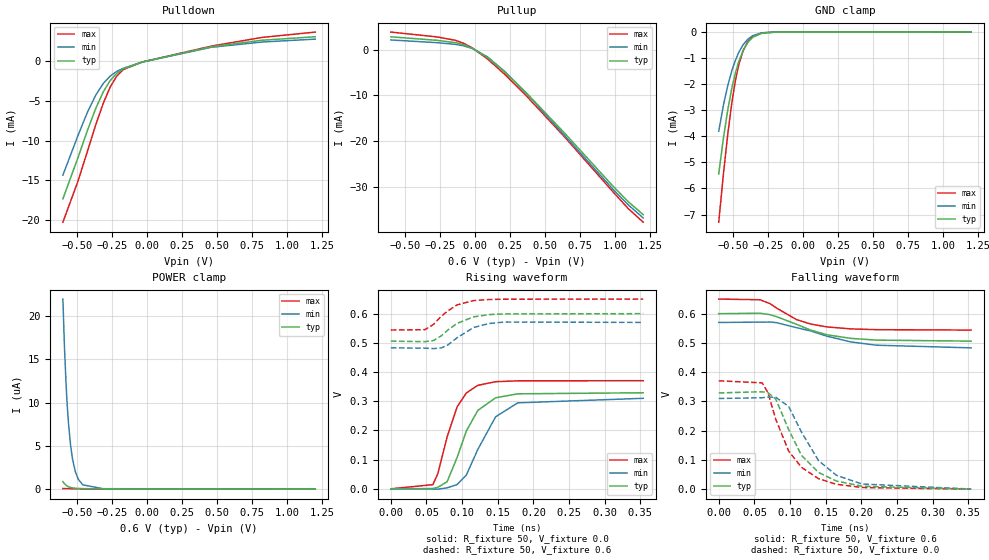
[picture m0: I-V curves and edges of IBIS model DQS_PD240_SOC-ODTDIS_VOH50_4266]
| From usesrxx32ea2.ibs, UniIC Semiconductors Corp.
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| DQS_PD240_SOC-ODTDIS_VOH50_4266
| (240 Ohm Pulldown, SOC ODT disabled setting, VOH=VDDQ*0.50 cal. point, 3200-4266Mbps)
[Model]   DQS_PD240_SOC-ODTDIS_VOH50_4266
Model_type   I/O
Vinl = 90.000mV
Vinh = 210.000mV
Vmeas = 150.000mV
Vref = 0.0mV
Cref = 0.0pF
|   typ   min   max
|C_comp   0.849pF   0.799pF   0.899pF
C_comp_pullup   0.4245pF   0.3995pF   0.4495pF
C_comp_pulldown   0.4245pF   0.3995pF   0.4495pF
| Note: C_comp changes when the ODT circuit is enabled.
[Model Spec]
| Input threshold voltage corners
Vinl   0.0900V   0.0825V   0.1025V
Vinh   0.2100V   0.2025V   0.2225V
| Measurement voltage corners
Vmeas   0.1500V   0.1425V   0.1625V
| Timing spec test load voltage corners
Vref   0.0000V   0.0000V   0.0000V
| Dynamic Overshoot Parameters from LPDDR4_0P6 Specification
D_overshoot_ampl_h   0.30   NA   NA
D_overshoot_ampl_l   0.30   NA   NA
D_overshoot_area_h   0.1n   NA   NA
D_overshoot_area_l   0.1n   NA   NA
[Voltage Range]   0.6000V   0.5700V   0.6500V
[Pullup Reference]   0.6000V   0.5700V   0.6500V
| Junction Temperature (Ambient temp is 35C typ 95C min -40C max)
[Temperature Range]   50.0   110.0   -40.0
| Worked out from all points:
|   slope of the pulldown table from 0 to 0.09 V, typ, clamps not added: 227 ohm
|   slope of the pullup table from 0 to 0.09 V, typ, clamps not added: 50.8 ohm
|   GND clamp passes 1 mA (typ) near -0.45 V on its own axis
|   rising waveform, R_fixture 50, V_fixture 0.0: 20-80 % time 33.1ps typ, 38.3ps min, 27.8ps max; typ from 0 V to 0.329 V
|   falling waveform, R_fixture 50, V_fixture 0.6: 20-80 % time 65.4ps typ, 84.2ps min, 52.1ps max; typ from 0.6 V to 0.506 V
|   rising waveform, R_fixture 50, V_fixture 0.6: 20-80 % time 34.9ps typ, 31.8ps min, 31.3ps max; typ from 0.506 V to 0.6 V
|   falling waveform, R_fixture 50, V_fixture 0.0: 20-80 % time 45.9ps typ, 49.5ps min, 42.7ps max; typ from 0.329 V to 0.001 V
[Pulldown]
|   Voltage   I(typ)   I(min)   I(max)
-600mV    -17.3mA    -14.33mA   -20.23mA
-492mV    -12.12mA   -9.353mA   -15.07mA
-423.6mV  -8.67mA    -6.397mA   -11.27mA
-366mV    -5.99mA    -4.318mA   -8.044mA
-312mV    -3.899mA   -2.849mA   -5.319mA
-263.4mV  -2.498mA   -1.936mA   -3.317mA
-216.6mV  -1.597mA   -1.346mA   -1.939mA
-169.8mV  -1.031mA   -939.7uA   -1.114mA
-33mV     -163.7uA   -162.2uA   -154.5uA
460.2mV   1.748mA    1.685mA    1.835mA
820.2mV   2.563mA    2.341mA    2.917mA
1.2V      3.005mA    2.705mA    3.586mA
[GND Clamp]
|   Voltage   I(typ)   I(min)   I(max)
-600mV    -5.439mA   -3.802mA   -7.294mA
-565.8mV  -4.041mA   -2.789mA   -5.405mA
-535.2mV  -2.973mA   -2.046mA   -3.902mA
-506.4mV  -2.147mA   -1.48mA    -2.701mA
-481.2mV  -1.569mA   -1.083mA   -1.86mA
-456mV    -1.113mA   -767uA     -1.229mA
-425.4mV  -700.9uA   -480.7uA   -707.1uA
-393mV    -401.3uA   -274.9uA   -367.1uA
-357mV    -197.1uA   -135.9uA   -159.6uA
-292.2mV  -42.81uA   -31.52uA   -26.86uA
-198.6mV  -2.808uA   -2.691uA   -999.3nA
1.2V      0A         0A         0A
[Pullup]
|   Voltage   I(typ)   I(min)   I(max)
-600mV    2.791mA    2.105mA    3.822mA
-270.6mV  2.022mA    1.507mA    2.767mA
-139.2mV  1.508mA    1.143mA    2.02mA
-83.4mV   1.078mA    845.6uA    1.404mA
-16.8mV   258.7uA    213.9uA    325.9uA
89.4mV    -1.76mA    -1.598mA   -2.045mA
210mV     -4.845mA   -4.719mA   -5.346mA
363mV     -9.355mA   -9.472mA   -9.998mA
638.4mV   -18.23mA   -18.74mA   -19.06mA
984mV     -29.84mA   -30.53mA   -31.08mA
1.094V    -33.28mA   -33.97mA   -34.78mA
1.2V      -36.08mA   -36.8mA    -37.73mA
[POWER Clamp]
|   Voltage   I(typ)   I(min)   I(max)
-600mV    870.6nA    21.99uA    72.65nA
-589.2mV  630.1nA    16.59uA    68.66nA
-576.6mV  439.1nA    11.87uA    64.76nA
-569.4mV  361.3nA    9.78uA     62.62nA
-560.4mV  285.5nA    7.686uA    60.03nA
-546mV    201.9nA    5.186uA    56.09nA
-531.6mV  149.1nA    3.496uA    52.35nA
-511.8mV  106nA      2.042uA    47.55nA
-490.2mV  80.19nA    1.144uA    42.74nA
-457.8mV  60.49nA    497.2nA    36.26nA
-313.8mV  32.75nA    54.8nA     16.39nA
1.2V      0A         0A         0A
[Ramp]
|   typ   min   max
| 20% - 80%
dV/dt_r   197.25m/33.12p   185.89m/38.25p   222.23m/27.81p
dV/dt_f   56.38m/65.43p   52.06m/84.18p   63.59m/52.14p
| 25% - 75%
|dV/dt_r   164.38m/26.18p   154.91m/30.24p   185.19m/22.04p
|dV/dt_f   46.98m/51.34p   43.38m/64.98p   52.99m/41.11p
R_load = 50
[Rising Waveform]
R_fixture = 50
V_fixture = 0.0
|   Time   V(typ)   V(min)   V(max)
0s        339uV      323.3uV    157.3uV
59ps      1.028mV    -909.1uV   14.43mV
66ps      5.385mV    -1.029mV   52.64mV
79ps      24.6mV     3.496mV    178.1mV
93ps      107.7mV    14.84mV    280.7mV
106ps     198.5mV    47.43mV    328.7mV
122ps     268.7mV    135mV      354.5mV
147ps     311.9mV    246.8mV    367mV
178ps     325.5mV    294.6mV    370mV
354ps     329.1mV    310.1mV    370.5mV
[Falling Waveform]
R_fixture   = 50
V_fixture   = 0.6
V_fixture_min = 0.57
V_fixture_max = 0.65
|   Time   V(typ)   V(min)   V(max)
0s        600mV      570mV      650mV
58ps      601.5mV    571.2mV    647.6mV
72ps      596.7mV    571.6mV    634.3mV
81ps      589.9mV    569.4mV    619.5mV
109ps     563.9mV    552.3mV    579.8mV
129ps     543.7mV    540.9mV    564.6mV
152ps     527.9mV    523.1mV    554.7mV
185ps     515.7mV    503.6mV    548.1mV
221ps     509.7mV    492.3mV    545.4mV
354ps     506.1mV    483.2mV    544mV
[Rising Waveform]
R_fixture   = 50
V_fixture   = 0.6
V_fixture_min = 0.57
V_fixture_max = 0.65
|   Time   V(typ)   V(min)   V(max)
0s        505.9mV    482.8mV    544mV
48ps      504.2mV    482mV      545.2mV
60ps      508.1mV    480.3mV    563.5mV
71ps      524.4mV    482.8mV    591.6mV
80ps      544mV      492.8mV    609.6mV
93ps      566.8mV    517.7mV    630mV
116ps     589mV      552.5mV    644.8mV
138ps     596.9mV    566.4mV    648.5mV
160ps     599.2mV    571.4mV    649.5mV
354ps     600mV      570mV      650mV
[Falling Waveform]
R_fixture = 50
V_fixture = 0.0
|   Time   V(typ)   V(min)   V(max)
0s        329.2mV    310.2mV    370.6mV
61ps      333.1mV    312.7mV    363.6mV
69ps      330.1mV    314.9mV    330mV
80ps      308.3mV    314.3mV    239.1mV
98ps      204.4mV    283.2mV    130.7mV
116ps     115.9mV    195.4mV    74.77mV
140ps     57.14mV    97.72mV    36.06mV
165ps     28.08mV    47.72mV    16.94mV
201ps     10.31mV    17.87mV    5.83mV
354ps     517uV      697.4uV    244.9uV
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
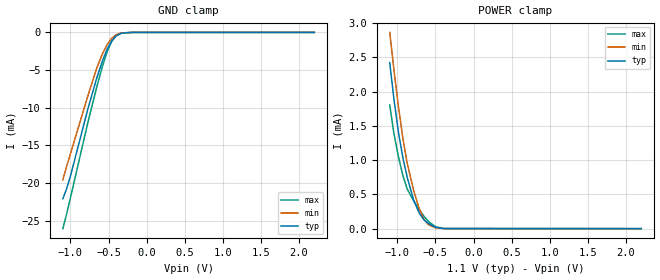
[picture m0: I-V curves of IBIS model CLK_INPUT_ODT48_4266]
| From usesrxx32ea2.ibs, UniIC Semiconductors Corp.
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| CLK_INPUT_ODT48_4266 (with 48ohm ODT, 3200-4266Mbps)
[Model]   CLK_INPUT_ODT48_4266
Model_type   Input
Vinl = 190.000mV
Vinh = 360.000mV
|   typ   min   max
|C_comp   0.639pF   0.587pF   0.706pF
C_comp_power_clamp   0.3195pF   0.2935pF   0.3530pF
C_comp_gnd_clamp   0.3195pF   0.2935pF   0.3530pF
| Note: C_comp changes when the ODT circuit is enabled.
[Model Spec]
| Input threshold voltage corners
Vinl   0.1900V   0.1800V   0.2075V
Vinh   0.3600V   0.3500V   0.3775V
| Dynamic Overshoot Parameters from LPDDR4_0P6 Specification
D_overshoot_ampl_h   0.30   NA   NA
D_overshoot_ampl_l   0.30   NA   NA
D_overshoot_area_h   0.1n   NA   NA
D_overshoot_area_l   0.1n   NA   NA
[Voltage Range]   1.1000V   1.0600V   1.1700V
[POWER Clamp Reference]   1.1000V   1.0600V   1.1700V
| Junction Temperature (Ambient temp is 35C typ 95C min -40C max)
[Temperature Range]   50.0   110.0   -40.0
[Add Submodel]
| Submodel Name   Mode
48ohm_ODT_4266   Non-Driving
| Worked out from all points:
|   GND clamp passes 1 mA (typ) near -0.45 V on its own axis
|   POWER clamp passes 1 mA (typ) near -0.92 V on its own axis
[GND Clamp]
|   Voltage   I(typ)   I(min)   I(max)
-1.1V     -22.11mA   -19.58mA   -26.08mA
-1.05V    -20.77mA   -17.78mA   -24.12mA
-1.004V   -19.23mA   -16.26mA   -22.13mA
-770mV    -10.11mA   -8.366mA   -11.9mA
-651.2mV  -5.93mA    -4.642mA   -7.099mA
-578.6mV  -3.728mA   -2.811mA   -4.447mA
-515.9mV  -2.171mA   -1.575mA   -2.506mA
-459.8mV  -1.132mA   -793.7uA   -1.215mA
-400.4mV  -463.3uA   -311.9uA   -424uA
-331.1mV  -113.4uA   -78.57uA   -81.72uA
-199.1mV  -2.828uA   -2.919uA   -1.089uA
2.2V      0A         0A         0A
[POWER Clamp]
|   Voltage   I(typ)   I(min)   I(max)
-1.1V     2.422mA    2.862mA    1.802mA
-1.044V   1.881mA    2.309mA    1.38mA
-984.5mV  1.398mA    1.769mA    1.042mA
-925.1mV  1.021mA    1.3mA      765.1uA
-869mV    743.1uA    944.6uA    574.6uA
-786.5mV  416.3uA    559.2uA    407.8uA
-713.9mV  230uA      294uA      278.2uA
-651.2mV  129.2uA    136.5uA    180.8uA
-588.5mV  73.96uA    55.75uA    101.4uA
-499.4mV  21.07uA    12.53uA    27.18uA
-387.2mV  1.782uA    1.144uA    1.365uA
2.2V      0A         0A         0A
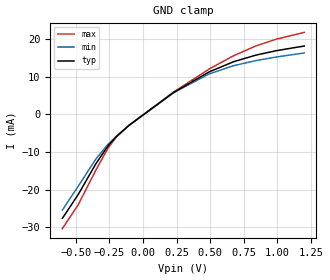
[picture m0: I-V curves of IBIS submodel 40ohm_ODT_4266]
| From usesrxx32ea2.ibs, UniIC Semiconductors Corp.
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| SUBMODEL 40ohm_ODT_4266
[Submodel]   40ohm_ODT_4266
Submodel_type   Dynamic_clamp
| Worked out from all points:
|   GND clamp passes 1 mA (typ) near -0.04 V on its own axis
[GND Clamp]
|   Voltage   I(typ)   I(min)   I(max)
-600mV    -27.61mA   -25.44mA   -30.36mA
-481.2mV  -21.24mA   -19.05mA   -23.95mA
-351.6mV  -13.17mA   -11.9mA    -14.85mA
-258mV    -8.26mA    -7.859mA   -8.843mA
-198.6mV  -5.909mA   -5.804mA   -6.022mA
-103.2mV  -2.905mA   -2.908mA   -2.863mA
228mV     5.818mA    5.729mA    5.93mA
490.8mV   11.25mA    10.72mA    12mA
672.6mV   13.96mA    12.91mA    15.54mA
838.2mV   15.71mA    14.26mA    18.14mA
991.2mV   16.9mA     15.22mA    19.96mA
1.2V      18.15mA    16.3mA     21.76mA
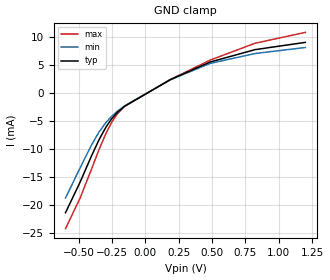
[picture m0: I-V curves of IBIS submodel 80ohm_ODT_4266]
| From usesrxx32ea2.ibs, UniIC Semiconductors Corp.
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| SUBMODEL 80ohm_ODT_4266
[Submodel]   80ohm_ODT_4266
Submodel_type   Dynamic_clamp
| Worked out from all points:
|   GND clamp passes 1 mA (typ) near -0.07 V on its own axis
[GND Clamp]
|   Voltage   I(typ)   I(min)   I(max)
-600mV    -21.37mA   -18.73mA   -24.22mA
-490.2mV  -15.89mA   -13.36mA   -18.74mA
-407.4mV  -11.36mA   -9.383mA   -13.74mA
-349.8mV  -8.402mA   -7.008mA   -10.18mA
-295.8mV  -6.054mA   -5.234mA   -7.173mA
-252.6mV  -4.552mA   -4.121mA   -5.176mA
-211.2mV  -3.461mA   -3.254mA   -3.702mA
-157.2mV  -2.364mA   -2.308mA   -2.378mA
186.6mV   2.397mA    2.372mA    2.422mA
485.4mV   5.544mA    5.301mA    5.888mA
822mV     7.757mA    7.062mA    8.895mA
1.2V      9.057mA    8.141mA    10.84mA
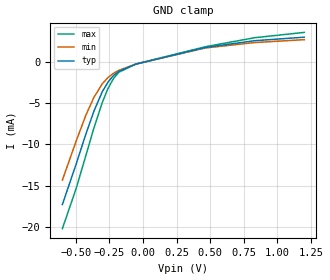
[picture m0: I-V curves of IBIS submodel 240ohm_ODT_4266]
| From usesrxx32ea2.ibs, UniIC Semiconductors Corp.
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| SUBMODEL 240ohm_ODT_4266
[Submodel]   240ohm_ODT_4266
Submodel_type   Dynamic_clamp
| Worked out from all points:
|   GND clamp passes 1 mA (typ) near -0.17 V on its own axis
[GND Clamp]
|   Voltage   I(typ)   I(min)   I(max)
-600mV    -17.3mA    -14.34mA   -20.23mA
-497.4mV  -12.39mA   -9.601mA   -15.35mA
-425.4mV  -8.764mA   -6.47mA    -11.37mA
-366mV    -6.002mA   -4.319mA   -8.044mA
-303mV    -3.605mA   -2.651mA   -4.917mA
-259.8mV  -2.43mA    -1.882mA   -3.191mA
-220.2mV  -1.659mA   -1.384mA   -2.026mA
-178.8mV  -1.127mA   -1.007mA   -1.237mA
-52.8mV   -261uA     -258uA     -248.8uA
463.8mV   1.759mA    1.695mA    1.847mA
831mV     2.579mA    2.353mA    2.942mA
1.2V      3.005mA    2.705mA    3.586mA
